# tools/dsrom_s81_fulldie.py abstract: Banded real register stage
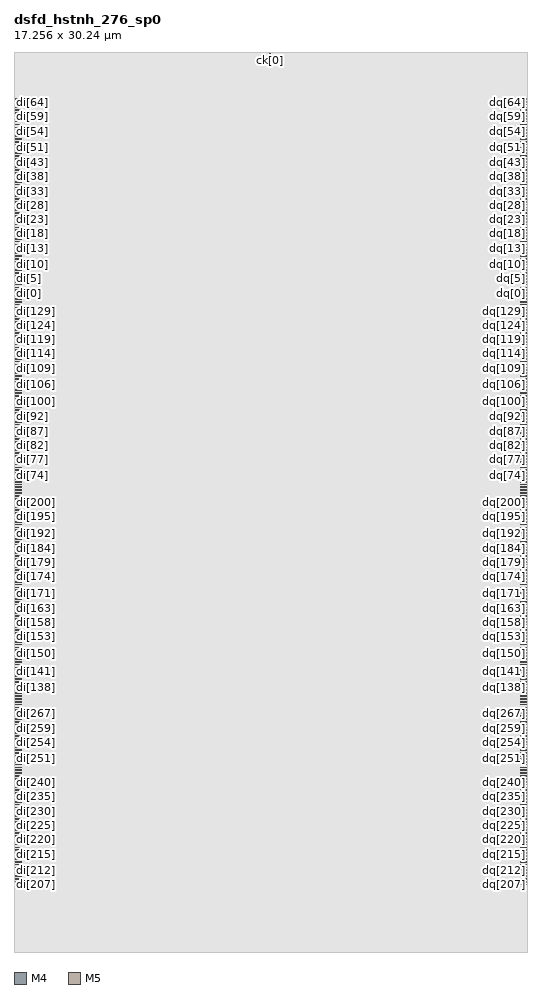
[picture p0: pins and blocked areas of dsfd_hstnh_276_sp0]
MACRO dsfd_hstnh_276_sp0
  CLASS BLOCK ;
  FOREIGN dsfd_hstnh_276_sp0 0 0 ;
  SIZE 17.256 BY 30.240 ;
  SYMMETRY X Y ;
  PIN di[0]
    DIRECTION INOUT ;
    USE SIGNAL ;
    PORT
      LAYER M4 ;
        RECT 0.048 22.128 0.240 22.152 ;
    END
  END di[0]
  PIN di[1]
    DIRECTION INOUT ;
    USE SIGNAL ;
    PORT
      LAYER M4 ;
        RECT 0.048 22.224 0.240 22.248 ;
    END
  END di[1]
  PIN di[2]
    DIRECTION INOUT ;
    USE SIGNAL ;
    PORT
      LAYER M4 ;
        RECT 0.048 22.320 0.240 22.344 ;
    END
  END di[2]
  PIN di[3]
    DIRECTION INOUT ;
    USE SIGNAL ;
    PORT
      LAYER M4 ;
        RECT 0.048 22.416 0.240 22.440 ;
    END
  END di[3]
  PIN di[4]
    DIRECTION INOUT ;
    USE SIGNAL ;
    PORT
      LAYER M4 ;
        RECT 0.048 22.512 0.240 22.536 ;
    END
  END di[4]
  PIN di[5]
    DIRECTION INOUT ;
    USE SIGNAL ;
    PORT
      LAYER M4 ;
        RECT 0.048 22.608 0.240 22.632 ;
    END
  END di[5]
  PIN di[6]
    DIRECTION INOUT ;
    USE SIGNAL ;
    PORT
      LAYER M4 ;
        RECT 0.048 22.704 0.240 22.728 ;
    END
  END di[6]
  PIN di[7]
    DIRECTION INOUT ;
    USE SIGNAL ;
    PORT
      LAYER M4 ;
        RECT 0.048 22.800 0.240 22.824 ;
    END
  END di[7]
  PIN di[8]
    DIRECTION INOUT ;
    USE SIGNAL ;
    PORT
      LAYER M4 ;
        RECT 0.048 22.896 0.240 22.920 ;
    END
  END di[8]
  PIN di[9]
    DIRECTION INOUT ;
    USE SIGNAL ;
    PORT
      LAYER M4 ;
        RECT 0.048 22.992 0.240 23.016 ;
    END
  END di[9]
  PIN di[10]
    DIRECTION INOUT ;
    USE SIGNAL ;
    PORT
      LAYER M4 ;
        RECT 0.048 23.088 0.240 23.112 ;
    END
  END di[10]
  PIN di[11]
    DIRECTION INOUT ;
    USE SIGNAL ;
    PORT
      LAYER M4 ;
        RECT 0.048 23.184 0.240 23.208 ;
    END
  END di[11]
  PIN di[12]
    DIRECTION INOUT ;
    USE SIGNAL ;
    PORT
      LAYER M4 ;
        RECT 0.048 23.280 0.240 23.304 ;
    END
  END di[12]
  PIN di[13]
    DIRECTION INOUT ;
    USE SIGNAL ;
    PORT
      LAYER M4 ;
        RECT 0.048 23.376 0.240 23.400 ;
    END
  END di[13]
  PIN di[14]
    DIRECTION INOUT ;
    USE SIGNAL ;
    PORT
      LAYER M4 ;
        RECT 0.048 23.472 0.240 23.496 ;
    END
  END di[14]
  PIN di[15]
    DIRECTION INOUT ;
    USE SIGNAL ;
    PORT
      LAYER M4 ;
        RECT 0.048 23.568 0.240 23.592 ;
    END
  END di[15]
  PIN di[16]
    DIRECTION INOUT ;
    USE SIGNAL ;
    PORT
      LAYER M4 ;
        RECT 0.048 23.664 0.240 23.688 ;
    END
  END di[16]
  PIN di[17]
    DIRECTION INOUT ;
    USE SIGNAL ;
    PORT
      LAYER M4 ;
        RECT 0.048 23.760 0.240 23.784 ;
    END
  END di[17]
  PIN di[18]
    DIRECTION INOUT ;
    USE SIGNAL ;
    PORT
      LAYER M4 ;
        RECT 0.048 23.856 0.240 23.880 ;
    END
  END di[18]
  PIN di[19]
    DIRECTION INOUT ;
    USE SIGNAL ;
    PORT
      LAYER M4 ;
        RECT 0.048 23.952 0.240 23.976 ;
    END
  END di[19]
  PIN di[20]
    DIRECTION INOUT ;
    USE SIGNAL ;
    PORT
      LAYER M4 ;
        RECT 0.048 24.048 0.240 24.072 ;
    END
  END di[20]
  PIN di[21]
    DIRECTION INOUT ;
    USE SIGNAL ;
    PORT
      LAYER M4 ;
        RECT 0.048 24.144 0.240 24.168 ;
    END
  END di[21]
  PIN di[22]
    DIRECTION INOUT ;
    USE SIGNAL ;
    PORT
      LAYER M4 ;
        RECT 0.048 24.240 0.240 24.264 ;
    END
  END di[22]
  PIN di[23]
    DIRECTION INOUT ;
    USE SIGNAL ;
    PORT
      LAYER M4 ;
        RECT 0.048 24.336 0.240 24.360 ;
    END
  END di[23]
  PIN di[24]
    DIRECTION INOUT ;
    USE SIGNAL ;
    PORT
      LAYER M4 ;
        RECT 0.048 24.432 0.240 24.456 ;
    END
  END di[24]
  PIN di[25]
    DIRECTION INOUT ;
    USE SIGNAL ;
    PORT
      LAYER M4 ;
        RECT 0.048 24.528 0.240 24.552 ;
    END
  END di[25]
  PIN di[26]
    DIRECTION INOUT ;
    USE SIGNAL ;
    PORT
      LAYER M4 ;
        RECT 0.048 24.624 0.240 24.648 ;
    END
  END di[26]
  PIN di[27]
    DIRECTION INOUT ;
    USE SIGNAL ;
    PORT
      LAYER M4 ;
        RECT 0.048 24.720 0.240 24.744 ;
    END
  END di[27]
  PIN di[28]
    DIRECTION INOUT ;
    USE SIGNAL ;
    PORT
      LAYER M4 ;
        RECT 0.048 24.816 0.240 24.840 ;
    END
  END di[28]
  PIN di[29]
    DIRECTION INOUT ;
    USE SIGNAL ;
    PORT
      LAYER M4 ;
        RECT 0.048 24.912 0.240 24.936 ;
    END
  END di[29]
  PIN di[30]
    DIRECTION INOUT ;
    USE SIGNAL ;
    PORT
      LAYER M4 ;
        RECT 0.048 25.008 0.240 25.032 ;
    END
  END di[30]
  PIN di[31]
    DIRECTION INOUT ;
    USE SIGNAL ;
    PORT
      LAYER M4 ;
        RECT 0.048 25.104 0.240 25.128 ;
    END
  END di[31]
  PIN di[32]
    DIRECTION INOUT ;
    USE SIGNAL ;
    PORT
      LAYER M4 ;
        RECT 0.048 25.200 0.240 25.224 ;
    END
  END di[32]
  PIN di[33]
    DIRECTION INOUT ;
    USE SIGNAL ;
    PORT
      LAYER M4 ;
        RECT 0.048 25.296 0.240 25.320 ;
    END
  END di[33]
  PIN di[34]
    DIRECTION INOUT ;
    USE SIGNAL ;
    PORT
      LAYER M4 ;
        RECT 0.048 25.392 0.240 25.416 ;
    END
  END di[34]
  PIN di[35]
    DIRECTION INOUT ;
    USE SIGNAL ;
    PORT
      LAYER M4 ;
        RECT 0.048 25.488 0.240 25.512 ;
    END
  END di[35]
  PIN di[36]
    DIRECTION INOUT ;
    USE SIGNAL ;
    PORT
      LAYER M4 ;
        RECT 0.048 25.584 0.240 25.608 ;
    END
  END di[36]
  PIN di[37]
    DIRECTION INOUT ;
    USE SIGNAL ;
    PORT
      LAYER M4 ;
        RECT 0.048 25.680 0.240 25.704 ;
    END
  END di[37]
  PIN di[38]
    DIRECTION INOUT ;
    USE SIGNAL ;
    PORT
      LAYER M4 ;
        RECT 0.048 25.776 0.240 25.800 ;
    END
  END di[38]
  PIN di[39]
    DIRECTION INOUT ;
    USE SIGNAL ;
    PORT
      LAYER M4 ;
        RECT 0.048 25.872 0.240 25.896 ;
    END
  END di[39]
  PIN di[40]
    DIRECTION INOUT ;
    USE SIGNAL ;
    PORT
      LAYER M4 ;
        RECT 0.048 25.968 0.240 25.992 ;
    END
  END di[40]
  PIN di[41]
    DIRECTION INOUT ;
    USE SIGNAL ;
    PORT
      LAYER M4 ;
        RECT 0.048 26.064 0.240 26.088 ;
    END
  END di[41]
  PIN di[42]
    DIRECTION INOUT ;
    USE SIGNAL ;
    PORT
      LAYER M4 ;
        RECT 0.048 26.160 0.240 26.184 ;
    END
  END di[42]
  PIN di[43]
    DIRECTION INOUT ;
    USE SIGNAL ;
    PORT
      LAYER M4 ;
        RECT 0.048 26.256 0.240 26.280 ;
    END
  END di[43]
  PIN di[44]
    DIRECTION INOUT ;
    USE SIGNAL ;
    PORT
      LAYER M4 ;
        RECT 0.048 26.352 0.240 26.376 ;
    END
  END di[44]
  PIN di[45]
    DIRECTION INOUT ;
    USE SIGNAL ;
    PORT
      LAYER M4 ;
        RECT 0.048 26.448 0.240 26.472 ;
    END
  END di[45]
  PIN di[46]
    DIRECTION INOUT ;
    USE SIGNAL ;
    PORT
      LAYER M4 ;
        RECT 0.048 26.544 0.240 26.568 ;
    END
  END di[46]
  PIN di[47]
    DIRECTION INOUT ;
    USE SIGNAL ;
    PORT
      LAYER M4 ;
        RECT 0.048 26.640 0.240 26.664 ;
    END
  END di[47]
  PIN di[48]
    DIRECTION INOUT ;
    USE SIGNAL ;
    PORT
      LAYER M4 ;
        RECT 0.048 26.736 0.240 26.760 ;
    END
  END di[48]
  PIN di[49]
    DIRECTION INOUT ;
    USE SIGNAL ;
    PORT
      LAYER M4 ;
        RECT 0.048 26.832 0.240 26.856 ;
    END
  END di[49]
  PIN di[50]
    DIRECTION INOUT ;
    USE SIGNAL ;
    PORT
      LAYER M4 ;
        RECT 0.048 26.928 0.240 26.952 ;
    END
  END di[50]
  PIN di[51]
    DIRECTION INOUT ;
    USE SIGNAL ;
    PORT
      LAYER M4 ;
        RECT 0.048 27.024 0.240 27.048 ;
    END
  END di[51]
  PIN di[52]
    DIRECTION INOUT ;
    USE SIGNAL ;
    PORT
      LAYER M4 ;
        RECT 0.048 27.120 0.240 27.144 ;
    END
  END di[52]
  PIN di[53]
    DIRECTION INOUT ;
    USE SIGNAL ;
    PORT
      LAYER M4 ;
        RECT 0.048 27.216 0.240 27.240 ;
    END
  END di[53]
  PIN di[54]
    DIRECTION INOUT ;
    USE SIGNAL ;
    PORT
      LAYER M4 ;
        RECT 0.048 27.312 0.240 27.336 ;
    END
  END di[54]
  PIN di[55]
    DIRECTION INOUT ;
    USE SIGNAL ;
    PORT
      LAYER M4 ;
        RECT 0.048 27.408 0.240 27.432 ;
    END
  END di[55]
  PIN di[56]
    DIRECTION INOUT ;
    USE SIGNAL ;
    PORT
      LAYER M4 ;
        RECT 0.048 27.504 0.240 27.528 ;
    END
  END di[56]
  PIN di[57]
    DIRECTION INOUT ;
    USE SIGNAL ;
    PORT
      LAYER M4 ;
        RECT 0.048 27.600 0.240 27.624 ;
    END
  END di[57]
  PIN di[58]
    DIRECTION INOUT ;
    USE SIGNAL ;
    PORT
      LAYER M4 ;
        RECT 0.048 27.696 0.240 27.720 ;
    END
  END di[58]
  PIN di[59]
    DIRECTION INOUT ;
    USE SIGNAL ;
    PORT
      LAYER M4 ;
        RECT 0.048 27.792 0.240 27.816 ;
    END
  END di[59]
  PIN di[60]
    DIRECTION INOUT ;
    USE SIGNAL ;
    PORT
      LAYER M4 ;
        RECT 0.048 27.888 0.240 27.912 ;
    END
  END di[60]
  PIN di[61]
    DIRECTION INOUT ;
    USE SIGNAL ;
    PORT
      LAYER M4 ;
        RECT 0.048 27.984 0.240 28.008 ;
    END
  END di[61]
  PIN di[62]
    DIRECTION INOUT ;
    USE SIGNAL ;
    PORT
      LAYER M4 ;
        RECT 0.048 28.080 0.240 28.104 ;
    END
  END di[62]
  PIN di[63]
    DIRECTION INOUT ;
    USE SIGNAL ;
    PORT
      LAYER M4 ;
        RECT 0.048 28.176 0.240 28.200 ;
    END
  END di[63]
  PIN di[64]
    DIRECTION INOUT ;
    USE SIGNAL ;
    PORT
      LAYER M4 ;
        RECT 0.048 28.272 0.240 28.296 ;
    END
  END di[64]
  PIN di[65]
    DIRECTION INOUT ;
    USE SIGNAL ;
    PORT
      LAYER M4 ;
        RECT 0.048 28.368 0.240 28.392 ;
    END
  END di[65]
  PIN di[66]
    DIRECTION INOUT ;
    USE SIGNAL ;
    PORT
      LAYER M4 ;
        RECT 0.048 28.464 0.240 28.488 ;
    END
  END di[66]
  PIN di[67]
    DIRECTION INOUT ;
    USE SIGNAL ;
    PORT
      LAYER M4 ;
        RECT 0.048 28.560 0.240 28.584 ;
    END
  END di[67]
  PIN di[68]
    DIRECTION INOUT ;
    USE SIGNAL ;
    PORT
      LAYER M4 ;
        RECT 0.048 28.656 0.240 28.680 ;
    END
  END di[68]
  PIN di[69]
    DIRECTION INOUT ;
    USE SIGNAL ;
    PORT
      LAYER M4 ;
        RECT 0.048 15.504 0.240 15.528 ;
    END
  END di[69]
  PIN di[70]
    DIRECTION INOUT ;
    USE SIGNAL ;
    PORT
      LAYER M4 ;
        RECT 0.048 15.600 0.240 15.624 ;
    END
  END di[70]
  PIN di[71]
    DIRECTION INOUT ;
    USE SIGNAL ;
    PORT
      LAYER M4 ;
        RECT 0.048 15.696 0.240 15.720 ;
    END
  END di[71]
  PIN di[72]
    DIRECTION INOUT ;
    USE SIGNAL ;
    PORT
      LAYER M4 ;
        RECT 0.048 15.792 0.240 15.816 ;
    END
  END di[72]
  PIN di[73]
    DIRECTION INOUT ;
    USE SIGNAL ;
    PORT
      LAYER M4 ;
        RECT 0.048 15.888 0.240 15.912 ;
    END
  END di[73]
  PIN di[74]
    DIRECTION INOUT ;
    USE SIGNAL ;
    PORT
      LAYER M4 ;
        RECT 0.048 15.984 0.240 16.008 ;
    END
  END di[74]
  PIN di[75]
    DIRECTION INOUT ;
    USE SIGNAL ;
    PORT
      LAYER M4 ;
        RECT 0.048 16.080 0.240 16.104 ;
    END
  END di[75]
  PIN di[76]
    DIRECTION INOUT ;
    USE SIGNAL ;
    PORT
      LAYER M4 ;
        RECT 0.048 16.176 0.240 16.200 ;
    END
  END di[76]
  PIN di[77]
    DIRECTION INOUT ;
    USE SIGNAL ;
    PORT
      LAYER M4 ;
        RECT 0.048 16.272 0.240 16.296 ;
    END
  END di[77]
  PIN di[78]
    DIRECTION INOUT ;
    USE SIGNAL ;
    PORT
      LAYER M4 ;
        RECT 0.048 16.368 0.240 16.392 ;
    END
  END di[78]
  PIN di[79]
    DIRECTION INOUT ;
    USE SIGNAL ;
    PORT
      LAYER M4 ;
        RECT 0.048 16.464 0.240 16.488 ;
    END
  END di[79]
  PIN di[80]
    DIRECTION INOUT ;
    USE SIGNAL ;
    PORT
      LAYER M4 ;
        RECT 0.048 16.560 0.240 16.584 ;
    END
  END di[80]
  PIN di[81]
    DIRECTION INOUT ;
    USE SIGNAL ;
    PORT
      LAYER M4 ;
        RECT 0.048 16.656 0.240 16.680 ;
    END
  END di[81]
  PIN di[82]
    DIRECTION INOUT ;
    USE SIGNAL ;
    PORT
      LAYER M4 ;
        RECT 0.048 16.752 0.240 16.776 ;
    END
  END di[82]
  PIN di[83]
    DIRECTION INOUT ;
    USE SIGNAL ;
    PORT
      LAYER M4 ;
        RECT 0.048 16.848 0.240 16.872 ;
    END
  END di[83]
  PIN di[84]
    DIRECTION INOUT ;
    USE SIGNAL ;
    PORT
      LAYER M4 ;
        RECT 0.048 16.944 0.240 16.968 ;
    END
  END di[84]
  PIN di[85]
    DIRECTION INOUT ;
    USE SIGNAL ;
    PORT
      LAYER M4 ;
        RECT 0.048 17.040 0.240 17.064 ;
    END
  END di[85]
  PIN di[86]
    DIRECTION INOUT ;
    USE SIGNAL ;
    PORT
      LAYER M4 ;
        RECT 0.048 17.136 0.240 17.160 ;
    END
  END di[86]
  PIN di[87]
    DIRECTION INOUT ;
    USE SIGNAL ;
    PORT
      LAYER M4 ;
        RECT 0.048 17.232 0.240 17.256 ;
    END
  END di[87]
  PIN di[88]
    DIRECTION INOUT ;
    USE SIGNAL ;
    PORT
      LAYER M4 ;
        RECT 0.048 17.328 0.240 17.352 ;
    END
  END di[88]
  PIN di[89]
    DIRECTION INOUT ;
    USE SIGNAL ;
    PORT
      LAYER M4 ;
        RECT 0.048 17.424 0.240 17.448 ;
    END
  END di[89]
  PIN di[90]
    DIRECTION INOUT ;
    USE SIGNAL ;
    PORT
      LAYER M4 ;
        RECT 0.048 17.520 0.240 17.544 ;
    END
  END di[90]
  PIN di[91]
    DIRECTION INOUT ;
    USE SIGNAL ;
    PORT
      LAYER M4 ;
        RECT 0.048 17.616 0.240 17.640 ;
    END
  END di[91]
  PIN di[92]
    DIRECTION INOUT ;
    USE SIGNAL ;
    PORT
      LAYER M4 ;
        RECT 0.048 17.712 0.240 17.736 ;
    END
  END di[92]
  PIN di[93]
    DIRECTION INOUT ;
    USE SIGNAL ;
    PORT
      LAYER M4 ;
        RECT 0.048 17.808 0.240 17.832 ;
    END
  END di[93]
  PIN di[94]
    DIRECTION INOUT ;
    USE SIGNAL ;
    PORT
      LAYER M4 ;
        RECT 0.048 17.904 0.240 17.928 ;
    END
  END di[94]
  PIN di[95]
    DIRECTION INOUT ;
    USE SIGNAL ;
    PORT
      LAYER M4 ;
        RECT 0.048 18.000 0.240 18.024 ;
    END
  END di[95]
  PIN di[96]
    DIRECTION INOUT ;
    USE SIGNAL ;
    PORT
      LAYER M4 ;
        RECT 0.048 18.096 0.240 18.120 ;
    END
  END di[96]
  PIN di[97]
    DIRECTION INOUT ;
    USE SIGNAL ;
    PORT
      LAYER M4 ;
        RECT 0.048 18.192 0.240 18.216 ;
    END
  END di[97]
  PIN di[98]
    DIRECTION INOUT ;
    USE SIGNAL ;
    PORT
      LAYER M4 ;
        RECT 0.048 18.288 0.240 18.312 ;
    END
  END di[98]
  PIN di[99]
    DIRECTION INOUT ;
    USE SIGNAL ;
    PORT
      LAYER M4 ;
        RECT 0.048 18.384 0.240 18.408 ;
    END
  END di[99]
  PIN di[100]
    DIRECTION INOUT ;
    USE SIGNAL ;
    PORT
      LAYER M4 ;
        RECT 0.048 18.480 0.240 18.504 ;
    END
  END di[100]
  PIN di[101]
    DIRECTION INOUT ;
    USE SIGNAL ;
    PORT
      LAYER M4 ;
        RECT 0.048 18.576 0.240 18.600 ;
    END
  END di[101]
  PIN di[102]
    DIRECTION INOUT ;
    USE SIGNAL ;
    PORT
      LAYER M4 ;
        RECT 0.048 18.672 0.240 18.696 ;
    END
  END di[102]
  PIN di[103]
    DIRECTION INOUT ;
    USE SIGNAL ;
    PORT
      LAYER M4 ;
        RECT 0.048 18.768 0.240 18.792 ;
    END
  END di[103]
  PIN di[104]
    DIRECTION INOUT ;
    USE SIGNAL ;
    PORT
      LAYER M4 ;
        RECT 0.048 18.864 0.240 18.888 ;
    END
  END di[104]
  PIN di[105]
    DIRECTION INOUT ;
    USE SIGNAL ;
    PORT
      LAYER M4 ;
        RECT 0.048 18.960 0.240 18.984 ;
    END
  END di[105]
  PIN di[106]
    DIRECTION INOUT ;
    USE SIGNAL ;
    PORT
      LAYER M4 ;
        RECT 0.048 19.056 0.240 19.080 ;
    END
  END di[106]
  PIN di[107]
    DIRECTION INOUT ;
    USE SIGNAL ;
    PORT
      LAYER M4 ;
        RECT 0.048 19.152 0.240 19.176 ;
    END
  END di[107]
  PIN di[108]
    DIRECTION INOUT ;
    USE SIGNAL ;
    PORT
      LAYER M4 ;
        RECT 0.048 19.248 0.240 19.272 ;
    END
  END di[108]
  PIN di[109]
    DIRECTION INOUT ;
    USE SIGNAL ;
    PORT
      LAYER M4 ;
        RECT 0.048 19.344 0.240 19.368 ;
    END
  END di[109]
  PIN di[110]
    DIRECTION INOUT ;
    USE SIGNAL ;
    PORT
      LAYER M4 ;
        RECT 0.048 19.440 0.240 19.464 ;
    END
  END di[110]
  PIN di[111]
    DIRECTION INOUT ;
    USE SIGNAL ;
    PORT
      LAYER M4 ;
        RECT 0.048 19.536 0.240 19.560 ;
    END
  END di[111]
  PIN di[112]
    DIRECTION INOUT ;
    USE SIGNAL ;
    PORT
      LAYER M4 ;
        RECT 0.048 19.632 0.240 19.656 ;
    END
  END di[112]
  PIN di[113]
    DIRECTION INOUT ;
    USE SIGNAL ;
    PORT
      LAYER M4 ;
        RECT 0.048 19.728 0.240 19.752 ;
    END
  END di[113]
  PIN di[114]
    DIRECTION INOUT ;
    USE SIGNAL ;
    PORT
      LAYER M4 ;
        RECT 0.048 19.824 0.240 19.848 ;
    END
  END di[114]
  PIN di[115]
    DIRECTION INOUT ;
    USE SIGNAL ;
    PORT
      LAYER M4 ;
        RECT 0.048 19.920 0.240 19.944 ;
    END
  END di[115]
  PIN di[116]
    DIRECTION INOUT ;
    USE SIGNAL ;
    PORT
      LAYER M4 ;
        RECT 0.048 20.016 0.240 20.040 ;
    END
  END di[116]
  PIN di[117]
    DIRECTION INOUT ;
    USE SIGNAL ;
    PORT
      LAYER M4 ;
        RECT 0.048 20.112 0.240 20.136 ;
    END
  END di[117]
  PIN di[118]
    DIRECTION INOUT ;
    USE SIGNAL ;
    PORT
      LAYER M4 ;
        RECT 0.048 20.208 0.240 20.232 ;
    END
  END di[118]
  PIN di[119]
    DIRECTION INOUT ;
    USE SIGNAL ;
    PORT
      LAYER M4 ;
        RECT 0.048 20.304 0.240 20.328 ;
    END
  END di[119]
  PIN di[120]
    DIRECTION INOUT ;
    USE SIGNAL ;
    PORT
      LAYER M4 ;
        RECT 0.048 20.400 0.240 20.424 ;
    END
  END di[120]
  PIN di[121]
    DIRECTION INOUT ;
    USE SIGNAL ;
    PORT
      LAYER M4 ;
        RECT 0.048 20.496 0.240 20.520 ;
    END
  END di[121]
  PIN di[122]
    DIRECTION INOUT ;
    USE SIGNAL ;
    PORT
      LAYER M4 ;
        RECT 0.048 20.592 0.240 20.616 ;
    END
  END di[122]
  PIN di[123]
    DIRECTION INOUT ;
    USE SIGNAL ;
    PORT
      LAYER M4 ;
        RECT 0.048 20.688 0.240 20.712 ;
    END
  END di[123]
  PIN di[124]
    DIRECTION INOUT ;
    USE SIGNAL ;
    PORT
      LAYER M4 ;
        RECT 0.048 20.784 0.240 20.808 ;
    END
  END di[124]
  PIN di[125]
    DIRECTION INOUT ;
    USE SIGNAL ;
    PORT
      LAYER M4 ;
        RECT 0.048 20.880 0.240 20.904 ;
    END
  END di[125]
  PIN di[126]
    DIRECTION INOUT ;
    USE SIGNAL ;
    PORT
      LAYER M4 ;
        RECT 0.048 20.976 0.240 21.000 ;
    END
  END di[126]
  PIN di[127]
    DIRECTION INOUT ;
    USE SIGNAL ;
    PORT
      LAYER M4 ;
        RECT 0.048 21.072 0.240 21.096 ;
    END
  END di[127]
  PIN di[128]
    DIRECTION INOUT ;
    USE SIGNAL ;
    PORT
      LAYER M4 ;
        RECT 0.048 21.168 0.240 21.192 ;
    END
  END di[128]
  PIN di[129]
    DIRECTION INOUT ;
    USE SIGNAL ;
    PORT
      LAYER M4 ;
        RECT 0.048 21.264 0.240 21.288 ;
    END
  END di[129]
  PIN di[130]
    DIRECTION INOUT ;
    USE SIGNAL ;
    PORT
      LAYER M4 ;
        RECT 0.048 21.360 0.240 21.384 ;
    END
  END di[130]
  PIN di[131]
    DIRECTION INOUT ;
    USE SIGNAL ;
    PORT
      LAYER M4 ;
        RECT 0.048 21.456 0.240 21.480 ;
    END
  END di[131]
  PIN di[132]
    DIRECTION INOUT ;
    USE SIGNAL ;
    PORT
      LAYER M4 ;
        RECT 0.048 21.552 0.240 21.576 ;
    END
  END di[132]
  PIN di[133]
    DIRECTION INOUT ;
    USE SIGNAL ;
    PORT
      LAYER M4 ;
        RECT 0.048 21.648 0.240 21.672 ;
    END
  END di[133]
  PIN di[134]
    DIRECTION INOUT ;
    USE SIGNAL ;
    PORT
      LAYER M4 ;
        RECT 0.048 21.744 0.240 21.768 ;
    END
  END di[134]
  PIN di[135]
    DIRECTION INOUT ;
    USE SIGNAL ;
    PORT
      LAYER M4 ;
        RECT 0.048 21.840 0.240 21.864 ;
    END
  END di[135]
  PIN di[136]
    DIRECTION INOUT ;
    USE SIGNAL ;
    PORT
      LAYER M4 ;
        RECT 0.048 21.936 0.240 21.960 ;
    END
  END di[136]
  PIN di[137]
    DIRECTION INOUT ;
    USE SIGNAL ;
    PORT
      LAYER M4 ;
        RECT 0.048 22.032 0.240 22.056 ;
    END
  END di[137]
  PIN di[138]
    DIRECTION INOUT ;
    USE SIGNAL ;
    PORT
      LAYER M4 ;
        RECT 0.048 8.880 0.240 8.904 ;
    END
  END di[138]
  PIN di[139]
    DIRECTION INOUT ;
    USE SIGNAL ;
    PORT
      LAYER M4 ;
        RECT 0.048 8.976 0.240 9.000 ;
    END
  END di[139]
  PIN di[140]
    DIRECTION INOUT ;
    USE SIGNAL ;
    PORT
      LAYER M4 ;
        RECT 0.048 9.072 0.240 9.096 ;
    END
  END di[140]
  PIN di[141]
    DIRECTION INOUT ;
    USE SIGNAL ;
    PORT
      LAYER M4 ;
        RECT 0.048 9.168 0.240 9.192 ;
    END
  END di[141]
  PIN di[142]
    DIRECTION INOUT ;
    USE SIGNAL ;
    PORT
      LAYER M4 ;
        RECT 0.048 9.264 0.240 9.288 ;
    END
  END di[142]
  PIN di[143]
    DIRECTION INOUT ;
    USE SIGNAL ;
    PORT
      LAYER M4 ;
        RECT 0.048 9.360 0.240 9.384 ;
    END
  END di[143]
  PIN di[144]
    DIRECTION INOUT ;
    USE SIGNAL ;
    PORT
      LAYER M4 ;
        RECT 0.048 9.456 0.240 9.480 ;
    END
  END di[144]
  PIN di[145]
    DIRECTION INOUT ;
    USE SIGNAL ;
    PORT
      LAYER M4 ;
        RECT 0.048 9.552 0.240 9.576 ;
    END
  END di[145]
  PIN di[146]
    DIRECTION INOUT ;
    USE SIGNAL ;
    PORT
      LAYER M4 ;
        RECT 0.048 9.648 0.240 9.672 ;
    END
  END di[146]
  PIN di[147]
    DIRECTION INOUT ;
    USE SIGNAL ;
    PORT
      LAYER M4 ;
        RECT 0.048 9.744 0.240 9.768 ;
    END
  END di[147]
  PIN di[148]
    DIRECTION INOUT ;
    USE SIGNAL ;
    PORT
      LAYER M4 ;
        RECT 0.048 9.840 0.240 9.864 ;
    END
  END di[148]
  PIN di[149]
    DIRECTION INOUT ;
    USE SIGNAL ;
    PORT
      LAYER M4 ;
        RECT 0.048 9.936 0.240 9.960 ;
    END
  END di[149]
  PIN di[150]
    DIRECTION INOUT ;
    USE SIGNAL ;
    PORT
      LAYER M4 ;
        RECT 0.048 10.032 0.240 10.056 ;
    END
  END di[150]
  PIN di[151]
    DIRECTION INOUT ;
    USE SIGNAL ;
    PORT
      LAYER M4 ;
        RECT 0.048 10.128 0.240 10.152 ;
    END
  END di[151]
  PIN di[152]
    DIRECTION INOUT ;
    USE SIGNAL ;
    PORT
      LAYER M4 ;
        RECT 0.048 10.224 0.240 10.248 ;
    END
  END di[152]
  PIN di[153]
    DIRECTION INOUT ;
    USE SIGNAL ;
    PORT
      LAYER M4 ;
        RECT 0.048 10.320 0.240 10.344 ;
    END
  END di[153]
  PIN di[154]
    DIRECTION INOUT ;
    USE SIGNAL ;
    PORT
      LAYER M4 ;
        RECT 0.048 10.416 0.240 10.440 ;
    END
  END di[154]
  PIN di[155]
    DIRECTION INOUT ;
    USE SIGNAL ;
    PORT
      LAYER M4 ;
        RECT 0.048 10.512 0.240 10.536 ;
    END
  END di[155]
  PIN di[156]
    DIRECTION INOUT ;
    USE SIGNAL ;
    PORT
      LAYER M4 ;
        RECT 0.048 10.608 0.240 10.632 ;
    END
  END di[156]
  PIN di[157]
    DIRECTION INOUT ;
    USE SIGNAL ;
    PORT
      LAYER M4 ;
        RECT 0.048 10.704 0.240 10.728 ;
    END
  END di[157]
  PIN di[158]
    DIRECTION INOUT ;
    USE SIGNAL ;
    PORT
      LAYER M4 ;
        RECT 0.048 10.800 0.240 10.824 ;
    END
  END di[158]
  PIN di[159]
    DIRECTION INOUT ;
    USE SIGNAL ;
    PORT
      LAYER M4 ;
        RECT 0.048 10.896 0.240 10.920 ;
    END
  END di[159]
  PIN di[160]
    DIRECTION INOUT ;
    USE SIGNAL ;
    PORT
      LAYER M4 ;
        RECT 0.048 10.992 0.240 11.016 ;
    END
  END di[160]
  PIN di[161]
    DIRECTION INOUT ;
    USE SIGNAL ;
    PORT
      LAYER M4 ;
        RECT 0.048 11.088 0.240 11.112 ;
    END
  END di[161]
  PIN di[162]
    DIRECTION INOUT ;
    USE SIGNAL ;
    PORT
      LAYER M4 ;
        RECT 0.048 11.184 0.240 11.208 ;
    END
  END di[162]
  PIN di[163]
    DIRECTION INOUT ;
    USE SIGNAL ;
    PORT
      LAYER M4 ;
        RECT 0.048 11.280 0.240 11.304 ;
    END
  END di[163]
  PIN di[164]
    DIRECTION INOUT ;
    USE SIGNAL ;
    PORT
      LAYER M4 ;
        RECT 0.048 11.376 0.240 11.400 ;
    END
  END di[164]
  PIN di[165]
    DIRECTION INOUT ;
    USE SIGNAL ;
    PORT
      LAYER M4 ;
        RECT 0.048 11.472 0.240 11.496 ;
    END
  END di[165]
  PIN di[166]
    DIRECTION INOUT ;
    USE SIGNAL ;
    PORT
      LAYER M4 ;
        RECT 0.048 11.568 0.240 11.592 ;
    END
  END di[166]
  PIN di[167]
    DIRECTION INOUT ;
    USE SIGNAL ;
    PORT
      LAYER M4 ;
        RECT 0.048 11.664 0.240 11.688 ;
    END
  END di[167]
  PIN di[168]
    DIRECTION INOUT ;
    USE SIGNAL ;
    PORT
      LAYER M4 ;
        RECT 0.048 11.760 0.240 11.784 ;
    END
  END di[168]
  PIN di[169]
    DIRECTION INOUT ;
    USE SIGNAL ;
    PORT
      LAYER M4 ;
        RECT 0.048 11.856 0.240 11.880 ;
    END
  END di[169]
  PIN di[170]
    DIRECTION INOUT ;
    USE SIGNAL ;
    PORT
      LAYER M4 ;
        RECT 0.048 11.952 0.240 11.976 ;
    END
  END di[170]
  PIN di[171]
    DIRECTION INOUT ;
    USE SIGNAL ;
    PORT
      LAYER M4 ;
        RECT 0.048 12.048 0.240 12.072 ;
    END
  END di[171]
  PIN di[172]
    DIRECTION INOUT ;
    USE SIGNAL ;
    PORT
      LAYER M4 ;
        RECT 0.048 12.144 0.240 12.168 ;
    END
  END di[172]
  PIN di[173]
    DIRECTION INOUT ;
    USE SIGNAL ;
    PORT
      LAYER M4 ;
        RECT 0.048 12.240 0.240 12.264 ;
    END
  END di[173]
  PIN di[174]
    DIRECTION INOUT ;
    USE SIGNAL ;
    PORT
      LAYER M4 ;
        RECT 0.048 12.336 0.240 12.360 ;
    END
  END di[174]
  PIN di[175]
    DIRECTION INOUT ;
    USE SIGNAL ;
    PORT
      LAYER M4 ;
        RECT 0.048 12.432 0.240 12.456 ;
    END
  END di[175]
  PIN di[176]
    DIRECTION INOUT ;
    USE SIGNAL ;
    PORT
      LAYER M4 ;
        RECT 0.048 12.528 0.240 12.552 ;
    END
  END di[176]
  PIN di[177]
    DIRECTION INOUT ;
    USE SIGNAL ;
    PORT
      LAYER M4 ;
        RECT 0.048 12.624 0.240 12.648 ;
    END
  END di[177]
  PIN di[178]
    DIRECTION INOUT ;
    USE SIGNAL ;
    PORT
      LAYER M4 ;
        RECT 0.048 12.720 0.240 12.744 ;
    END
  END di[178]
  PIN di[179]
    DIRECTION INOUT ;
    USE SIGNAL ;
    PORT
      LAYER M4 ;
        RECT 0.048 12.816 0.240 12.840 ;
    END
  END di[179]
  PIN di[180]
    DIRECTION INOUT ;
    USE SIGNAL ;
    PORT
      LAYER M4 ;
        RECT 0.048 12.912 0.240 12.936 ;
    END
  END di[180]
  PIN di[181]
    DIRECTION INOUT ;
    USE SIGNAL ;
    PORT
      LAYER M4 ;
        RECT 0.048 13.008 0.240 13.032 ;
    END
  END di[181]
  PIN di[182]
    DIRECTION INOUT ;
    USE SIGNAL ;
    PORT
      LAYER M4 ;
        RECT 0.048 13.104 0.240 13.128 ;
    END
  END di[182]
  PIN di[183]
    DIRECTION INOUT ;
    USE SIGNAL ;
    PORT
      LAYER M4 ;
        RECT 0.048 13.200 0.240 13.224 ;
    END
  END di[183]
  PIN di[184]
    DIRECTION INOUT ;
    USE SIGNAL ;
    PORT
      LAYER M4 ;
        RECT 0.048 13.296 0.240 13.320 ;
    END
  END di[184]
  PIN di[185]
    DIRECTION INOUT ;
    USE SIGNAL ;
    PORT
      LAYER M4 ;
        RECT 0.048 13.392 0.240 13.416 ;
    END
  END di[185]
  PIN di[186]
    DIRECTION INOUT ;
    USE SIGNAL ;
    PORT
      LAYER M4 ;
        RECT 0.048 13.488 0.240 13.512 ;
    END
  END di[186]
  PIN di[187]
    DIRECTION INOUT ;
    USE SIGNAL ;
    PORT
      LAYER M4 ;
        RECT 0.048 13.584 0.240 13.608 ;
    END
  END di[187]
  PIN di[188]
    DIRECTION INOUT ;
    USE SIGNAL ;
    PORT
      LAYER M4 ;
        RECT 0.048 13.680 0.240 13.704 ;
    END
  END di[188]
  PIN di[189]
    DIRECTION INOUT ;
    USE SIGNAL ;
    PORT
      LAYER M4 ;
        RECT 0.048 13.776 0.240 13.800 ;
    END
  END di[189]
  PIN di[190]
    DIRECTION INOUT ;
    USE SIGNAL ;
    PORT
      LAYER M4 ;
        RECT 0.048 13.872 0.240 13.896 ;
    END
  END di[190]
  PIN di[191]
    DIRECTION INOUT ;
    USE SIGNAL ;
    PORT
      LAYER M4 ;
        RECT 0.048 13.968 0.240 13.992 ;
    END
  END di[191]
  PIN di[192]
    DIRECTION INOUT ;
    USE SIGNAL ;
    PORT
      LAYER M4 ;
        RECT 0.048 14.064 0.240 14.088 ;
    END
  END di[192]
  PIN di[193]
    DIRECTION INOUT ;
    USE SIGNAL ;
    PORT
      LAYER M4 ;
        RECT 0.048 14.160 0.240 14.184 ;
    END
  END di[193]
  PIN di[194]
    DIRECTION INOUT ;
    USE SIGNAL ;
    PORT
      LAYER M4 ;
        RECT 0.048 14.256 0.240 14.280 ;
    END
  END di[194]
  PIN di[195]
    DIRECTION INOUT ;
    USE SIGNAL ;
    PORT
      LAYER M4 ;
        RECT 0.048 14.352 0.240 14.376 ;
    END
  END di[195]
  PIN di[196]
    DIRECTION INOUT ;
    USE SIGNAL ;
    PORT
      LAYER M4 ;
        RECT 0.048 14.448 0.240 14.472 ;
    END
  END di[196]
  PIN di[197]
    DIRECTION INOUT ;
    USE SIGNAL ;
    PORT
      LAYER M4 ;
        RECT 0.048 14.544 0.240 14.568 ;
    END
  END di[197]
  PIN di[198]
    DIRECTION INOUT ;
    USE SIGNAL ;
    PORT
      LAYER M4 ;
        RECT 0.048 14.640 0.240 14.664 ;
    END
  END di[198]
  PIN di[199]
    DIRECTION INOUT ;
    USE SIGNAL ;
    PORT
      LAYER M4 ;
        RECT 0.048 14.736 0.240 14.760 ;
    END
  END di[199]
  PIN di[200]
    DIRECTION INOUT ;
    USE SIGNAL ;
    PORT
      LAYER M4 ;
        RECT 0.048 14.832 0.240 14.856 ;
    END
  END di[200]
  PIN di[201]
    DIRECTION INOUT ;
    USE SIGNAL ;
    PORT
      LAYER M4 ;
        RECT 0.048 14.928 0.240 14.952 ;
    END
  END di[201]
  PIN di[202]
    DIRECTION INOUT ;
    USE SIGNAL ;
    PORT
      LAYER M4 ;
        RECT 0.048 15.024 0.240 15.048 ;
    END
  END di[202]
  PIN di[203]
    DIRECTION INOUT ;
    USE SIGNAL ;
    PORT
      LAYER M4 ;
        RECT 0.048 15.120 0.240 15.144 ;
    END
  END di[203]
  PIN di[204]
    DIRECTION INOUT ;
    USE SIGNAL ;
    PORT
      LAYER M4 ;
        RECT 0.048 15.216 0.240 15.240 ;
    END
  END di[204]
  PIN di[205]
    DIRECTION INOUT ;
    USE SIGNAL ;
    PORT
      LAYER M4 ;
        RECT 0.048 15.312 0.240 15.336 ;
    END
  END di[205]
  PIN di[206]
    DIRECTION INOUT ;
    USE SIGNAL ;
    PORT
      LAYER M4 ;
        RECT 0.048 15.408 0.240 15.432 ;
    END
  END di[206]
  PIN di[207]
    DIRECTION INOUT ;
    USE SIGNAL ;
    PORT
      LAYER M4 ;
        RECT 0.048 2.256 0.240 2.280 ;
    END
  END di[207]
  PIN di[208]
    DIRECTION INOUT ;
    USE SIGNAL ;
    PORT
      LAYER M4 ;
        RECT 0.048 2.352 0.240 2.376 ;
    END
  END di[208]
  PIN di[209]
    DIRECTION INOUT ;
    USE SIGNAL ;
    PORT
      LAYER M4 ;
        RECT 0.048 2.448 0.240 2.472 ;
    END
  END di[209]
  PIN di[210]
    DIRECTION INOUT ;
    USE SIGNAL ;
    PORT
      LAYER M4 ;
        RECT 0.048 2.544 0.240 2.568 ;
    END
  END di[210]
  PIN di[211]
    DIRECTION INOUT ;
    USE SIGNAL ;
    PORT
      LAYER M4 ;
        RECT 0.048 2.640 0.240 2.664 ;
    END
  END di[211]
  PIN di[212]
    DIRECTION INOUT ;
    USE SIGNAL ;
    PORT
      LAYER M4 ;
        RECT 0.048 2.736 0.240 2.760 ;
    END
  END di[212]
  PIN di[213]
    DIRECTION INOUT ;
    USE SIGNAL ;
    PORT
      LAYER M4 ;
        RECT 0.048 2.832 0.240 2.856 ;
    END
  END di[213]
  PIN di[214]
    DIRECTION INOUT ;
    USE SIGNAL ;
    PORT
      LAYER M4 ;
        RECT 0.048 2.928 0.240 2.952 ;
    END
  END di[214]
  PIN di[215]
    DIRECTION INOUT ;
    USE SIGNAL ;
    PORT
      LAYER M4 ;
        RECT 0.048 3.024 0.240 3.048 ;
    END
  END di[215]
  PIN di[216]
    DIRECTION INOUT ;
    USE SIGNAL ;
    PORT
      LAYER M4 ;
        RECT 0.048 3.120 0.240 3.144 ;
    END
  END di[216]
  PIN di[217]
    DIRECTION INOUT ;
    USE SIGNAL ;
    PORT
      LAYER M4 ;
        RECT 0.048 3.216 0.240 3.240 ;
    END
  END di[217]
  PIN di[218]
    DIRECTION INOUT ;
    USE SIGNAL ;
    PORT
      LAYER M4 ;
        RECT 0.048 3.312 0.240 3.336 ;
    END
  END di[218]
  PIN di[219]
    DIRECTION INOUT ;
    USE SIGNAL ;
    PORT
      LAYER M4 ;
        RECT 0.048 3.408 0.240 3.432 ;
    END
  END di[219]
  PIN di[220]
    DIRECTION INOUT ;
    USE SIGNAL ;
    PORT
      LAYER M4 ;
        RECT 0.048 3.504 0.240 3.528 ;
    END
  END di[220]
  PIN di[221]
    DIRECTION INOUT ;
    USE SIGNAL ;
    PORT
      LAYER M4 ;
        RECT 0.048 3.600 0.240 3.624 ;
    END
  END di[221]
  PIN di[222]
    DIRECTION INOUT ;
    USE SIGNAL ;
    PORT
      LAYER M4 ;
        RECT 0.048 3.696 0.240 3.720 ;
    END
  END di[222]
  PIN di[223]
    DIRECTION INOUT ;
    USE SIGNAL ;
    PORT
      LAYER M4 ;
        RECT 0.048 3.792 0.240 3.816 ;
    END
  END di[223]
  PIN di[224]
    DIRECTION INOUT ;
    USE SIGNAL ;
    PORT
      LAYER M4 ;
        RECT 0.048 3.888 0.240 3.912 ;
    END
  END di[224]
  PIN di[225]
    DIRECTION INOUT ;
    USE SIGNAL ;
    PORT
      LAYER M4 ;
        RECT 0.048 3.984 0.240 4.008 ;
    END
  END di[225]
  PIN di[226]
    DIRECTION INOUT ;
    USE SIGNAL ;
    PORT
      LAYER M4 ;
        RECT 0.048 4.080 0.240 4.104 ;
    END
  END di[226]
  PIN di[227]
    DIRECTION INOUT ;
    USE SIGNAL ;
    PORT
      LAYER M4 ;
        RECT 0.048 4.176 0.240 4.200 ;
    END
  END di[227]
  PIN di[228]
    DIRECTION INOUT ;
    USE SIGNAL ;
    PORT
      LAYER M4 ;
        RECT 0.048 4.272 0.240 4.296 ;
    END
  END di[228]
  PIN di[229]
    DIRECTION INOUT ;
    USE SIGNAL ;
    PORT
      LAYER M4 ;
        RECT 0.048 4.368 0.240 4.392 ;
    END
  END di[229]
  PIN di[230]
    DIRECTION INOUT ;
    USE SIGNAL ;
    PORT
      LAYER M4 ;
        RECT 0.048 4.464 0.240 4.488 ;
    END
  END di[230]
  PIN di[231]
    DIRECTION INOUT ;
    USE SIGNAL ;
    PORT
      LAYER M4 ;
        RECT 0.048 4.560 0.240 4.584 ;
    END
  END di[231]
  PIN di[232]
    DIRECTION INOUT ;
    USE SIGNAL ;
    PORT
      LAYER M4 ;
        RECT 0.048 4.656 0.240 4.680 ;
    END
  END di[232]
  PIN di[233]
    DIRECTION INOUT ;
    USE SIGNAL ;
    PORT
      LAYER M4 ;
        RECT 0.048 4.752 0.240 4.776 ;
    END
  END di[233]
  PIN di[234]
    DIRECTION INOUT ;
    USE SIGNAL ;
    PORT
      LAYER M4 ;
        RECT 0.048 4.848 0.240 4.872 ;
    END
  END di[234]
  PIN di[235]
    DIRECTION INOUT ;
    USE SIGNAL ;
    PORT
      LAYER M4 ;
        RECT 0.048 4.944 0.240 4.968 ;
    END
  END di[235]
  PIN di[236]
    DIRECTION INOUT ;
    USE SIGNAL ;
    PORT
      LAYER M4 ;
        RECT 0.048 5.040 0.240 5.064 ;
    END
  END di[236]
  PIN di[237]
    DIRECTION INOUT ;
    USE SIGNAL ;
    PORT
      LAYER M4 ;
        RECT 0.048 5.136 0.240 5.160 ;
    END
  END di[237]
  PIN di[238]
    DIRECTION INOUT ;
    USE SIGNAL ;
    PORT
      LAYER M4 ;
        RECT 0.048 5.232 0.240 5.256 ;
    END
  END di[238]
  PIN di[239]
    DIRECTION INOUT ;
    USE SIGNAL ;
    PORT
      LAYER M4 ;
        RECT 0.048 5.328 0.240 5.352 ;
    END
  END di[239]
  PIN di[240]
    DIRECTION INOUT ;
    USE SIGNAL ;
    PORT
      LAYER M4 ;
        RECT 0.048 5.424 0.240 5.448 ;
    END
  END di[240]
  PIN di[241]
    DIRECTION INOUT ;
    USE SIGNAL ;
    PORT
      LAYER M4 ;
        RECT 0.048 5.520 0.240 5.544 ;
    END
  END di[241]
  PIN di[242]
    DIRECTION INOUT ;
    USE SIGNAL ;
    PORT
      LAYER M4 ;
        RECT 0.048 5.616 0.240 5.640 ;
    END
  END di[242]
  PIN di[243]
    DIRECTION INOUT ;
    USE SIGNAL ;
    PORT
      LAYER M4 ;
        RECT 0.048 5.712 0.240 5.736 ;
    END
  END di[243]
  PIN di[244]
    DIRECTION INOUT ;
    USE SIGNAL ;
    PORT
      LAYER M4 ;
        RECT 0.048 5.808 0.240 5.832 ;
    END
  END di[244]
  PIN di[245]
    DIRECTION INOUT ;
    USE SIGNAL ;
    PORT
      LAYER M4 ;
        RECT 0.048 5.904 0.240 5.928 ;
    END
  END di[245]
  PIN di[246]
    DIRECTION INOUT ;
    USE SIGNAL ;
    PORT
      LAYER M4 ;
        RECT 0.048 6.000 0.240 6.024 ;
    END
  END di[246]
  PIN di[247]
    DIRECTION INOUT ;
    USE SIGNAL ;
    PORT
      LAYER M4 ;
        RECT 0.048 6.096 0.240 6.120 ;
    END
  END di[247]
  PIN di[248]
    DIRECTION INOUT ;
    USE SIGNAL ;
    PORT
      LAYER M4 ;
        RECT 0.048 6.192 0.240 6.216 ;
    END
  END di[248]
  PIN di[249]
    DIRECTION INOUT ;
    USE SIGNAL ;
    PORT
      LAYER M4 ;
        RECT 0.048 6.288 0.240 6.312 ;
    END
  END di[249]
  PIN di[250]
    DIRECTION INOUT ;
    USE SIGNAL ;
    PORT
      LAYER M4 ;
        RECT 0.048 6.384 0.240 6.408 ;
    END
  END di[250]
  PIN di[251]
    DIRECTION INOUT ;
    USE SIGNAL ;
    PORT
      LAYER M4 ;
        RECT 0.048 6.480 0.240 6.504 ;
    END
  END di[251]
  PIN di[252]
    DIRECTION INOUT ;
    USE SIGNAL ;
    PORT
      LAYER M4 ;
        RECT 0.048 6.576 0.240 6.600 ;
    END
  END di[252]
  PIN di[253]
    DIRECTION INOUT ;
    USE SIGNAL ;
    PORT
      LAYER M4 ;
        RECT 0.048 6.672 0.240 6.696 ;
    END
  END di[253]
  PIN di[254]
    DIRECTION INOUT ;
    USE SIGNAL ;
    PORT
      LAYER M4 ;
        RECT 0.048 6.768 0.240 6.792 ;
    END
  END di[254]
  PIN di[255]
    DIRECTION INOUT ;
    USE SIGNAL ;
    PORT
      LAYER M4 ;
        RECT 0.048 6.864 0.240 6.888 ;
    END
  END di[255]
  PIN di[256]
    DIRECTION INOUT ;
    USE SIGNAL ;
    PORT
      LAYER M4 ;
        RECT 0.048 6.960 0.240 6.984 ;
    END
  END di[256]
  PIN di[257]
    DIRECTION INOUT ;
    USE SIGNAL ;
    PORT
      LAYER M4 ;
        RECT 0.048 7.056 0.240 7.080 ;
    END
  END di[257]
  PIN di[258]
    DIRECTION INOUT ;
    USE SIGNAL ;
    PORT
      LAYER M4 ;
        RECT 0.048 7.152 0.240 7.176 ;
    END
  END di[258]
  PIN di[259]
    DIRECTION INOUT ;
    USE SIGNAL ;
    PORT
      LAYER M4 ;
        RECT 0.048 7.248 0.240 7.272 ;
    END
  END di[259]
  PIN di[260]
    DIRECTION INOUT ;
    USE SIGNAL ;
    PORT
      LAYER M4 ;
        RECT 0.048 7.344 0.240 7.368 ;
    END
  END di[260]
  PIN di[261]
    DIRECTION INOUT ;
    USE SIGNAL ;
    PORT
      LAYER M4 ;
        RECT 0.048 7.440 0.240 7.464 ;
    END
  END di[261]
  PIN di[262]
    DIRECTION INOUT ;
    USE SIGNAL ;
    PORT
      LAYER M4 ;
        RECT 0.048 7.536 0.240 7.560 ;
    END
  END di[262]
  PIN di[263]
    DIRECTION INOUT ;
    USE SIGNAL ;
    PORT
      LAYER M4 ;
        RECT 0.048 7.632 0.240 7.656 ;
    END
  END di[263]
  PIN di[264]
    DIRECTION INOUT ;
    USE SIGNAL ;
    PORT
      LAYER M4 ;
        RECT 0.048 7.728 0.240 7.752 ;
    END
  END di[264]
  PIN di[265]
    DIRECTION INOUT ;
    USE SIGNAL ;
    PORT
      LAYER M4 ;
        RECT 0.048 7.824 0.240 7.848 ;
    END
  END di[265]
  PIN di[266]
    DIRECTION INOUT ;
    USE SIGNAL ;
    PORT
      LAYER M4 ;
        RECT 0.048 7.920 0.240 7.944 ;
    END
  END di[266]
  PIN di[267]
    DIRECTION INOUT ;
    USE SIGNAL ;
    PORT
      LAYER M4 ;
        RECT 0.048 8.016 0.240 8.040 ;
    END
  END di[267]
  PIN di[268]
    DIRECTION INOUT ;
    USE SIGNAL ;
    PORT
      LAYER M4 ;
        RECT 0.048 8.112 0.240 8.136 ;
    END
  END di[268]
  PIN di[269]
    DIRECTION INOUT ;
    USE SIGNAL ;
    PORT
      LAYER M4 ;
        RECT 0.048 8.208 0.240 8.232 ;
    END
  END di[269]
  PIN di[270]
    DIRECTION INOUT ;
    USE SIGNAL ;
    PORT
      LAYER M4 ;
        RECT 0.048 8.304 0.240 8.328 ;
    END
  END di[270]
  PIN di[271]
    DIRECTION INOUT ;
    USE SIGNAL ;
    PORT
      LAYER M4 ;
        RECT 0.048 8.400 0.240 8.424 ;
    END
  END di[271]
  PIN di[272]
    DIRECTION INOUT ;
    USE SIGNAL ;
    PORT
      LAYER M4 ;
        RECT 0.048 8.496 0.240 8.520 ;
    END
  END di[272]
  PIN di[273]
    DIRECTION INOUT ;
    USE SIGNAL ;
    PORT
      LAYER M4 ;
        RECT 0.048 8.592 0.240 8.616 ;
    END
  END di[273]
  PIN di[274]
    DIRECTION INOUT ;
    USE SIGNAL ;
    PORT
      LAYER M4 ;
        RECT 0.048 8.688 0.240 8.712 ;
    END
  END di[274]
  PIN di[275]
    DIRECTION INOUT ;
    USE SIGNAL ;
    PORT
      LAYER M4 ;
        RECT 0.048 8.784 0.240 8.808 ;
    END
  END di[275]
  PIN dq[0]
    DIRECTION INOUT ;
    USE SIGNAL ;
    PORT
      LAYER M4 ;
        RECT 17.016 22.128 17.208 22.152 ;
    END
  END dq[0]
  PIN dq[1]
    DIRECTION INOUT ;
    USE SIGNAL ;
    PORT
      LAYER M4 ;
        RECT 17.016 22.224 17.208 22.248 ;
    END
  END dq[1]
  PIN dq[2]
    DIRECTION INOUT ;
    USE SIGNAL ;
    PORT
      LAYER M4 ;
        RECT 17.016 22.320 17.208 22.344 ;
    END
  END dq[2]
  PIN dq[3]
    DIRECTION INOUT ;
    USE SIGNAL ;
    PORT
      LAYER M4 ;
        RECT 17.016 22.416 17.208 22.440 ;
    END
  END dq[3]
  PIN dq[4]
    DIRECTION INOUT ;
    USE SIGNAL ;
    PORT
      LAYER M4 ;
        RECT 17.016 22.512 17.208 22.536 ;
    END
  END dq[4]
  PIN dq[5]
    DIRECTION INOUT ;
    USE SIGNAL ;
    PORT
      LAYER M4 ;
        RECT 17.016 22.608 17.208 22.632 ;
    END
  END dq[5]
  PIN dq[6]
    DIRECTION INOUT ;
    USE SIGNAL ;
    PORT
      LAYER M4 ;
        RECT 17.016 22.704 17.208 22.728 ;
    END
  END dq[6]
  PIN dq[7]
    DIRECTION INOUT ;
    USE SIGNAL ;
    PORT
      LAYER M4 ;
        RECT 17.016 22.800 17.208 22.824 ;
    END
  END dq[7]
  PIN dq[8]
    DIRECTION INOUT ;
    USE SIGNAL ;
    PORT
      LAYER M4 ;
        RECT 17.016 22.896 17.208 22.920 ;
    END
  END dq[8]
  PIN dq[9]
    DIRECTION INOUT ;
    USE SIGNAL ;
    PORT
      LAYER M4 ;
        RECT 17.016 22.992 17.208 23.016 ;
    END
  END dq[9]
  PIN dq[10]
    DIRECTION INOUT ;
    USE SIGNAL ;
    PORT
      LAYER M4 ;
        RECT 17.016 23.088 17.208 23.112 ;
    END
  END dq[10]
  PIN dq[11]
    DIRECTION INOUT ;
    USE SIGNAL ;
    PORT
      LAYER M4 ;
        RECT 17.016 23.184 17.208 23.208 ;
    END
  END dq[11]
  PIN dq[12]
    DIRECTION INOUT ;
    USE SIGNAL ;
    PORT
      LAYER M4 ;
        RECT 17.016 23.280 17.208 23.304 ;
    END
  END dq[12]
  PIN dq[13]
    DIRECTION INOUT ;
    USE SIGNAL ;
    PORT
      LAYER M4 ;
        RECT 17.016 23.376 17.208 23.400 ;
    END
  END dq[13]
  PIN dq[14]
    DIRECTION INOUT ;
    USE SIGNAL ;
    PORT
      LAYER M4 ;
        RECT 17.016 23.472 17.208 23.496 ;
    END
  END dq[14]
  PIN dq[15]
    DIRECTION INOUT ;
    USE SIGNAL ;
    PORT
      LAYER M4 ;
        RECT 17.016 23.568 17.208 23.592 ;
    END
  END dq[15]
  PIN dq[16]
    DIRECTION INOUT ;
    USE SIGNAL ;
    PORT
      LAYER M4 ;
        RECT 17.016 23.664 17.208 23.688 ;
    END
  END dq[16]
  PIN dq[17]
    DIRECTION INOUT ;
    USE SIGNAL ;
    PORT
      LAYER M4 ;
        RECT 17.016 23.760 17.208 23.784 ;
    END
  END dq[17]
  PIN dq[18]
    DIRECTION INOUT ;
    USE SIGNAL ;
    PORT
      LAYER M4 ;
        RECT 17.016 23.856 17.208 23.880 ;
    END
  END dq[18]
  PIN dq[19]
    DIRECTION INOUT ;
    USE SIGNAL ;
    PORT
      LAYER M4 ;
        RECT 17.016 23.952 17.208 23.976 ;
    END
  END dq[19]
  PIN dq[20]
    DIRECTION INOUT ;
    USE SIGNAL ;
    PORT
      LAYER M4 ;
        RECT 17.016 24.048 17.208 24.072 ;
    END
  END dq[20]
  PIN dq[21]
    DIRECTION INOUT ;
    USE SIGNAL ;
    PORT
      LAYER M4 ;
        RECT 17.016 24.144 17.208 24.168 ;
    END
  END dq[21]
  PIN dq[22]
    DIRECTION INOUT ;
    USE SIGNAL ;
    PORT
      LAYER M4 ;
        RECT 17.016 24.240 17.208 24.264 ;
    END
  END dq[22]
  PIN dq[23]
    DIRECTION INOUT ;
    USE SIGNAL ;
    PORT
      LAYER M4 ;
        RECT 17.016 24.336 17.208 24.360 ;
    END
  END dq[23]
  PIN dq[24]
    DIRECTION INOUT ;
    USE SIGNAL ;
    PORT
      LAYER M4 ;
        RECT 17.016 24.432 17.208 24.456 ;
    END
  END dq[24]
  PIN dq[25]
    DIRECTION INOUT ;
    USE SIGNAL ;
    PORT
      LAYER M4 ;
        RECT 17.016 24.528 17.208 24.552 ;
    END
  END dq[25]
  PIN dq[26]
    DIRECTION INOUT ;
    USE SIGNAL ;
    PORT
      LAYER M4 ;
        RECT 17.016 24.624 17.208 24.648 ;
    END
  END dq[26]
  PIN dq[27]
    DIRECTION INOUT ;
    USE SIGNAL ;
    PORT
      LAYER M4 ;
        RECT 17.016 24.720 17.208 24.744 ;
    END
  END dq[27]
  PIN dq[28]
    DIRECTION INOUT ;
    USE SIGNAL ;
    PORT
      LAYER M4 ;
        RECT 17.016 24.816 17.208 24.840 ;
    END
  END dq[28]
  PIN dq[29]
    DIRECTION INOUT ;
    USE SIGNAL ;
    PORT
      LAYER M4 ;
        RECT 17.016 24.912 17.208 24.936 ;
    END
  END dq[29]
  PIN dq[30]
    DIRECTION INOUT ;
    USE SIGNAL ;
    PORT
      LAYER M4 ;
        RECT 17.016 25.008 17.208 25.032 ;
    END
  END dq[30]
  PIN dq[31]
    DIRECTION INOUT ;
    USE SIGNAL ;
    PORT
      LAYER M4 ;
        RECT 17.016 25.104 17.208 25.128 ;
    END
  END dq[31]
  PIN dq[32]
    DIRECTION INOUT ;
    USE SIGNAL ;
    PORT
      LAYER M4 ;
        RECT 17.016 25.200 17.208 25.224 ;
    END
  END dq[32]
  PIN dq[33]
    DIRECTION INOUT ;
    USE SIGNAL ;
    PORT
      LAYER M4 ;
        RECT 17.016 25.296 17.208 25.320 ;
    END
  END dq[33]
  PIN dq[34]
    DIRECTION INOUT ;
    USE SIGNAL ;
    PORT
      LAYER M4 ;
        RECT 17.016 25.392 17.208 25.416 ;
    END
  END dq[34]
  PIN dq[35]
    DIRECTION INOUT ;
    USE SIGNAL ;
    PORT
      LAYER M4 ;
        RECT 17.016 25.488 17.208 25.512 ;
    END
  END dq[35]
  PIN dq[36]
    DIRECTION INOUT ;
    USE SIGNAL ;
    PORT
      LAYER M4 ;
        RECT 17.016 25.584 17.208 25.608 ;
    END
  END dq[36]
  PIN dq[37]
    DIRECTION INOUT ;
    USE SIGNAL ;
    PORT
      LAYER M4 ;
        RECT 17.016 25.680 17.208 25.704 ;
    END
  END dq[37]
  PIN dq[38]
    DIRECTION INOUT ;
    USE SIGNAL ;
    PORT
      LAYER M4 ;
        RECT 17.016 25.776 17.208 25.800 ;
    END
  END dq[38]
  PIN dq[39]
    DIRECTION INOUT ;
    USE SIGNAL ;
    PORT
      LAYER M4 ;
        RECT 17.016 25.872 17.208 25.896 ;
    END
  END dq[39]
  PIN dq[40]
    DIRECTION INOUT ;
    USE SIGNAL ;
    PORT
      LAYER M4 ;
        RECT 17.016 25.968 17.208 25.992 ;
    END
  END dq[40]
  PIN dq[41]
    DIRECTION INOUT ;
    USE SIGNAL ;
    PORT
      LAYER M4 ;
        RECT 17.016 26.064 17.208 26.088 ;
    END
  END dq[41]
  PIN dq[42]
    DIRECTION INOUT ;
    USE SIGNAL ;
    PORT
      LAYER M4 ;
        RECT 17.016 26.160 17.208 26.184 ;
    END
  END dq[42]
  PIN dq[43]
    DIRECTION INOUT ;
    USE SIGNAL ;
    PORT
      LAYER M4 ;
        RECT 17.016 26.256 17.208 26.280 ;
    END
  END dq[43]
  PIN dq[44]
    DIRECTION INOUT ;
    USE SIGNAL ;
    PORT
      LAYER M4 ;
        RECT 17.016 26.352 17.208 26.376 ;
    END
  END dq[44]
  PIN dq[45]
    DIRECTION INOUT ;
    USE SIGNAL ;
    PORT
      LAYER M4 ;
        RECT 17.016 26.448 17.208 26.472 ;
    END
  END dq[45]
  PIN dq[46]
    DIRECTION INOUT ;
    USE SIGNAL ;
    PORT
      LAYER M4 ;
        RECT 17.016 26.544 17.208 26.568 ;
    END
  END dq[46]
  PIN dq[47]
    DIRECTION INOUT ;
    USE SIGNAL ;
    PORT
      LAYER M4 ;
        RECT 17.016 26.640 17.208 26.664 ;
    END
  END dq[47]
  PIN dq[48]
    DIRECTION INOUT ;
    USE SIGNAL ;
    PORT
      LAYER M4 ;
        RECT 17.016 26.736 17.208 26.760 ;
    END
  END dq[48]
  PIN dq[49]
    DIRECTION INOUT ;
    USE SIGNAL ;
    PORT
      LAYER M4 ;
        RECT 17.016 26.832 17.208 26.856 ;
    END
  END dq[49]
  PIN dq[50]
    DIRECTION INOUT ;
    USE SIGNAL ;
    PORT
      LAYER M4 ;
        RECT 17.016 26.928 17.208 26.952 ;
    END
  END dq[50]
  PIN dq[51]
    DIRECTION INOUT ;
    USE SIGNAL ;
    PORT
      LAYER M4 ;
        RECT 17.016 27.024 17.208 27.048 ;
    END
  END dq[51]
  PIN dq[52]
    DIRECTION INOUT ;
    USE SIGNAL ;
    PORT
      LAYER M4 ;
        RECT 17.016 27.120 17.208 27.144 ;
    END
  END dq[52]
  PIN dq[53]
    DIRECTION INOUT ;
    USE SIGNAL ;
    PORT
      LAYER M4 ;
        RECT 17.016 27.216 17.208 27.240 ;
    END
  END dq[53]
  PIN dq[54]
    DIRECTION INOUT ;
    USE SIGNAL ;
    PORT
      LAYER M4 ;
        RECT 17.016 27.312 17.208 27.336 ;
    END
  END dq[54]
  PIN dq[55]
    DIRECTION INOUT ;
    USE SIGNAL ;
    PORT
      LAYER M4 ;
        RECT 17.016 27.408 17.208 27.432 ;
    END
  END dq[55]
  PIN dq[56]
    DIRECTION INOUT ;
    USE SIGNAL ;
    PORT
      LAYER M4 ;
        RECT 17.016 27.504 17.208 27.528 ;
    END
  END dq[56]
  PIN dq[57]
    DIRECTION INOUT ;
    USE SIGNAL ;
    PORT
      LAYER M4 ;
        RECT 17.016 27.600 17.208 27.624 ;
    END
  END dq[57]
  PIN dq[58]
    DIRECTION INOUT ;
    USE SIGNAL ;
    PORT
      LAYER M4 ;
        RECT 17.016 27.696 17.208 27.720 ;
    END
  END dq[58]
  PIN dq[59]
    DIRECTION INOUT ;
    USE SIGNAL ;
    PORT
      LAYER M4 ;
        RECT 17.016 27.792 17.208 27.816 ;
    END
  END dq[59]
  PIN dq[60]
    DIRECTION INOUT ;
    USE SIGNAL ;
    PORT
      LAYER M4 ;
        RECT 17.016 27.888 17.208 27.912 ;
    END
  END dq[60]
  PIN dq[61]
    DIRECTION INOUT ;
    USE SIGNAL ;
    PORT
      LAYER M4 ;
        RECT 17.016 27.984 17.208 28.008 ;
    END
  END dq[61]
  PIN dq[62]
    DIRECTION INOUT ;
    USE SIGNAL ;
    PORT
      LAYER M4 ;
        RECT 17.016 28.080 17.208 28.104 ;
    END
  END dq[62]
  PIN dq[63]
    DIRECTION INOUT ;
    USE SIGNAL ;
    PORT
      LAYER M4 ;
        RECT 17.016 28.176 17.208 28.200 ;
    END
  END dq[63]
  PIN dq[64]
    DIRECTION INOUT ;
    USE SIGNAL ;
    PORT
      LAYER M4 ;
        RECT 17.016 28.272 17.208 28.296 ;
    END
  END dq[64]
  PIN dq[65]
    DIRECTION INOUT ;
    USE SIGNAL ;
    PORT
      LAYER M4 ;
        RECT 17.016 28.368 17.208 28.392 ;
    END
  END dq[65]
  PIN dq[66]
    DIRECTION INOUT ;
    USE SIGNAL ;
    PORT
      LAYER M4 ;
        RECT 17.016 28.464 17.208 28.488 ;
    END
  END dq[66]
  PIN dq[67]
    DIRECTION INOUT ;
    USE SIGNAL ;
    PORT
      LAYER M4 ;
        RECT 17.016 28.560 17.208 28.584 ;
    END
  END dq[67]
  PIN dq[68]
    DIRECTION INOUT ;
    USE SIGNAL ;
    PORT
      LAYER M4 ;
        RECT 17.016 28.656 17.208 28.680 ;
    END
  END dq[68]
  PIN dq[69]
    DIRECTION INOUT ;
    USE SIGNAL ;
    PORT
      LAYER M4 ;
        RECT 17.016 15.504 17.208 15.528 ;
    END
  END dq[69]
  PIN dq[70]
    DIRECTION INOUT ;
    USE SIGNAL ;
    PORT
      LAYER M4 ;
        RECT 17.016 15.600 17.208 15.624 ;
    END
  END dq[70]
  PIN dq[71]
    DIRECTION INOUT ;
    USE SIGNAL ;
    PORT
      LAYER M4 ;
        RECT 17.016 15.696 17.208 15.720 ;
    END
  END dq[71]
  PIN dq[72]
    DIRECTION INOUT ;
    USE SIGNAL ;
    PORT
      LAYER M4 ;
        RECT 17.016 15.792 17.208 15.816 ;
    END
  END dq[72]
  PIN dq[73]
    DIRECTION INOUT ;
    USE SIGNAL ;
    PORT
      LAYER M4 ;
        RECT 17.016 15.888 17.208 15.912 ;
    END
  END dq[73]
  PIN dq[74]
    DIRECTION INOUT ;
    USE SIGNAL ;
    PORT
      LAYER M4 ;
        RECT 17.016 15.984 17.208 16.008 ;
    END
  END dq[74]
  PIN dq[75]
    DIRECTION INOUT ;
    USE SIGNAL ;
    PORT
      LAYER M4 ;
        RECT 17.016 16.080 17.208 16.104 ;
    END
  END dq[75]
  PIN dq[76]
    DIRECTION INOUT ;
    USE SIGNAL ;
    PORT
      LAYER M4 ;
        RECT 17.016 16.176 17.208 16.200 ;
    END
  END dq[76]
  PIN dq[77]
    DIRECTION INOUT ;
    USE SIGNAL ;
    PORT
      LAYER M4 ;
        RECT 17.016 16.272 17.208 16.296 ;
    END
  END dq[77]
  PIN dq[78]
    DIRECTION INOUT ;
    USE SIGNAL ;
    PORT
      LAYER M4 ;
        RECT 17.016 16.368 17.208 16.392 ;
    END
  END dq[78]
  PIN dq[79]
    DIRECTION INOUT ;
    USE SIGNAL ;
    PORT
      LAYER M4 ;
        RECT 17.016 16.464 17.208 16.488 ;
    END
  END dq[79]
  PIN dq[80]
    DIRECTION INOUT ;
    USE SIGNAL ;
    PORT
      LAYER M4 ;
        RECT 17.016 16.560 17.208 16.584 ;
    END
  END dq[80]
  PIN dq[81]
    DIRECTION INOUT ;
    USE SIGNAL ;
    PORT
      LAYER M4 ;
        RECT 17.016 16.656 17.208 16.680 ;
    END
  END dq[81]
  PIN dq[82]
    DIRECTION INOUT ;
    USE SIGNAL ;
    PORT
      LAYER M4 ;
        RECT 17.016 16.752 17.208 16.776 ;
    END
  END dq[82]
  PIN dq[83]
    DIRECTION INOUT ;
    USE SIGNAL ;
    PORT
      LAYER M4 ;
        RECT 17.016 16.848 17.208 16.872 ;
    END
  END dq[83]
  PIN dq[84]
    DIRECTION INOUT ;
    USE SIGNAL ;
    PORT
      LAYER M4 ;
        RECT 17.016 16.944 17.208 16.968 ;
    END
  END dq[84]
  PIN dq[85]
    DIRECTION INOUT ;
    USE SIGNAL ;
    PORT
      LAYER M4 ;
        RECT 17.016 17.040 17.208 17.064 ;
    END
  END dq[85]
  PIN dq[86]
    DIRECTION INOUT ;
    USE SIGNAL ;
    PORT
      LAYER M4 ;
        RECT 17.016 17.136 17.208 17.160 ;
    END
  END dq[86]
  PIN dq[87]
    DIRECTION INOUT ;
    USE SIGNAL ;
    PORT
      LAYER M4 ;
        RECT 17.016 17.232 17.208 17.256 ;
    END
  END dq[87]
  PIN dq[88]
    DIRECTION INOUT ;
    USE SIGNAL ;
    PORT
      LAYER M4 ;
        RECT 17.016 17.328 17.208 17.352 ;
    END
  END dq[88]
  PIN dq[89]
    DIRECTION INOUT ;
    USE SIGNAL ;
    PORT
      LAYER M4 ;
        RECT 17.016 17.424 17.208 17.448 ;
    END
  END dq[89]
  PIN dq[90]
    DIRECTION INOUT ;
    USE SIGNAL ;
    PORT
      LAYER M4 ;
        RECT 17.016 17.520 17.208 17.544 ;
    END
  END dq[90]
  PIN dq[91]
    DIRECTION INOUT ;
    USE SIGNAL ;
    PORT
      LAYER M4 ;
        RECT 17.016 17.616 17.208 17.640 ;
    END
  END dq[91]
  PIN dq[92]
    DIRECTION INOUT ;
    USE SIGNAL ;
    PORT
      LAYER M4 ;
        RECT 17.016 17.712 17.208 17.736 ;
    END
  END dq[92]
  PIN dq[93]
    DIRECTION INOUT ;
    USE SIGNAL ;
    PORT
      LAYER M4 ;
        RECT 17.016 17.808 17.208 17.832 ;
    END
  END dq[93]
  PIN dq[94]
    DIRECTION INOUT ;
    USE SIGNAL ;
    PORT
      LAYER M4 ;
        RECT 17.016 17.904 17.208 17.928 ;
    END
  END dq[94]
  PIN dq[95]
    DIRECTION INOUT ;
    USE SIGNAL ;
    PORT
      LAYER M4 ;
        RECT 17.016 18.000 17.208 18.024 ;
    END
  END dq[95]
  PIN dq[96]
    DIRECTION INOUT ;
    USE SIGNAL ;
    PORT
      LAYER M4 ;
        RECT 17.016 18.096 17.208 18.120 ;
    END
  END dq[96]
  PIN dq[97]
    DIRECTION INOUT ;
    USE SIGNAL ;
    PORT
      LAYER M4 ;
        RECT 17.016 18.192 17.208 18.216 ;
    END
  END dq[97]
  PIN dq[98]
    DIRECTION INOUT ;
    USE SIGNAL ;
    PORT
      LAYER M4 ;
        RECT 17.016 18.288 17.208 18.312 ;
    END
  END dq[98]
  PIN dq[99]
    DIRECTION INOUT ;
    USE SIGNAL ;
    PORT
      LAYER M4 ;
        RECT 17.016 18.384 17.208 18.408 ;
    END
  END dq[99]
  PIN dq[100]
    DIRECTION INOUT ;
    USE SIGNAL ;
    PORT
      LAYER M4 ;
        RECT 17.016 18.480 17.208 18.504 ;
    END
  END dq[100]
  PIN dq[101]
    DIRECTION INOUT ;
    USE SIGNAL ;
    PORT
      LAYER M4 ;
        RECT 17.016 18.576 17.208 18.600 ;
    END
  END dq[101]
  PIN dq[102]
    DIRECTION INOUT ;
    USE SIGNAL ;
    PORT
      LAYER M4 ;
        RECT 17.016 18.672 17.208 18.696 ;
    END
  END dq[102]
  PIN dq[103]
    DIRECTION INOUT ;
    USE SIGNAL ;
    PORT
      LAYER M4 ;
        RECT 17.016 18.768 17.208 18.792 ;
    END
  END dq[103]
  PIN dq[104]
    DIRECTION INOUT ;
    USE SIGNAL ;
    PORT
      LAYER M4 ;
        RECT 17.016 18.864 17.208 18.888 ;
    END
  END dq[104]
  PIN dq[105]
    DIRECTION INOUT ;
    USE SIGNAL ;
    PORT
      LAYER M4 ;
        RECT 17.016 18.960 17.208 18.984 ;
    END
  END dq[105]
  PIN dq[106]
    DIRECTION INOUT ;
    USE SIGNAL ;
    PORT
      LAYER M4 ;
        RECT 17.016 19.056 17.208 19.080 ;
    END
  END dq[106]
  PIN dq[107]
    DIRECTION INOUT ;
    USE SIGNAL ;
    PORT
      LAYER M4 ;
        RECT 17.016 19.152 17.208 19.176 ;
    END
  END dq[107]
  PIN dq[108]
    DIRECTION INOUT ;
    USE SIGNAL ;
    PORT
      LAYER M4 ;
        RECT 17.016 19.248 17.208 19.272 ;
    END
  END dq[108]
  PIN dq[109]
    DIRECTION INOUT ;
    USE SIGNAL ;
    PORT
      LAYER M4 ;
        RECT 17.016 19.344 17.208 19.368 ;
    END
  END dq[109]
  PIN dq[110]
    DIRECTION INOUT ;
    USE SIGNAL ;
    PORT
      LAYER M4 ;
        RECT 17.016 19.440 17.208 19.464 ;
    END
  END dq[110]
  PIN dq[111]
    DIRECTION INOUT ;
    USE SIGNAL ;
    PORT
      LAYER M4 ;
        RECT 17.016 19.536 17.208 19.560 ;
    END
  END dq[111]
  PIN dq[112]
    DIRECTION INOUT ;
    USE SIGNAL ;
    PORT
      LAYER M4 ;
        RECT 17.016 19.632 17.208 19.656 ;
    END
  END dq[112]
  PIN dq[113]
    DIRECTION INOUT ;
    USE SIGNAL ;
    PORT
      LAYER M4 ;
        RECT 17.016 19.728 17.208 19.752 ;
    END
  END dq[113]
  PIN dq[114]
    DIRECTION INOUT ;
    USE SIGNAL ;
    PORT
      LAYER M4 ;
        RECT 17.016 19.824 17.208 19.848 ;
    END
  END dq[114]
  PIN dq[115]
    DIRECTION INOUT ;
    USE SIGNAL ;
    PORT
      LAYER M4 ;
        RECT 17.016 19.920 17.208 19.944 ;
    END
  END dq[115]
  PIN dq[116]
    DIRECTION INOUT ;
    USE SIGNAL ;
    PORT
      LAYER M4 ;
        RECT 17.016 20.016 17.208 20.040 ;
    END
  END dq[116]
  PIN dq[117]
    DIRECTION INOUT ;
    USE SIGNAL ;
    PORT
      LAYER M4 ;
        RECT 17.016 20.112 17.208 20.136 ;
    END
  END dq[117]
  PIN dq[118]
    DIRECTION INOUT ;
    USE SIGNAL ;
    PORT
      LAYER M4 ;
        RECT 17.016 20.208 17.208 20.232 ;
    END
  END dq[118]
  PIN dq[119]
    DIRECTION INOUT ;
    USE SIGNAL ;
    PORT
      LAYER M4 ;
        RECT 17.016 20.304 17.208 20.328 ;
    END
  END dq[119]
  PIN dq[120]
    DIRECTION INOUT ;
    USE SIGNAL ;
    PORT
      LAYER M4 ;
        RECT 17.016 20.400 17.208 20.424 ;
    END
  END dq[120]
  PIN dq[121]
    DIRECTION INOUT ;
    USE SIGNAL ;
    PORT
      LAYER M4 ;
        RECT 17.016 20.496 17.208 20.520 ;
    END
  END dq[121]
  PIN dq[122]
    DIRECTION INOUT ;
    USE SIGNAL ;
    PORT
      LAYER M4 ;
        RECT 17.016 20.592 17.208 20.616 ;
    END
  END dq[122]
  PIN dq[123]
    DIRECTION INOUT ;
    USE SIGNAL ;
    PORT
      LAYER M4 ;
        RECT 17.016 20.688 17.208 20.712 ;
    END
  END dq[123]
  PIN dq[124]
    DIRECTION INOUT ;
    USE SIGNAL ;
    PORT
      LAYER M4 ;
        RECT 17.016 20.784 17.208 20.808 ;
    END
  END dq[124]
  PIN dq[125]
    DIRECTION INOUT ;
    USE SIGNAL ;
    PORT
      LAYER M4 ;
        RECT 17.016 20.880 17.208 20.904 ;
    END
  END dq[125]
  PIN dq[126]
    DIRECTION INOUT ;
    USE SIGNAL ;
    PORT
      LAYER M4 ;
        RECT 17.016 20.976 17.208 21.000 ;
    END
  END dq[126]
  PIN dq[127]
    DIRECTION INOUT ;
    USE SIGNAL ;
    PORT
      LAYER M4 ;
        RECT 17.016 21.072 17.208 21.096 ;
    END
  END dq[127]
  PIN dq[128]
    DIRECTION INOUT ;
    USE SIGNAL ;
    PORT
      LAYER M4 ;
        RECT 17.016 21.168 17.208 21.192 ;
    END
  END dq[128]
  PIN dq[129]
    DIRECTION INOUT ;
    USE SIGNAL ;
    PORT
      LAYER M4 ;
        RECT 17.016 21.264 17.208 21.288 ;
    END
  END dq[129]
  PIN dq[130]
    DIRECTION INOUT ;
    USE SIGNAL ;
    PORT
      LAYER M4 ;
        RECT 17.016 21.360 17.208 21.384 ;
    END
  END dq[130]
  PIN dq[131]
    DIRECTION INOUT ;
    USE SIGNAL ;
    PORT
      LAYER M4 ;
        RECT 17.016 21.456 17.208 21.480 ;
    END
  END dq[131]
  PIN dq[132]
    DIRECTION INOUT ;
    USE SIGNAL ;
    PORT
      LAYER M4 ;
        RECT 17.016 21.552 17.208 21.576 ;
    END
  END dq[132]
  PIN dq[133]
    DIRECTION INOUT ;
    USE SIGNAL ;
    PORT
      LAYER M4 ;
        RECT 17.016 21.648 17.208 21.672 ;
    END
  END dq[133]
  PIN dq[134]
    DIRECTION INOUT ;
    USE SIGNAL ;
    PORT
      LAYER M4 ;
        RECT 17.016 21.744 17.208 21.768 ;
    END
  END dq[134]
  PIN dq[135]
    DIRECTION INOUT ;
    USE SIGNAL ;
    PORT
      LAYER M4 ;
        RECT 17.016 21.840 17.208 21.864 ;
    END
  END dq[135]
  PIN dq[136]
    DIRECTION INOUT ;
    USE SIGNAL ;
    PORT
      LAYER M4 ;
        RECT 17.016 21.936 17.208 21.960 ;
    END
  END dq[136]
  PIN dq[137]
    DIRECTION INOUT ;
    USE SIGNAL ;
    PORT
      LAYER M4 ;
        RECT 17.016 22.032 17.208 22.056 ;
    END
  END dq[137]
  PIN dq[138]
    DIRECTION INOUT ;
    USE SIGNAL ;
    PORT
      LAYER M4 ;
        RECT 17.016 8.880 17.208 8.904 ;
    END
  END dq[138]
  PIN dq[139]
    DIRECTION INOUT ;
    USE SIGNAL ;
    PORT
      LAYER M4 ;
        RECT 17.016 8.976 17.208 9.000 ;
    END
  END dq[139]
  PIN dq[140]
    DIRECTION INOUT ;
    USE SIGNAL ;
    PORT
      LAYER M4 ;
        RECT 17.016 9.072 17.208 9.096 ;
    END
  END dq[140]
  PIN dq[141]
    DIRECTION INOUT ;
    USE SIGNAL ;
    PORT
      LAYER M4 ;
        RECT 17.016 9.168 17.208 9.192 ;
    END
  END dq[141]
  PIN dq[142]
    DIRECTION INOUT ;
    USE SIGNAL ;
    PORT
      LAYER M4 ;
        RECT 17.016 9.264 17.208 9.288 ;
    END
  END dq[142]
  PIN dq[143]
    DIRECTION INOUT ;
    USE SIGNAL ;
    PORT
      LAYER M4 ;
        RECT 17.016 9.360 17.208 9.384 ;
    END
  END dq[143]
  PIN dq[144]
    DIRECTION INOUT ;
    USE SIGNAL ;
    PORT
      LAYER M4 ;
        RECT 17.016 9.456 17.208 9.480 ;
    END
  END dq[144]
  PIN dq[145]
    DIRECTION INOUT ;
    USE SIGNAL ;
    PORT
      LAYER M4 ;
        RECT 17.016 9.552 17.208 9.576 ;
    END
  END dq[145]
  PIN dq[146]
    DIRECTION INOUT ;
    USE SIGNAL ;
    PORT
      LAYER M4 ;
        RECT 17.016 9.648 17.208 9.672 ;
    END
  END dq[146]
  PIN dq[147]
    DIRECTION INOUT ;
    USE SIGNAL ;
    PORT
      LAYER M4 ;
        RECT 17.016 9.744 17.208 9.768 ;
    END
  END dq[147]
  PIN dq[148]
    DIRECTION INOUT ;
    USE SIGNAL ;
    PORT
      LAYER M4 ;
        RECT 17.016 9.840 17.208 9.864 ;
    END
  END dq[148]
  PIN dq[149]
    DIRECTION INOUT ;
    USE SIGNAL ;
    PORT
      LAYER M4 ;
        RECT 17.016 9.936 17.208 9.960 ;
    END
  END dq[149]
  PIN dq[150]
    DIRECTION INOUT ;
    USE SIGNAL ;
    PORT
      LAYER M4 ;
        RECT 17.016 10.032 17.208 10.056 ;
    END
  END dq[150]
  PIN dq[151]
    DIRECTION INOUT ;
    USE SIGNAL ;
    PORT
      LAYER M4 ;
        RECT 17.016 10.128 17.208 10.152 ;
    END
  END dq[151]
  PIN dq[152]
    DIRECTION INOUT ;
    USE SIGNAL ;
    PORT
      LAYER M4 ;
        RECT 17.016 10.224 17.208 10.248 ;
    END
  END dq[152]
  PIN dq[153]
    DIRECTION INOUT ;
    USE SIGNAL ;
    PORT
      LAYER M4 ;
        RECT 17.016 10.320 17.208 10.344 ;
    END
  END dq[153]
  PIN dq[154]
    DIRECTION INOUT ;
    USE SIGNAL ;
    PORT
      LAYER M4 ;
        RECT 17.016 10.416 17.208 10.440 ;
    END
  END dq[154]
  PIN dq[155]
    DIRECTION INOUT ;
    USE SIGNAL ;
    PORT
      LAYER M4 ;
        RECT 17.016 10.512 17.208 10.536 ;
    END
  END dq[155]
  PIN dq[156]
    DIRECTION INOUT ;
    USE SIGNAL ;
    PORT
      LAYER M4 ;
        RECT 17.016 10.608 17.208 10.632 ;
    END
  END dq[156]
  PIN dq[157]
    DIRECTION INOUT ;
    USE SIGNAL ;
    PORT
      LAYER M4 ;
        RECT 17.016 10.704 17.208 10.728 ;
    END
  END dq[157]
  PIN dq[158]
    DIRECTION INOUT ;
    USE SIGNAL ;
    PORT
      LAYER M4 ;
        RECT 17.016 10.800 17.208 10.824 ;
    END
  END dq[158]
  PIN dq[159]
    DIRECTION INOUT ;
    USE SIGNAL ;
    PORT
      LAYER M4 ;
        RECT 17.016 10.896 17.208 10.920 ;
    END
  END dq[159]
  PIN dq[160]
    DIRECTION INOUT ;
    USE SIGNAL ;
    PORT
      LAYER M4 ;
        RECT 17.016 10.992 17.208 11.016 ;
    END
  END dq[160]
  PIN dq[161]
    DIRECTION INOUT ;
    USE SIGNAL ;
    PORT
      LAYER M4 ;
        RECT 17.016 11.088 17.208 11.112 ;
    END
  END dq[161]
  PIN dq[162]
    DIRECTION INOUT ;
    USE SIGNAL ;
    PORT
      LAYER M4 ;
        RECT 17.016 11.184 17.208 11.208 ;
    END
  END dq[162]
  PIN dq[163]
    DIRECTION INOUT ;
    USE SIGNAL ;
    PORT
      LAYER M4 ;
        RECT 17.016 11.280 17.208 11.304 ;
    END
  END dq[163]
  PIN dq[164]
    DIRECTION INOUT ;
    USE SIGNAL ;
    PORT
      LAYER M4 ;
        RECT 17.016 11.376 17.208 11.400 ;
    END
  END dq[164]
  PIN dq[165]
    DIRECTION INOUT ;
    USE SIGNAL ;
    PORT
      LAYER M4 ;
        RECT 17.016 11.472 17.208 11.496 ;
    END
  END dq[165]
  PIN dq[166]
    DIRECTION INOUT ;
    USE SIGNAL ;
    PORT
      LAYER M4 ;
        RECT 17.016 11.568 17.208 11.592 ;
    END
  END dq[166]
  PIN dq[167]
    DIRECTION INOUT ;
    USE SIGNAL ;
    PORT
      LAYER M4 ;
        RECT 17.016 11.664 17.208 11.688 ;
    END
  END dq[167]
  PIN dq[168]
    DIRECTION INOUT ;
    USE SIGNAL ;
    PORT
      LAYER M4 ;
        RECT 17.016 11.760 17.208 11.784 ;
    END
  END dq[168]
  PIN dq[169]
    DIRECTION INOUT ;
    USE SIGNAL ;
    PORT
      LAYER M4 ;
        RECT 17.016 11.856 17.208 11.880 ;
    END
  END dq[169]
  PIN dq[170]
    DIRECTION INOUT ;
    USE SIGNAL ;
    PORT
      LAYER M4 ;
        RECT 17.016 11.952 17.208 11.976 ;
    END
  END dq[170]
  PIN dq[171]
    DIRECTION INOUT ;
    USE SIGNAL ;
    PORT
      LAYER M4 ;
        RECT 17.016 12.048 17.208 12.072 ;
    END
  END dq[171]
  PIN dq[172]
    DIRECTION INOUT ;
    USE SIGNAL ;
    PORT
      LAYER M4 ;
        RECT 17.016 12.144 17.208 12.168 ;
    END
  END dq[172]
  PIN dq[173]
    DIRECTION INOUT ;
    USE SIGNAL ;
    PORT
      LAYER M4 ;
        RECT 17.016 12.240 17.208 12.264 ;
    END
  END dq[173]
  PIN dq[174]
    DIRECTION INOUT ;
    USE SIGNAL ;
    PORT
      LAYER M4 ;
        RECT 17.016 12.336 17.208 12.360 ;
    END
  END dq[174]
  PIN dq[175]
    DIRECTION INOUT ;
    USE SIGNAL ;
    PORT
      LAYER M4 ;
        RECT 17.016 12.432 17.208 12.456 ;
    END
  END dq[175]
  PIN dq[176]
    DIRECTION INOUT ;
    USE SIGNAL ;
    PORT
      LAYER M4 ;
        RECT 17.016 12.528 17.208 12.552 ;
    END
  END dq[176]
  PIN dq[177]
    DIRECTION INOUT ;
    USE SIGNAL ;
    PORT
      LAYER M4 ;
        RECT 17.016 12.624 17.208 12.648 ;
    END
  END dq[177]
  PIN dq[178]
    DIRECTION INOUT ;
    USE SIGNAL ;
    PORT
      LAYER M4 ;
        RECT 17.016 12.720 17.208 12.744 ;
    END
  END dq[178]
  PIN dq[179]
    DIRECTION INOUT ;
    USE SIGNAL ;
    PORT
      LAYER M4 ;
        RECT 17.016 12.816 17.208 12.840 ;
    END
  END dq[179]
  PIN dq[180]
    DIRECTION INOUT ;
    USE SIGNAL ;
    PORT
      LAYER M4 ;
        RECT 17.016 12.912 17.208 12.936 ;
    END
  END dq[180]
  PIN dq[181]
    DIRECTION INOUT ;
    USE SIGNAL ;
    PORT
      LAYER M4 ;
        RECT 17.016 13.008 17.208 13.032 ;
    END
  END dq[181]
  PIN dq[182]
    DIRECTION INOUT ;
    USE SIGNAL ;
    PORT
      LAYER M4 ;
        RECT 17.016 13.104 17.208 13.128 ;
    END
  END dq[182]
  PIN dq[183]
    DIRECTION INOUT ;
    USE SIGNAL ;
    PORT
      LAYER M4 ;
        RECT 17.016 13.200 17.208 13.224 ;
    END
  END dq[183]
  PIN dq[184]
    DIRECTION INOUT ;
    USE SIGNAL ;
    PORT
      LAYER M4 ;
        RECT 17.016 13.296 17.208 13.320 ;
    END
  END dq[184]
  PIN dq[185]
    DIRECTION INOUT ;
    USE SIGNAL ;
    PORT
      LAYER M4 ;
        RECT 17.016 13.392 17.208 13.416 ;
    END
  END dq[185]
  PIN dq[186]
    DIRECTION INOUT ;
    USE SIGNAL ;
    PORT
      LAYER M4 ;
        RECT 17.016 13.488 17.208 13.512 ;
    END
  END dq[186]
  PIN dq[187]
    DIRECTION INOUT ;
    USE SIGNAL ;
    PORT
      LAYER M4 ;
        RECT 17.016 13.584 17.208 13.608 ;
    END
  END dq[187]
  PIN dq[188]
    DIRECTION INOUT ;
    USE SIGNAL ;
    PORT
      LAYER M4 ;
        RECT 17.016 13.680 17.208 13.704 ;
    END
  END dq[188]
  PIN dq[189]
    DIRECTION INOUT ;
    USE SIGNAL ;
    PORT
      LAYER M4 ;
        RECT 17.016 13.776 17.208 13.800 ;
    END
  END dq[189]
  PIN dq[190]
    DIRECTION INOUT ;
    USE SIGNAL ;
    PORT
      LAYER M4 ;
        RECT 17.016 13.872 17.208 13.896 ;
    END
  END dq[190]
  PIN dq[191]
    DIRECTION INOUT ;
    USE SIGNAL ;
    PORT
      LAYER M4 ;
        RECT 17.016 13.968 17.208 13.992 ;
    END
  END dq[191]
  PIN dq[192]
    DIRECTION INOUT ;
    USE SIGNAL ;
    PORT
      LAYER M4 ;
        RECT 17.016 14.064 17.208 14.088 ;
    END
  END dq[192]
  PIN dq[193]
    DIRECTION INOUT ;
    USE SIGNAL ;
    PORT
      LAYER M4 ;
        RECT 17.016 14.160 17.208 14.184 ;
    END
  END dq[193]
  PIN dq[194]
    DIRECTION INOUT ;
    USE SIGNAL ;
    PORT
      LAYER M4 ;
        RECT 17.016 14.256 17.208 14.280 ;
    END
  END dq[194]
  PIN dq[195]
    DIRECTION INOUT ;
    USE SIGNAL ;
    PORT
      LAYER M4 ;
        RECT 17.016 14.352 17.208 14.376 ;
    END
  END dq[195]
  PIN dq[196]
    DIRECTION INOUT ;
    USE SIGNAL ;
    PORT
      LAYER M4 ;
        RECT 17.016 14.448 17.208 14.472 ;
    END
  END dq[196]
  PIN dq[197]
    DIRECTION INOUT ;
    USE SIGNAL ;
    PORT
      LAYER M4 ;
        RECT 17.016 14.544 17.208 14.568 ;
    END
  END dq[197]
  PIN dq[198]
    DIRECTION INOUT ;
    USE SIGNAL ;
    PORT
      LAYER M4 ;
        RECT 17.016 14.640 17.208 14.664 ;
    END
  END dq[198]
  PIN dq[199]
    DIRECTION INOUT ;
    USE SIGNAL ;
    PORT
      LAYER M4 ;
        RECT 17.016 14.736 17.208 14.760 ;
    END
  END dq[199]
  PIN dq[200]
    DIRECTION INOUT ;
    USE SIGNAL ;
    PORT
      LAYER M4 ;
        RECT 17.016 14.832 17.208 14.856 ;
    END
  END dq[200]
  PIN dq[201]
    DIRECTION INOUT ;
    USE SIGNAL ;
    PORT
      LAYER M4 ;
        RECT 17.016 14.928 17.208 14.952 ;
    END
  END dq[201]
  PIN dq[202]
    DIRECTION INOUT ;
    USE SIGNAL ;
    PORT
      LAYER M4 ;
        RECT 17.016 15.024 17.208 15.048 ;
    END
  END dq[202]
  PIN dq[203]
    DIRECTION INOUT ;
    USE SIGNAL ;
    PORT
      LAYER M4 ;
        RECT 17.016 15.120 17.208 15.144 ;
    END
  END dq[203]
  PIN dq[204]
    DIRECTION INOUT ;
    USE SIGNAL ;
    PORT
      LAYER M4 ;
        RECT 17.016 15.216 17.208 15.240 ;
    END
  END dq[204]
  PIN dq[205]
    DIRECTION INOUT ;
    USE SIGNAL ;
    PORT
      LAYER M4 ;
        RECT 17.016 15.312 17.208 15.336 ;
    END
  END dq[205]
  PIN dq[206]
    DIRECTION INOUT ;
    USE SIGNAL ;
    PORT
      LAYER M4 ;
        RECT 17.016 15.408 17.208 15.432 ;
    END
  END dq[206]
  PIN dq[207]
    DIRECTION INOUT ;
    USE SIGNAL ;
    PORT
      LAYER M4 ;
        RECT 17.016 2.256 17.208 2.280 ;
    END
  END dq[207]
  PIN dq[208]
    DIRECTION INOUT ;
    USE SIGNAL ;
    PORT
      LAYER M4 ;
        RECT 17.016 2.352 17.208 2.376 ;
    END
  END dq[208]
  PIN dq[209]
    DIRECTION INOUT ;
    USE SIGNAL ;
    PORT
      LAYER M4 ;
        RECT 17.016 2.448 17.208 2.472 ;
    END
  END dq[209]
  PIN dq[210]
    DIRECTION INOUT ;
    USE SIGNAL ;
    PORT
      LAYER M4 ;
        RECT 17.016 2.544 17.208 2.568 ;
    END
  END dq[210]
  PIN dq[211]
    DIRECTION INOUT ;
    USE SIGNAL ;
    PORT
      LAYER M4 ;
        RECT 17.016 2.640 17.208 2.664 ;
    END
  END dq[211]
  PIN dq[212]
    DIRECTION INOUT ;
    USE SIGNAL ;
    PORT
      LAYER M4 ;
        RECT 17.016 2.736 17.208 2.760 ;
    END
  END dq[212]
  PIN dq[213]
    DIRECTION INOUT ;
    USE SIGNAL ;
    PORT
      LAYER M4 ;
        RECT 17.016 2.832 17.208 2.856 ;
    END
  END dq[213]
  PIN dq[214]
    DIRECTION INOUT ;
    USE SIGNAL ;
    PORT
      LAYER M4 ;
        RECT 17.016 2.928 17.208 2.952 ;
    END
  END dq[214]
  PIN dq[215]
    DIRECTION INOUT ;
    USE SIGNAL ;
    PORT
      LAYER M4 ;
        RECT 17.016 3.024 17.208 3.048 ;
    END
  END dq[215]
  PIN dq[216]
    DIRECTION INOUT ;
    USE SIGNAL ;
    PORT
      LAYER M4 ;
        RECT 17.016 3.120 17.208 3.144 ;
    END
  END dq[216]
  PIN dq[217]
    DIRECTION INOUT ;
    USE SIGNAL ;
    PORT
      LAYER M4 ;
        RECT 17.016 3.216 17.208 3.240 ;
    END
  END dq[217]
  PIN dq[218]
    DIRECTION INOUT ;
    USE SIGNAL ;
    PORT
      LAYER M4 ;
        RECT 17.016 3.312 17.208 3.336 ;
    END
  END dq[218]
  PIN dq[219]
    DIRECTION INOUT ;
    USE SIGNAL ;
    PORT
      LAYER M4 ;
        RECT 17.016 3.408 17.208 3.432 ;
    END
  END dq[219]
  PIN dq[220]
    DIRECTION INOUT ;
    USE SIGNAL ;
    PORT
      LAYER M4 ;
        RECT 17.016 3.504 17.208 3.528 ;
    END
  END dq[220]
  PIN dq[221]
    DIRECTION INOUT ;
    USE SIGNAL ;
    PORT
      LAYER M4 ;
        RECT 17.016 3.600 17.208 3.624 ;
    END
  END dq[221]
  PIN dq[222]
    DIRECTION INOUT ;
    USE SIGNAL ;
    PORT
      LAYER M4 ;
        RECT 17.016 3.696 17.208 3.720 ;
    END
  END dq[222]
  PIN dq[223]
    DIRECTION INOUT ;
    USE SIGNAL ;
    PORT
      LAYER M4 ;
        RECT 17.016 3.792 17.208 3.816 ;
    END
  END dq[223]
  PIN dq[224]
    DIRECTION INOUT ;
    USE SIGNAL ;
    PORT
      LAYER M4 ;
        RECT 17.016 3.888 17.208 3.912 ;
    END
  END dq[224]
  PIN dq[225]
    DIRECTION INOUT ;
    USE SIGNAL ;
    PORT
      LAYER M4 ;
        RECT 17.016 3.984 17.208 4.008 ;
    END
  END dq[225]
  PIN dq[226]
    DIRECTION INOUT ;
    USE SIGNAL ;
    PORT
      LAYER M4 ;
        RECT 17.016 4.080 17.208 4.104 ;
    END
  END dq[226]
  PIN dq[227]
    DIRECTION INOUT ;
    USE SIGNAL ;
    PORT
      LAYER M4 ;
        RECT 17.016 4.176 17.208 4.200 ;
    END
  END dq[227]
  PIN dq[228]
    DIRECTION INOUT ;
    USE SIGNAL ;
    PORT
      LAYER M4 ;
        RECT 17.016 4.272 17.208 4.296 ;
    END
  END dq[228]
  PIN dq[229]
    DIRECTION INOUT ;
    USE SIGNAL ;
    PORT
      LAYER M4 ;
        RECT 17.016 4.368 17.208 4.392 ;
    END
  END dq[229]
  PIN dq[230]
    DIRECTION INOUT ;
    USE SIGNAL ;
    PORT
      LAYER M4 ;
        RECT 17.016 4.464 17.208 4.488 ;
    END
  END dq[230]
  PIN dq[231]
    DIRECTION INOUT ;
    USE SIGNAL ;
    PORT
      LAYER M4 ;
        RECT 17.016 4.560 17.208 4.584 ;
    END
  END dq[231]
  PIN dq[232]
    DIRECTION INOUT ;
    USE SIGNAL ;
    PORT
      LAYER M4 ;
        RECT 17.016 4.656 17.208 4.680 ;
    END
  END dq[232]
  PIN dq[233]
    DIRECTION INOUT ;
    USE SIGNAL ;
    PORT
      LAYER M4 ;
        RECT 17.016 4.752 17.208 4.776 ;
    END
  END dq[233]
  PIN dq[234]
    DIRECTION INOUT ;
    USE SIGNAL ;
    PORT
      LAYER M4 ;
        RECT 17.016 4.848 17.208 4.872 ;
    END
  END dq[234]
  PIN dq[235]
    DIRECTION INOUT ;
    USE SIGNAL ;
    PORT
      LAYER M4 ;
        RECT 17.016 4.944 17.208 4.968 ;
    END
  END dq[235]
  PIN dq[236]
    DIRECTION INOUT ;
    USE SIGNAL ;
    PORT
      LAYER M4 ;
        RECT 17.016 5.040 17.208 5.064 ;
    END
  END dq[236]
  PIN dq[237]
    DIRECTION INOUT ;
    USE SIGNAL ;
    PORT
      LAYER M4 ;
        RECT 17.016 5.136 17.208 5.160 ;
    END
  END dq[237]
  PIN dq[238]
    DIRECTION INOUT ;
    USE SIGNAL ;
    PORT
      LAYER M4 ;
        RECT 17.016 5.232 17.208 5.256 ;
    END
  END dq[238]
  PIN dq[239]
    DIRECTION INOUT ;
    USE SIGNAL ;
    PORT
      LAYER M4 ;
        RECT 17.016 5.328 17.208 5.352 ;
    END
  END dq[239]
  PIN dq[240]
    DIRECTION INOUT ;
    USE SIGNAL ;
    PORT
      LAYER M4 ;
        RECT 17.016 5.424 17.208 5.448 ;
    END
  END dq[240]
  PIN dq[241]
    DIRECTION INOUT ;
    USE SIGNAL ;
    PORT
      LAYER M4 ;
        RECT 17.016 5.520 17.208 5.544 ;
    END
  END dq[241]
  PIN dq[242]
    DIRECTION INOUT ;
    USE SIGNAL ;
    PORT
      LAYER M4 ;
        RECT 17.016 5.616 17.208 5.640 ;
    END
  END dq[242]
  PIN dq[243]
    DIRECTION INOUT ;
    USE SIGNAL ;
    PORT
      LAYER M4 ;
        RECT 17.016 5.712 17.208 5.736 ;
    END
  END dq[243]
  PIN dq[244]
    DIRECTION INOUT ;
    USE SIGNAL ;
    PORT
      LAYER M4 ;
        RECT 17.016 5.808 17.208 5.832 ;
    END
  END dq[244]
  PIN dq[245]
    DIRECTION INOUT ;
    USE SIGNAL ;
    PORT
      LAYER M4 ;
        RECT 17.016 5.904 17.208 5.928 ;
    END
  END dq[245]
  PIN dq[246]
    DIRECTION INOUT ;
    USE SIGNAL ;
    PORT
      LAYER M4 ;
        RECT 17.016 6.000 17.208 6.024 ;
    END
  END dq[246]
  PIN dq[247]
    DIRECTION INOUT ;
    USE SIGNAL ;
    PORT
      LAYER M4 ;
        RECT 17.016 6.096 17.208 6.120 ;
    END
  END dq[247]
  PIN dq[248]
    DIRECTION INOUT ;
    USE SIGNAL ;
    PORT
      LAYER M4 ;
        RECT 17.016 6.192 17.208 6.216 ;
    END
  END dq[248]
  PIN dq[249]
    DIRECTION INOUT ;
    USE SIGNAL ;
    PORT
      LAYER M4 ;
        RECT 17.016 6.288 17.208 6.312 ;
    END
  END dq[249]
  PIN dq[250]
    DIRECTION INOUT ;
    USE SIGNAL ;
    PORT
      LAYER M4 ;
        RECT 17.016 6.384 17.208 6.408 ;
    END
  END dq[250]
  PIN dq[251]
    DIRECTION INOUT ;
    USE SIGNAL ;
    PORT
      LAYER M4 ;
        RECT 17.016 6.480 17.208 6.504 ;
    END
  END dq[251]
  PIN dq[252]
    DIRECTION INOUT ;
    USE SIGNAL ;
    PORT
      LAYER M4 ;
        RECT 17.016 6.576 17.208 6.600 ;
    END
  END dq[252]
  PIN dq[253]
    DIRECTION INOUT ;
    USE SIGNAL ;
    PORT
      LAYER M4 ;
        RECT 17.016 6.672 17.208 6.696 ;
    END
  END dq[253]
  PIN dq[254]
    DIRECTION INOUT ;
    USE SIGNAL ;
    PORT
      LAYER M4 ;
        RECT 17.016 6.768 17.208 6.792 ;
    END
  END dq[254]
  PIN dq[255]
    DIRECTION INOUT ;
    USE SIGNAL ;
    PORT
      LAYER M4 ;
        RECT 17.016 6.864 17.208 6.888 ;
    END
  END dq[255]
  PIN dq[256]
    DIRECTION INOUT ;
    USE SIGNAL ;
    PORT
      LAYER M4 ;
        RECT 17.016 6.960 17.208 6.984 ;
    END
  END dq[256]
  PIN dq[257]
    DIRECTION INOUT ;
    USE SIGNAL ;
    PORT
      LAYER M4 ;
        RECT 17.016 7.056 17.208 7.080 ;
    END
  END dq[257]
  PIN dq[258]
    DIRECTION INOUT ;
    USE SIGNAL ;
    PORT
      LAYER M4 ;
        RECT 17.016 7.152 17.208 7.176 ;
    END
  END dq[258]
  PIN dq[259]
    DIRECTION INOUT ;
    USE SIGNAL ;
    PORT
      LAYER M4 ;
        RECT 17.016 7.248 17.208 7.272 ;
    END
  END dq[259]
  PIN dq[260]
    DIRECTION INOUT ;
    USE SIGNAL ;
    PORT
      LAYER M4 ;
        RECT 17.016 7.344 17.208 7.368 ;
    END
  END dq[260]
  PIN dq[261]
    DIRECTION INOUT ;
    USE SIGNAL ;
    PORT
      LAYER M4 ;
        RECT 17.016 7.440 17.208 7.464 ;
    END
  END dq[261]
  PIN dq[262]
    DIRECTION INOUT ;
    USE SIGNAL ;
    PORT
      LAYER M4 ;
        RECT 17.016 7.536 17.208 7.560 ;
    END
  END dq[262]
  PIN dq[263]
    DIRECTION INOUT ;
    USE SIGNAL ;
    PORT
      LAYER M4 ;
        RECT 17.016 7.632 17.208 7.656 ;
    END
  END dq[263]
  PIN dq[264]
    DIRECTION INOUT ;
    USE SIGNAL ;
    PORT
      LAYER M4 ;
        RECT 17.016 7.728 17.208 7.752 ;
    END
  END dq[264]
  PIN dq[265]
    DIRECTION INOUT ;
    USE SIGNAL ;
    PORT
      LAYER M4 ;
        RECT 17.016 7.824 17.208 7.848 ;
    END
  END dq[265]
  PIN dq[266]
    DIRECTION INOUT ;
    USE SIGNAL ;
    PORT
      LAYER M4 ;
        RECT 17.016 7.920 17.208 7.944 ;
    END
  END dq[266]
  PIN dq[267]
    DIRECTION INOUT ;
    USE SIGNAL ;
    PORT
      LAYER M4 ;
        RECT 17.016 8.016 17.208 8.040 ;
    END
  END dq[267]
  PIN dq[268]
    DIRECTION INOUT ;
    USE SIGNAL ;
    PORT
      LAYER M4 ;
        RECT 17.016 8.112 17.208 8.136 ;
    END
  END dq[268]
  PIN dq[269]
    DIRECTION INOUT ;
    USE SIGNAL ;
    PORT
      LAYER M4 ;
        RECT 17.016 8.208 17.208 8.232 ;
    END
  END dq[269]
  PIN dq[270]
    DIRECTION INOUT ;
    USE SIGNAL ;
    PORT
      LAYER M4 ;
        RECT 17.016 8.304 17.208 8.328 ;
    END
  END dq[270]
  PIN dq[271]
    DIRECTION INOUT ;
    USE SIGNAL ;
    PORT
      LAYER M4 ;
        RECT 17.016 8.400 17.208 8.424 ;
    END
  END dq[271]
  PIN dq[272]
    DIRECTION INOUT ;
    USE SIGNAL ;
    PORT
      LAYER M4 ;
        RECT 17.016 8.496 17.208 8.520 ;
    END
  END dq[272]
  PIN dq[273]
    DIRECTION INOUT ;
    USE SIGNAL ;
    PORT
      LAYER M4 ;
        RECT 17.016 8.592 17.208 8.616 ;
    END
  END dq[273]
  PIN dq[274]
    DIRECTION INOUT ;
    USE SIGNAL ;
    PORT
      LAYER M4 ;
        RECT 17.016 8.688 17.208 8.712 ;
    END
  END dq[274]
  PIN dq[275]
    DIRECTION INOUT ;
    USE SIGNAL ;
    PORT
      LAYER M4 ;
        RECT 17.016 8.784 17.208 8.808 ;
    END
  END dq[275]
  PIN ck[0]
    DIRECTION INOUT ;
    USE SIGNAL ;
    PORT
      LAYER M5 ;
        RECT 8.592 30.000 8.616 30.192 ;
    END
  END ck[0]
  OBS
    LAYER M1 ;
      RECT 0 0 17.256 30.240 ;
    LAYER M2 ;
      RECT 0 0 17.256 30.240 ;
    LAYER M3 ;
      RECT 0 0 17.256 30.240 ;
  END
END dsfd_hstnh_276_sp0

# tools/dsrom_s81_fulldie.py abstract: Banded real register stage
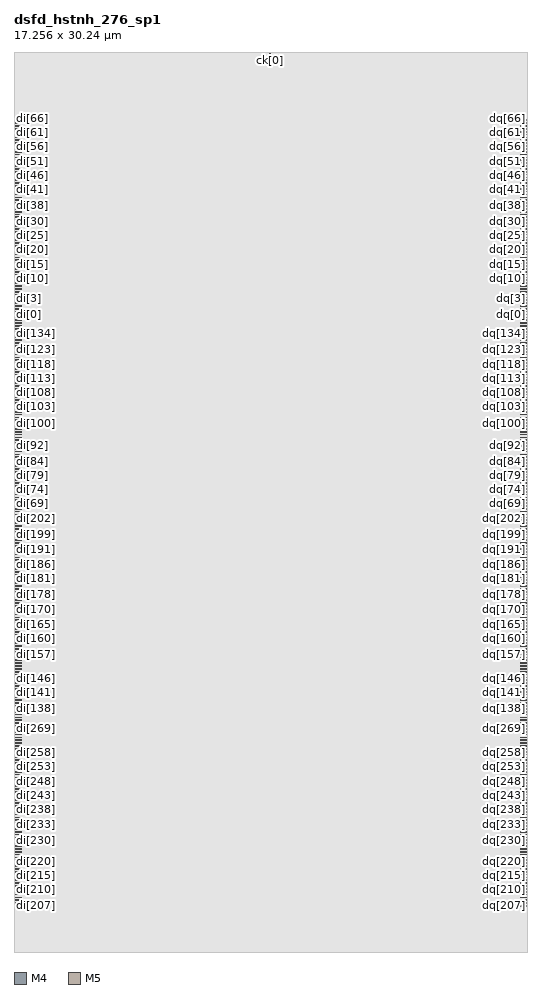
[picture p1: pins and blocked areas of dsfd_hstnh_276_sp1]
MACRO dsfd_hstnh_276_sp1
  CLASS BLOCK ;
  FOREIGN dsfd_hstnh_276_sp1 0 0 ;
  SIZE 17.256 BY 30.240 ;
  SYMMETRY X Y ;
  PIN di[0]
    DIRECTION INOUT ;
    USE SIGNAL ;
    PORT
      LAYER M4 ;
        RECT 0.048 21.408 0.240 21.432 ;
    END
  END di[0]
  PIN di[1]
    DIRECTION INOUT ;
    USE SIGNAL ;
    PORT
      LAYER M4 ;
        RECT 0.048 21.504 0.240 21.528 ;
    END
  END di[1]
  PIN di[2]
    DIRECTION INOUT ;
    USE SIGNAL ;
    PORT
      LAYER M4 ;
        RECT 0.048 21.600 0.240 21.624 ;
    END
  END di[2]
  PIN di[3]
    DIRECTION INOUT ;
    USE SIGNAL ;
    PORT
      LAYER M4 ;
        RECT 0.048 21.696 0.240 21.720 ;
    END
  END di[3]
  PIN di[4]
    DIRECTION INOUT ;
    USE SIGNAL ;
    PORT
      LAYER M4 ;
        RECT 0.048 21.792 0.240 21.816 ;
    END
  END di[4]
  PIN di[5]
    DIRECTION INOUT ;
    USE SIGNAL ;
    PORT
      LAYER M4 ;
        RECT 0.048 21.888 0.240 21.912 ;
    END
  END di[5]
  PIN di[6]
    DIRECTION INOUT ;
    USE SIGNAL ;
    PORT
      LAYER M4 ;
        RECT 0.048 21.984 0.240 22.008 ;
    END
  END di[6]
  PIN di[7]
    DIRECTION INOUT ;
    USE SIGNAL ;
    PORT
      LAYER M4 ;
        RECT 0.048 22.080 0.240 22.104 ;
    END
  END di[7]
  PIN di[8]
    DIRECTION INOUT ;
    USE SIGNAL ;
    PORT
      LAYER M4 ;
        RECT 0.048 22.176 0.240 22.200 ;
    END
  END di[8]
  PIN di[9]
    DIRECTION INOUT ;
    USE SIGNAL ;
    PORT
      LAYER M4 ;
        RECT 0.048 22.272 0.240 22.296 ;
    END
  END di[9]
  PIN di[10]
    DIRECTION INOUT ;
    USE SIGNAL ;
    PORT
      LAYER M4 ;
        RECT 0.048 22.368 0.240 22.392 ;
    END
  END di[10]
  PIN di[11]
    DIRECTION INOUT ;
    USE SIGNAL ;
    PORT
      LAYER M4 ;
        RECT 0.048 22.464 0.240 22.488 ;
    END
  END di[11]
  PIN di[12]
    DIRECTION INOUT ;
    USE SIGNAL ;
    PORT
      LAYER M4 ;
        RECT 0.048 22.560 0.240 22.584 ;
    END
  END di[12]
  PIN di[13]
    DIRECTION INOUT ;
    USE SIGNAL ;
    PORT
      LAYER M4 ;
        RECT 0.048 22.656 0.240 22.680 ;
    END
  END di[13]
  PIN di[14]
    DIRECTION INOUT ;
    USE SIGNAL ;
    PORT
      LAYER M4 ;
        RECT 0.048 22.752 0.240 22.776 ;
    END
  END di[14]
  PIN di[15]
    DIRECTION INOUT ;
    USE SIGNAL ;
    PORT
      LAYER M4 ;
        RECT 0.048 22.848 0.240 22.872 ;
    END
  END di[15]
  PIN di[16]
    DIRECTION INOUT ;
    USE SIGNAL ;
    PORT
      LAYER M4 ;
        RECT 0.048 22.944 0.240 22.968 ;
    END
  END di[16]
  PIN di[17]
    DIRECTION INOUT ;
    USE SIGNAL ;
    PORT
      LAYER M4 ;
        RECT 0.048 23.040 0.240 23.064 ;
    END
  END di[17]
  PIN di[18]
    DIRECTION INOUT ;
    USE SIGNAL ;
    PORT
      LAYER M4 ;
        RECT 0.048 23.136 0.240 23.160 ;
    END
  END di[18]
  PIN di[19]
    DIRECTION INOUT ;
    USE SIGNAL ;
    PORT
      LAYER M4 ;
        RECT 0.048 23.232 0.240 23.256 ;
    END
  END di[19]
  PIN di[20]
    DIRECTION INOUT ;
    USE SIGNAL ;
    PORT
      LAYER M4 ;
        RECT 0.048 23.328 0.240 23.352 ;
    END
  END di[20]
  PIN di[21]
    DIRECTION INOUT ;
    USE SIGNAL ;
    PORT
      LAYER M4 ;
        RECT 0.048 23.424 0.240 23.448 ;
    END
  END di[21]
  PIN di[22]
    DIRECTION INOUT ;
    USE SIGNAL ;
    PORT
      LAYER M4 ;
        RECT 0.048 23.520 0.240 23.544 ;
    END
  END di[22]
  PIN di[23]
    DIRECTION INOUT ;
    USE SIGNAL ;
    PORT
      LAYER M4 ;
        RECT 0.048 23.616 0.240 23.640 ;
    END
  END di[23]
  PIN di[24]
    DIRECTION INOUT ;
    USE SIGNAL ;
    PORT
      LAYER M4 ;
        RECT 0.048 23.712 0.240 23.736 ;
    END
  END di[24]
  PIN di[25]
    DIRECTION INOUT ;
    USE SIGNAL ;
    PORT
      LAYER M4 ;
        RECT 0.048 23.808 0.240 23.832 ;
    END
  END di[25]
  PIN di[26]
    DIRECTION INOUT ;
    USE SIGNAL ;
    PORT
      LAYER M4 ;
        RECT 0.048 23.904 0.240 23.928 ;
    END
  END di[26]
  PIN di[27]
    DIRECTION INOUT ;
    USE SIGNAL ;
    PORT
      LAYER M4 ;
        RECT 0.048 24.000 0.240 24.024 ;
    END
  END di[27]
  PIN di[28]
    DIRECTION INOUT ;
    USE SIGNAL ;
    PORT
      LAYER M4 ;
        RECT 0.048 24.096 0.240 24.120 ;
    END
  END di[28]
  PIN di[29]
    DIRECTION INOUT ;
    USE SIGNAL ;
    PORT
      LAYER M4 ;
        RECT 0.048 24.192 0.240 24.216 ;
    END
  END di[29]
  PIN di[30]
    DIRECTION INOUT ;
    USE SIGNAL ;
    PORT
      LAYER M4 ;
        RECT 0.048 24.288 0.240 24.312 ;
    END
  END di[30]
  PIN di[31]
    DIRECTION INOUT ;
    USE SIGNAL ;
    PORT
      LAYER M4 ;
        RECT 0.048 24.384 0.240 24.408 ;
    END
  END di[31]
  PIN di[32]
    DIRECTION INOUT ;
    USE SIGNAL ;
    PORT
      LAYER M4 ;
        RECT 0.048 24.480 0.240 24.504 ;
    END
  END di[32]
  PIN di[33]
    DIRECTION INOUT ;
    USE SIGNAL ;
    PORT
      LAYER M4 ;
        RECT 0.048 24.576 0.240 24.600 ;
    END
  END di[33]
  PIN di[34]
    DIRECTION INOUT ;
    USE SIGNAL ;
    PORT
      LAYER M4 ;
        RECT 0.048 24.672 0.240 24.696 ;
    END
  END di[34]
  PIN di[35]
    DIRECTION INOUT ;
    USE SIGNAL ;
    PORT
      LAYER M4 ;
        RECT 0.048 24.768 0.240 24.792 ;
    END
  END di[35]
  PIN di[36]
    DIRECTION INOUT ;
    USE SIGNAL ;
    PORT
      LAYER M4 ;
        RECT 0.048 24.864 0.240 24.888 ;
    END
  END di[36]
  PIN di[37]
    DIRECTION INOUT ;
    USE SIGNAL ;
    PORT
      LAYER M4 ;
        RECT 0.048 24.960 0.240 24.984 ;
    END
  END di[37]
  PIN di[38]
    DIRECTION INOUT ;
    USE SIGNAL ;
    PORT
      LAYER M4 ;
        RECT 0.048 25.056 0.240 25.080 ;
    END
  END di[38]
  PIN di[39]
    DIRECTION INOUT ;
    USE SIGNAL ;
    PORT
      LAYER M4 ;
        RECT 0.048 25.152 0.240 25.176 ;
    END
  END di[39]
  PIN di[40]
    DIRECTION INOUT ;
    USE SIGNAL ;
    PORT
      LAYER M4 ;
        RECT 0.048 25.248 0.240 25.272 ;
    END
  END di[40]
  PIN di[41]
    DIRECTION INOUT ;
    USE SIGNAL ;
    PORT
      LAYER M4 ;
        RECT 0.048 25.344 0.240 25.368 ;
    END
  END di[41]
  PIN di[42]
    DIRECTION INOUT ;
    USE SIGNAL ;
    PORT
      LAYER M4 ;
        RECT 0.048 25.440 0.240 25.464 ;
    END
  END di[42]
  PIN di[43]
    DIRECTION INOUT ;
    USE SIGNAL ;
    PORT
      LAYER M4 ;
        RECT 0.048 25.536 0.240 25.560 ;
    END
  END di[43]
  PIN di[44]
    DIRECTION INOUT ;
    USE SIGNAL ;
    PORT
      LAYER M4 ;
        RECT 0.048 25.632 0.240 25.656 ;
    END
  END di[44]
  PIN di[45]
    DIRECTION INOUT ;
    USE SIGNAL ;
    PORT
      LAYER M4 ;
        RECT 0.048 25.728 0.240 25.752 ;
    END
  END di[45]
  PIN di[46]
    DIRECTION INOUT ;
    USE SIGNAL ;
    PORT
      LAYER M4 ;
        RECT 0.048 25.824 0.240 25.848 ;
    END
  END di[46]
  PIN di[47]
    DIRECTION INOUT ;
    USE SIGNAL ;
    PORT
      LAYER M4 ;
        RECT 0.048 25.920 0.240 25.944 ;
    END
  END di[47]
  PIN di[48]
    DIRECTION INOUT ;
    USE SIGNAL ;
    PORT
      LAYER M4 ;
        RECT 0.048 26.016 0.240 26.040 ;
    END
  END di[48]
  PIN di[49]
    DIRECTION INOUT ;
    USE SIGNAL ;
    PORT
      LAYER M4 ;
        RECT 0.048 26.112 0.240 26.136 ;
    END
  END di[49]
  PIN di[50]
    DIRECTION INOUT ;
    USE SIGNAL ;
    PORT
      LAYER M4 ;
        RECT 0.048 26.208 0.240 26.232 ;
    END
  END di[50]
  PIN di[51]
    DIRECTION INOUT ;
    USE SIGNAL ;
    PORT
      LAYER M4 ;
        RECT 0.048 26.304 0.240 26.328 ;
    END
  END di[51]
  PIN di[52]
    DIRECTION INOUT ;
    USE SIGNAL ;
    PORT
      LAYER M4 ;
        RECT 0.048 26.400 0.240 26.424 ;
    END
  END di[52]
  PIN di[53]
    DIRECTION INOUT ;
    USE SIGNAL ;
    PORT
      LAYER M4 ;
        RECT 0.048 26.496 0.240 26.520 ;
    END
  END di[53]
  PIN di[54]
    DIRECTION INOUT ;
    USE SIGNAL ;
    PORT
      LAYER M4 ;
        RECT 0.048 26.592 0.240 26.616 ;
    END
  END di[54]
  PIN di[55]
    DIRECTION INOUT ;
    USE SIGNAL ;
    PORT
      LAYER M4 ;
        RECT 0.048 26.688 0.240 26.712 ;
    END
  END di[55]
  PIN di[56]
    DIRECTION INOUT ;
    USE SIGNAL ;
    PORT
      LAYER M4 ;
        RECT 0.048 26.784 0.240 26.808 ;
    END
  END di[56]
  PIN di[57]
    DIRECTION INOUT ;
    USE SIGNAL ;
    PORT
      LAYER M4 ;
        RECT 0.048 26.880 0.240 26.904 ;
    END
  END di[57]
  PIN di[58]
    DIRECTION INOUT ;
    USE SIGNAL ;
    PORT
      LAYER M4 ;
        RECT 0.048 26.976 0.240 27.000 ;
    END
  END di[58]
  PIN di[59]
    DIRECTION INOUT ;
    USE SIGNAL ;
    PORT
      LAYER M4 ;
        RECT 0.048 27.072 0.240 27.096 ;
    END
  END di[59]
  PIN di[60]
    DIRECTION INOUT ;
    USE SIGNAL ;
    PORT
      LAYER M4 ;
        RECT 0.048 27.168 0.240 27.192 ;
    END
  END di[60]
  PIN di[61]
    DIRECTION INOUT ;
    USE SIGNAL ;
    PORT
      LAYER M4 ;
        RECT 0.048 27.264 0.240 27.288 ;
    END
  END di[61]
  PIN di[62]
    DIRECTION INOUT ;
    USE SIGNAL ;
    PORT
      LAYER M4 ;
        RECT 0.048 27.360 0.240 27.384 ;
    END
  END di[62]
  PIN di[63]
    DIRECTION INOUT ;
    USE SIGNAL ;
    PORT
      LAYER M4 ;
        RECT 0.048 27.456 0.240 27.480 ;
    END
  END di[63]
  PIN di[64]
    DIRECTION INOUT ;
    USE SIGNAL ;
    PORT
      LAYER M4 ;
        RECT 0.048 27.552 0.240 27.576 ;
    END
  END di[64]
  PIN di[65]
    DIRECTION INOUT ;
    USE SIGNAL ;
    PORT
      LAYER M4 ;
        RECT 0.048 27.648 0.240 27.672 ;
    END
  END di[65]
  PIN di[66]
    DIRECTION INOUT ;
    USE SIGNAL ;
    PORT
      LAYER M4 ;
        RECT 0.048 27.744 0.240 27.768 ;
    END
  END di[66]
  PIN di[67]
    DIRECTION INOUT ;
    USE SIGNAL ;
    PORT
      LAYER M4 ;
        RECT 0.048 27.840 0.240 27.864 ;
    END
  END di[67]
  PIN di[68]
    DIRECTION INOUT ;
    USE SIGNAL ;
    PORT
      LAYER M4 ;
        RECT 0.048 27.936 0.240 27.960 ;
    END
  END di[68]
  PIN di[69]
    DIRECTION INOUT ;
    USE SIGNAL ;
    PORT
      LAYER M4 ;
        RECT 0.048 14.784 0.240 14.808 ;
    END
  END di[69]
  PIN di[70]
    DIRECTION INOUT ;
    USE SIGNAL ;
    PORT
      LAYER M4 ;
        RECT 0.048 14.880 0.240 14.904 ;
    END
  END di[70]
  PIN di[71]
    DIRECTION INOUT ;
    USE SIGNAL ;
    PORT
      LAYER M4 ;
        RECT 0.048 14.976 0.240 15.000 ;
    END
  END di[71]
  PIN di[72]
    DIRECTION INOUT ;
    USE SIGNAL ;
    PORT
      LAYER M4 ;
        RECT 0.048 15.072 0.240 15.096 ;
    END
  END di[72]
  PIN di[73]
    DIRECTION INOUT ;
    USE SIGNAL ;
    PORT
      LAYER M4 ;
        RECT 0.048 15.168 0.240 15.192 ;
    END
  END di[73]
  PIN di[74]
    DIRECTION INOUT ;
    USE SIGNAL ;
    PORT
      LAYER M4 ;
        RECT 0.048 15.264 0.240 15.288 ;
    END
  END di[74]
  PIN di[75]
    DIRECTION INOUT ;
    USE SIGNAL ;
    PORT
      LAYER M4 ;
        RECT 0.048 15.360 0.240 15.384 ;
    END
  END di[75]
  PIN di[76]
    DIRECTION INOUT ;
    USE SIGNAL ;
    PORT
      LAYER M4 ;
        RECT 0.048 15.456 0.240 15.480 ;
    END
  END di[76]
  PIN di[77]
    DIRECTION INOUT ;
    USE SIGNAL ;
    PORT
      LAYER M4 ;
        RECT 0.048 15.552 0.240 15.576 ;
    END
  END di[77]
  PIN di[78]
    DIRECTION INOUT ;
    USE SIGNAL ;
    PORT
      LAYER M4 ;
        RECT 0.048 15.648 0.240 15.672 ;
    END
  END di[78]
  PIN di[79]
    DIRECTION INOUT ;
    USE SIGNAL ;
    PORT
      LAYER M4 ;
        RECT 0.048 15.744 0.240 15.768 ;
    END
  END di[79]
  PIN di[80]
    DIRECTION INOUT ;
    USE SIGNAL ;
    PORT
      LAYER M4 ;
        RECT 0.048 15.840 0.240 15.864 ;
    END
  END di[80]
  PIN di[81]
    DIRECTION INOUT ;
    USE SIGNAL ;
    PORT
      LAYER M4 ;
        RECT 0.048 15.936 0.240 15.960 ;
    END
  END di[81]
  PIN di[82]
    DIRECTION INOUT ;
    USE SIGNAL ;
    PORT
      LAYER M4 ;
        RECT 0.048 16.032 0.240 16.056 ;
    END
  END di[82]
  PIN di[83]
    DIRECTION INOUT ;
    USE SIGNAL ;
    PORT
      LAYER M4 ;
        RECT 0.048 16.128 0.240 16.152 ;
    END
  END di[83]
  PIN di[84]
    DIRECTION INOUT ;
    USE SIGNAL ;
    PORT
      LAYER M4 ;
        RECT 0.048 16.224 0.240 16.248 ;
    END
  END di[84]
  PIN di[85]
    DIRECTION INOUT ;
    USE SIGNAL ;
    PORT
      LAYER M4 ;
        RECT 0.048 16.320 0.240 16.344 ;
    END
  END di[85]
  PIN di[86]
    DIRECTION INOUT ;
    USE SIGNAL ;
    PORT
      LAYER M4 ;
        RECT 0.048 16.416 0.240 16.440 ;
    END
  END di[86]
  PIN di[87]
    DIRECTION INOUT ;
    USE SIGNAL ;
    PORT
      LAYER M4 ;
        RECT 0.048 16.512 0.240 16.536 ;
    END
  END di[87]
  PIN di[88]
    DIRECTION INOUT ;
    USE SIGNAL ;
    PORT
      LAYER M4 ;
        RECT 0.048 16.608 0.240 16.632 ;
    END
  END di[88]
  PIN di[89]
    DIRECTION INOUT ;
    USE SIGNAL ;
    PORT
      LAYER M4 ;
        RECT 0.048 16.704 0.240 16.728 ;
    END
  END di[89]
  PIN di[90]
    DIRECTION INOUT ;
    USE SIGNAL ;
    PORT
      LAYER M4 ;
        RECT 0.048 16.800 0.240 16.824 ;
    END
  END di[90]
  PIN di[91]
    DIRECTION INOUT ;
    USE SIGNAL ;
    PORT
      LAYER M4 ;
        RECT 0.048 16.896 0.240 16.920 ;
    END
  END di[91]
  PIN di[92]
    DIRECTION INOUT ;
    USE SIGNAL ;
    PORT
      LAYER M4 ;
        RECT 0.048 16.992 0.240 17.016 ;
    END
  END di[92]
  PIN di[93]
    DIRECTION INOUT ;
    USE SIGNAL ;
    PORT
      LAYER M4 ;
        RECT 0.048 17.088 0.240 17.112 ;
    END
  END di[93]
  PIN di[94]
    DIRECTION INOUT ;
    USE SIGNAL ;
    PORT
      LAYER M4 ;
        RECT 0.048 17.184 0.240 17.208 ;
    END
  END di[94]
  PIN di[95]
    DIRECTION INOUT ;
    USE SIGNAL ;
    PORT
      LAYER M4 ;
        RECT 0.048 17.280 0.240 17.304 ;
    END
  END di[95]
  PIN di[96]
    DIRECTION INOUT ;
    USE SIGNAL ;
    PORT
      LAYER M4 ;
        RECT 0.048 17.376 0.240 17.400 ;
    END
  END di[96]
  PIN di[97]
    DIRECTION INOUT ;
    USE SIGNAL ;
    PORT
      LAYER M4 ;
        RECT 0.048 17.472 0.240 17.496 ;
    END
  END di[97]
  PIN di[98]
    DIRECTION INOUT ;
    USE SIGNAL ;
    PORT
      LAYER M4 ;
        RECT 0.048 17.568 0.240 17.592 ;
    END
  END di[98]
  PIN di[99]
    DIRECTION INOUT ;
    USE SIGNAL ;
    PORT
      LAYER M4 ;
        RECT 0.048 17.664 0.240 17.688 ;
    END
  END di[99]
  PIN di[100]
    DIRECTION INOUT ;
    USE SIGNAL ;
    PORT
      LAYER M4 ;
        RECT 0.048 17.760 0.240 17.784 ;
    END
  END di[100]
  PIN di[101]
    DIRECTION INOUT ;
    USE SIGNAL ;
    PORT
      LAYER M4 ;
        RECT 0.048 17.856 0.240 17.880 ;
    END
  END di[101]
  PIN di[102]
    DIRECTION INOUT ;
    USE SIGNAL ;
    PORT
      LAYER M4 ;
        RECT 0.048 17.952 0.240 17.976 ;
    END
  END di[102]
  PIN di[103]
    DIRECTION INOUT ;
    USE SIGNAL ;
    PORT
      LAYER M4 ;
        RECT 0.048 18.048 0.240 18.072 ;
    END
  END di[103]
  PIN di[104]
    DIRECTION INOUT ;
    USE SIGNAL ;
    PORT
      LAYER M4 ;
        RECT 0.048 18.144 0.240 18.168 ;
    END
  END di[104]
  PIN di[105]
    DIRECTION INOUT ;
    USE SIGNAL ;
    PORT
      LAYER M4 ;
        RECT 0.048 18.240 0.240 18.264 ;
    END
  END di[105]
  PIN di[106]
    DIRECTION INOUT ;
    USE SIGNAL ;
    PORT
      LAYER M4 ;
        RECT 0.048 18.336 0.240 18.360 ;
    END
  END di[106]
  PIN di[107]
    DIRECTION INOUT ;
    USE SIGNAL ;
    PORT
      LAYER M4 ;
        RECT 0.048 18.432 0.240 18.456 ;
    END
  END di[107]
  PIN di[108]
    DIRECTION INOUT ;
    USE SIGNAL ;
    PORT
      LAYER M4 ;
        RECT 0.048 18.528 0.240 18.552 ;
    END
  END di[108]
  PIN di[109]
    DIRECTION INOUT ;
    USE SIGNAL ;
    PORT
      LAYER M4 ;
        RECT 0.048 18.624 0.240 18.648 ;
    END
  END di[109]
  PIN di[110]
    DIRECTION INOUT ;
    USE SIGNAL ;
    PORT
      LAYER M4 ;
        RECT 0.048 18.720 0.240 18.744 ;
    END
  END di[110]
  PIN di[111]
    DIRECTION INOUT ;
    USE SIGNAL ;
    PORT
      LAYER M4 ;
        RECT 0.048 18.816 0.240 18.840 ;
    END
  END di[111]
  PIN di[112]
    DIRECTION INOUT ;
    USE SIGNAL ;
    PORT
      LAYER M4 ;
        RECT 0.048 18.912 0.240 18.936 ;
    END
  END di[112]
  PIN di[113]
    DIRECTION INOUT ;
    USE SIGNAL ;
    PORT
      LAYER M4 ;
        RECT 0.048 19.008 0.240 19.032 ;
    END
  END di[113]
  PIN di[114]
    DIRECTION INOUT ;
    USE SIGNAL ;
    PORT
      LAYER M4 ;
        RECT 0.048 19.104 0.240 19.128 ;
    END
  END di[114]
  PIN di[115]
    DIRECTION INOUT ;
    USE SIGNAL ;
    PORT
      LAYER M4 ;
        RECT 0.048 19.200 0.240 19.224 ;
    END
  END di[115]
  PIN di[116]
    DIRECTION INOUT ;
    USE SIGNAL ;
    PORT
      LAYER M4 ;
        RECT 0.048 19.296 0.240 19.320 ;
    END
  END di[116]
  PIN di[117]
    DIRECTION INOUT ;
    USE SIGNAL ;
    PORT
      LAYER M4 ;
        RECT 0.048 19.392 0.240 19.416 ;
    END
  END di[117]
  PIN di[118]
    DIRECTION INOUT ;
    USE SIGNAL ;
    PORT
      LAYER M4 ;
        RECT 0.048 19.488 0.240 19.512 ;
    END
  END di[118]
  PIN di[119]
    DIRECTION INOUT ;
    USE SIGNAL ;
    PORT
      LAYER M4 ;
        RECT 0.048 19.584 0.240 19.608 ;
    END
  END di[119]
  PIN di[120]
    DIRECTION INOUT ;
    USE SIGNAL ;
    PORT
      LAYER M4 ;
        RECT 0.048 19.680 0.240 19.704 ;
    END
  END di[120]
  PIN di[121]
    DIRECTION INOUT ;
    USE SIGNAL ;
    PORT
      LAYER M4 ;
        RECT 0.048 19.776 0.240 19.800 ;
    END
  END di[121]
  PIN di[122]
    DIRECTION INOUT ;
    USE SIGNAL ;
    PORT
      LAYER M4 ;
        RECT 0.048 19.872 0.240 19.896 ;
    END
  END di[122]
  PIN di[123]
    DIRECTION INOUT ;
    USE SIGNAL ;
    PORT
      LAYER M4 ;
        RECT 0.048 19.968 0.240 19.992 ;
    END
  END di[123]
  PIN di[124]
    DIRECTION INOUT ;
    USE SIGNAL ;
    PORT
      LAYER M4 ;
        RECT 0.048 20.064 0.240 20.088 ;
    END
  END di[124]
  PIN di[125]
    DIRECTION INOUT ;
    USE SIGNAL ;
    PORT
      LAYER M4 ;
        RECT 0.048 20.160 0.240 20.184 ;
    END
  END di[125]
  PIN di[126]
    DIRECTION INOUT ;
    USE SIGNAL ;
    PORT
      LAYER M4 ;
        RECT 0.048 20.256 0.240 20.280 ;
    END
  END di[126]
  PIN di[127]
    DIRECTION INOUT ;
    USE SIGNAL ;
    PORT
      LAYER M4 ;
        RECT 0.048 20.352 0.240 20.376 ;
    END
  END di[127]
  PIN di[128]
    DIRECTION INOUT ;
    USE SIGNAL ;
    PORT
      LAYER M4 ;
        RECT 0.048 20.448 0.240 20.472 ;
    END
  END di[128]
  PIN di[129]
    DIRECTION INOUT ;
    USE SIGNAL ;
    PORT
      LAYER M4 ;
        RECT 0.048 20.544 0.240 20.568 ;
    END
  END di[129]
  PIN di[130]
    DIRECTION INOUT ;
    USE SIGNAL ;
    PORT
      LAYER M4 ;
        RECT 0.048 20.640 0.240 20.664 ;
    END
  END di[130]
  PIN di[131]
    DIRECTION INOUT ;
    USE SIGNAL ;
    PORT
      LAYER M4 ;
        RECT 0.048 20.736 0.240 20.760 ;
    END
  END di[131]
  PIN di[132]
    DIRECTION INOUT ;
    USE SIGNAL ;
    PORT
      LAYER M4 ;
        RECT 0.048 20.832 0.240 20.856 ;
    END
  END di[132]
  PIN di[133]
    DIRECTION INOUT ;
    USE SIGNAL ;
    PORT
      LAYER M4 ;
        RECT 0.048 20.928 0.240 20.952 ;
    END
  END di[133]
  PIN di[134]
    DIRECTION INOUT ;
    USE SIGNAL ;
    PORT
      LAYER M4 ;
        RECT 0.048 21.024 0.240 21.048 ;
    END
  END di[134]
  PIN di[135]
    DIRECTION INOUT ;
    USE SIGNAL ;
    PORT
      LAYER M4 ;
        RECT 0.048 21.120 0.240 21.144 ;
    END
  END di[135]
  PIN di[136]
    DIRECTION INOUT ;
    USE SIGNAL ;
    PORT
      LAYER M4 ;
        RECT 0.048 21.216 0.240 21.240 ;
    END
  END di[136]
  PIN di[137]
    DIRECTION INOUT ;
    USE SIGNAL ;
    PORT
      LAYER M4 ;
        RECT 0.048 21.312 0.240 21.336 ;
    END
  END di[137]
  PIN di[138]
    DIRECTION INOUT ;
    USE SIGNAL ;
    PORT
      LAYER M4 ;
        RECT 0.048 8.160 0.240 8.184 ;
    END
  END di[138]
  PIN di[139]
    DIRECTION INOUT ;
    USE SIGNAL ;
    PORT
      LAYER M4 ;
        RECT 0.048 8.256 0.240 8.280 ;
    END
  END di[139]
  PIN di[140]
    DIRECTION INOUT ;
    USE SIGNAL ;
    PORT
      LAYER M4 ;
        RECT 0.048 8.352 0.240 8.376 ;
    END
  END di[140]
  PIN di[141]
    DIRECTION INOUT ;
    USE SIGNAL ;
    PORT
      LAYER M4 ;
        RECT 0.048 8.448 0.240 8.472 ;
    END
  END di[141]
  PIN di[142]
    DIRECTION INOUT ;
    USE SIGNAL ;
    PORT
      LAYER M4 ;
        RECT 0.048 8.544 0.240 8.568 ;
    END
  END di[142]
  PIN di[143]
    DIRECTION INOUT ;
    USE SIGNAL ;
    PORT
      LAYER M4 ;
        RECT 0.048 8.640 0.240 8.664 ;
    END
  END di[143]
  PIN di[144]
    DIRECTION INOUT ;
    USE SIGNAL ;
    PORT
      LAYER M4 ;
        RECT 0.048 8.736 0.240 8.760 ;
    END
  END di[144]
  PIN di[145]
    DIRECTION INOUT ;
    USE SIGNAL ;
    PORT
      LAYER M4 ;
        RECT 0.048 8.832 0.240 8.856 ;
    END
  END di[145]
  PIN di[146]
    DIRECTION INOUT ;
    USE SIGNAL ;
    PORT
      LAYER M4 ;
        RECT 0.048 8.928 0.240 8.952 ;
    END
  END di[146]
  PIN di[147]
    DIRECTION INOUT ;
    USE SIGNAL ;
    PORT
      LAYER M4 ;
        RECT 0.048 9.024 0.240 9.048 ;
    END
  END di[147]
  PIN di[148]
    DIRECTION INOUT ;
    USE SIGNAL ;
    PORT
      LAYER M4 ;
        RECT 0.048 9.120 0.240 9.144 ;
    END
  END di[148]
  PIN di[149]
    DIRECTION INOUT ;
    USE SIGNAL ;
    PORT
      LAYER M4 ;
        RECT 0.048 9.216 0.240 9.240 ;
    END
  END di[149]
  PIN di[150]
    DIRECTION INOUT ;
    USE SIGNAL ;
    PORT
      LAYER M4 ;
        RECT 0.048 9.312 0.240 9.336 ;
    END
  END di[150]
  PIN di[151]
    DIRECTION INOUT ;
    USE SIGNAL ;
    PORT
      LAYER M4 ;
        RECT 0.048 9.408 0.240 9.432 ;
    END
  END di[151]
  PIN di[152]
    DIRECTION INOUT ;
    USE SIGNAL ;
    PORT
      LAYER M4 ;
        RECT 0.048 9.504 0.240 9.528 ;
    END
  END di[152]
  PIN di[153]
    DIRECTION INOUT ;
    USE SIGNAL ;
    PORT
      LAYER M4 ;
        RECT 0.048 9.600 0.240 9.624 ;
    END
  END di[153]
  PIN di[154]
    DIRECTION INOUT ;
    USE SIGNAL ;
    PORT
      LAYER M4 ;
        RECT 0.048 9.696 0.240 9.720 ;
    END
  END di[154]
  PIN di[155]
    DIRECTION INOUT ;
    USE SIGNAL ;
    PORT
      LAYER M4 ;
        RECT 0.048 9.792 0.240 9.816 ;
    END
  END di[155]
  PIN di[156]
    DIRECTION INOUT ;
    USE SIGNAL ;
    PORT
      LAYER M4 ;
        RECT 0.048 9.888 0.240 9.912 ;
    END
  END di[156]
  PIN di[157]
    DIRECTION INOUT ;
    USE SIGNAL ;
    PORT
      LAYER M4 ;
        RECT 0.048 9.984 0.240 10.008 ;
    END
  END di[157]
  PIN di[158]
    DIRECTION INOUT ;
    USE SIGNAL ;
    PORT
      LAYER M4 ;
        RECT 0.048 10.080 0.240 10.104 ;
    END
  END di[158]
  PIN di[159]
    DIRECTION INOUT ;
    USE SIGNAL ;
    PORT
      LAYER M4 ;
        RECT 0.048 10.176 0.240 10.200 ;
    END
  END di[159]
  PIN di[160]
    DIRECTION INOUT ;
    USE SIGNAL ;
    PORT
      LAYER M4 ;
        RECT 0.048 10.272 0.240 10.296 ;
    END
  END di[160]
  PIN di[161]
    DIRECTION INOUT ;
    USE SIGNAL ;
    PORT
      LAYER M4 ;
        RECT 0.048 10.368 0.240 10.392 ;
    END
  END di[161]
  PIN di[162]
    DIRECTION INOUT ;
    USE SIGNAL ;
    PORT
      LAYER M4 ;
        RECT 0.048 10.464 0.240 10.488 ;
    END
  END di[162]
  PIN di[163]
    DIRECTION INOUT ;
    USE SIGNAL ;
    PORT
      LAYER M4 ;
        RECT 0.048 10.560 0.240 10.584 ;
    END
  END di[163]
  PIN di[164]
    DIRECTION INOUT ;
    USE SIGNAL ;
    PORT
      LAYER M4 ;
        RECT 0.048 10.656 0.240 10.680 ;
    END
  END di[164]
  PIN di[165]
    DIRECTION INOUT ;
    USE SIGNAL ;
    PORT
      LAYER M4 ;
        RECT 0.048 10.752 0.240 10.776 ;
    END
  END di[165]
  PIN di[166]
    DIRECTION INOUT ;
    USE SIGNAL ;
    PORT
      LAYER M4 ;
        RECT 0.048 10.848 0.240 10.872 ;
    END
  END di[166]
  PIN di[167]
    DIRECTION INOUT ;
    USE SIGNAL ;
    PORT
      LAYER M4 ;
        RECT 0.048 10.944 0.240 10.968 ;
    END
  END di[167]
  PIN di[168]
    DIRECTION INOUT ;
    USE SIGNAL ;
    PORT
      LAYER M4 ;
        RECT 0.048 11.040 0.240 11.064 ;
    END
  END di[168]
  PIN di[169]
    DIRECTION INOUT ;
    USE SIGNAL ;
    PORT
      LAYER M4 ;
        RECT 0.048 11.136 0.240 11.160 ;
    END
  END di[169]
  PIN di[170]
    DIRECTION INOUT ;
    USE SIGNAL ;
    PORT
      LAYER M4 ;
        RECT 0.048 11.232 0.240 11.256 ;
    END
  END di[170]
  PIN di[171]
    DIRECTION INOUT ;
    USE SIGNAL ;
    PORT
      LAYER M4 ;
        RECT 0.048 11.328 0.240 11.352 ;
    END
  END di[171]
  PIN di[172]
    DIRECTION INOUT ;
    USE SIGNAL ;
    PORT
      LAYER M4 ;
        RECT 0.048 11.424 0.240 11.448 ;
    END
  END di[172]
  PIN di[173]
    DIRECTION INOUT ;
    USE SIGNAL ;
    PORT
      LAYER M4 ;
        RECT 0.048 11.520 0.240 11.544 ;
    END
  END di[173]
  PIN di[174]
    DIRECTION INOUT ;
    USE SIGNAL ;
    PORT
      LAYER M4 ;
        RECT 0.048 11.616 0.240 11.640 ;
    END
  END di[174]
  PIN di[175]
    DIRECTION INOUT ;
    USE SIGNAL ;
    PORT
      LAYER M4 ;
        RECT 0.048 11.712 0.240 11.736 ;
    END
  END di[175]
  PIN di[176]
    DIRECTION INOUT ;
    USE SIGNAL ;
    PORT
      LAYER M4 ;
        RECT 0.048 11.808 0.240 11.832 ;
    END
  END di[176]
  PIN di[177]
    DIRECTION INOUT ;
    USE SIGNAL ;
    PORT
      LAYER M4 ;
        RECT 0.048 11.904 0.240 11.928 ;
    END
  END di[177]
  PIN di[178]
    DIRECTION INOUT ;
    USE SIGNAL ;
    PORT
      LAYER M4 ;
        RECT 0.048 12.000 0.240 12.024 ;
    END
  END di[178]
  PIN di[179]
    DIRECTION INOUT ;
    USE SIGNAL ;
    PORT
      LAYER M4 ;
        RECT 0.048 12.096 0.240 12.120 ;
    END
  END di[179]
  PIN di[180]
    DIRECTION INOUT ;
    USE SIGNAL ;
    PORT
      LAYER M4 ;
        RECT 0.048 12.192 0.240 12.216 ;
    END
  END di[180]
  PIN di[181]
    DIRECTION INOUT ;
    USE SIGNAL ;
    PORT
      LAYER M4 ;
        RECT 0.048 12.288 0.240 12.312 ;
    END
  END di[181]
  PIN di[182]
    DIRECTION INOUT ;
    USE SIGNAL ;
    PORT
      LAYER M4 ;
        RECT 0.048 12.384 0.240 12.408 ;
    END
  END di[182]
  PIN di[183]
    DIRECTION INOUT ;
    USE SIGNAL ;
    PORT
      LAYER M4 ;
        RECT 0.048 12.480 0.240 12.504 ;
    END
  END di[183]
  PIN di[184]
    DIRECTION INOUT ;
    USE SIGNAL ;
    PORT
      LAYER M4 ;
        RECT 0.048 12.576 0.240 12.600 ;
    END
  END di[184]
  PIN di[185]
    DIRECTION INOUT ;
    USE SIGNAL ;
    PORT
      LAYER M4 ;
        RECT 0.048 12.672 0.240 12.696 ;
    END
  END di[185]
  PIN di[186]
    DIRECTION INOUT ;
    USE SIGNAL ;
    PORT
      LAYER M4 ;
        RECT 0.048 12.768 0.240 12.792 ;
    END
  END di[186]
  PIN di[187]
    DIRECTION INOUT ;
    USE SIGNAL ;
    PORT
      LAYER M4 ;
        RECT 0.048 12.864 0.240 12.888 ;
    END
  END di[187]
  PIN di[188]
    DIRECTION INOUT ;
    USE SIGNAL ;
    PORT
      LAYER M4 ;
        RECT 0.048 12.960 0.240 12.984 ;
    END
  END di[188]
  PIN di[189]
    DIRECTION INOUT ;
    USE SIGNAL ;
    PORT
      LAYER M4 ;
        RECT 0.048 13.056 0.240 13.080 ;
    END
  END di[189]
  PIN di[190]
    DIRECTION INOUT ;
    USE SIGNAL ;
    PORT
      LAYER M4 ;
        RECT 0.048 13.152 0.240 13.176 ;
    END
  END di[190]
  PIN di[191]
    DIRECTION INOUT ;
    USE SIGNAL ;
    PORT
      LAYER M4 ;
        RECT 0.048 13.248 0.240 13.272 ;
    END
  END di[191]
  PIN di[192]
    DIRECTION INOUT ;
    USE SIGNAL ;
    PORT
      LAYER M4 ;
        RECT 0.048 13.344 0.240 13.368 ;
    END
  END di[192]
  PIN di[193]
    DIRECTION INOUT ;
    USE SIGNAL ;
    PORT
      LAYER M4 ;
        RECT 0.048 13.440 0.240 13.464 ;
    END
  END di[193]
  PIN di[194]
    DIRECTION INOUT ;
    USE SIGNAL ;
    PORT
      LAYER M4 ;
        RECT 0.048 13.536 0.240 13.560 ;
    END
  END di[194]
  PIN di[195]
    DIRECTION INOUT ;
    USE SIGNAL ;
    PORT
      LAYER M4 ;
        RECT 0.048 13.632 0.240 13.656 ;
    END
  END di[195]
  PIN di[196]
    DIRECTION INOUT ;
    USE SIGNAL ;
    PORT
      LAYER M4 ;
        RECT 0.048 13.728 0.240 13.752 ;
    END
  END di[196]
  PIN di[197]
    DIRECTION INOUT ;
    USE SIGNAL ;
    PORT
      LAYER M4 ;
        RECT 0.048 13.824 0.240 13.848 ;
    END
  END di[197]
  PIN di[198]
    DIRECTION INOUT ;
    USE SIGNAL ;
    PORT
      LAYER M4 ;
        RECT 0.048 13.920 0.240 13.944 ;
    END
  END di[198]
  PIN di[199]
    DIRECTION INOUT ;
    USE SIGNAL ;
    PORT
      LAYER M4 ;
        RECT 0.048 14.016 0.240 14.040 ;
    END
  END di[199]
  PIN di[200]
    DIRECTION INOUT ;
    USE SIGNAL ;
    PORT
      LAYER M4 ;
        RECT 0.048 14.112 0.240 14.136 ;
    END
  END di[200]
  PIN di[201]
    DIRECTION INOUT ;
    USE SIGNAL ;
    PORT
      LAYER M4 ;
        RECT 0.048 14.208 0.240 14.232 ;
    END
  END di[201]
  PIN di[202]
    DIRECTION INOUT ;
    USE SIGNAL ;
    PORT
      LAYER M4 ;
        RECT 0.048 14.304 0.240 14.328 ;
    END
  END di[202]
  PIN di[203]
    DIRECTION INOUT ;
    USE SIGNAL ;
    PORT
      LAYER M4 ;
        RECT 0.048 14.400 0.240 14.424 ;
    END
  END di[203]
  PIN di[204]
    DIRECTION INOUT ;
    USE SIGNAL ;
    PORT
      LAYER M4 ;
        RECT 0.048 14.496 0.240 14.520 ;
    END
  END di[204]
  PIN di[205]
    DIRECTION INOUT ;
    USE SIGNAL ;
    PORT
      LAYER M4 ;
        RECT 0.048 14.592 0.240 14.616 ;
    END
  END di[205]
  PIN di[206]
    DIRECTION INOUT ;
    USE SIGNAL ;
    PORT
      LAYER M4 ;
        RECT 0.048 14.688 0.240 14.712 ;
    END
  END di[206]
  PIN di[207]
    DIRECTION INOUT ;
    USE SIGNAL ;
    PORT
      LAYER M4 ;
        RECT 0.048 1.536 0.240 1.560 ;
    END
  END di[207]
  PIN di[208]
    DIRECTION INOUT ;
    USE SIGNAL ;
    PORT
      LAYER M4 ;
        RECT 0.048 1.632 0.240 1.656 ;
    END
  END di[208]
  PIN di[209]
    DIRECTION INOUT ;
    USE SIGNAL ;
    PORT
      LAYER M4 ;
        RECT 0.048 1.728 0.240 1.752 ;
    END
  END di[209]
  PIN di[210]
    DIRECTION INOUT ;
    USE SIGNAL ;
    PORT
      LAYER M4 ;
        RECT 0.048 1.824 0.240 1.848 ;
    END
  END di[210]
  PIN di[211]
    DIRECTION INOUT ;
    USE SIGNAL ;
    PORT
      LAYER M4 ;
        RECT 0.048 1.920 0.240 1.944 ;
    END
  END di[211]
  PIN di[212]
    DIRECTION INOUT ;
    USE SIGNAL ;
    PORT
      LAYER M4 ;
        RECT 0.048 2.016 0.240 2.040 ;
    END
  END di[212]
  PIN di[213]
    DIRECTION INOUT ;
    USE SIGNAL ;
    PORT
      LAYER M4 ;
        RECT 0.048 2.112 0.240 2.136 ;
    END
  END di[213]
  PIN di[214]
    DIRECTION INOUT ;
    USE SIGNAL ;
    PORT
      LAYER M4 ;
        RECT 0.048 2.208 0.240 2.232 ;
    END
  END di[214]
  PIN di[215]
    DIRECTION INOUT ;
    USE SIGNAL ;
    PORT
      LAYER M4 ;
        RECT 0.048 2.304 0.240 2.328 ;
    END
  END di[215]
  PIN di[216]
    DIRECTION INOUT ;
    USE SIGNAL ;
    PORT
      LAYER M4 ;
        RECT 0.048 2.400 0.240 2.424 ;
    END
  END di[216]
  PIN di[217]
    DIRECTION INOUT ;
    USE SIGNAL ;
    PORT
      LAYER M4 ;
        RECT 0.048 2.496 0.240 2.520 ;
    END
  END di[217]
  PIN di[218]
    DIRECTION INOUT ;
    USE SIGNAL ;
    PORT
      LAYER M4 ;
        RECT 0.048 2.592 0.240 2.616 ;
    END
  END di[218]
  PIN di[219]
    DIRECTION INOUT ;
    USE SIGNAL ;
    PORT
      LAYER M4 ;
        RECT 0.048 2.688 0.240 2.712 ;
    END
  END di[219]
  PIN di[220]
    DIRECTION INOUT ;
    USE SIGNAL ;
    PORT
      LAYER M4 ;
        RECT 0.048 2.784 0.240 2.808 ;
    END
  END di[220]
  PIN di[221]
    DIRECTION INOUT ;
    USE SIGNAL ;
    PORT
      LAYER M4 ;
        RECT 0.048 2.880 0.240 2.904 ;
    END
  END di[221]
  PIN di[222]
    DIRECTION INOUT ;
    USE SIGNAL ;
    PORT
      LAYER M4 ;
        RECT 0.048 2.976 0.240 3.000 ;
    END
  END di[222]
  PIN di[223]
    DIRECTION INOUT ;
    USE SIGNAL ;
    PORT
      LAYER M4 ;
        RECT 0.048 3.072 0.240 3.096 ;
    END
  END di[223]
  PIN di[224]
    DIRECTION INOUT ;
    USE SIGNAL ;
    PORT
      LAYER M4 ;
        RECT 0.048 3.168 0.240 3.192 ;
    END
  END di[224]
  PIN di[225]
    DIRECTION INOUT ;
    USE SIGNAL ;
    PORT
      LAYER M4 ;
        RECT 0.048 3.264 0.240 3.288 ;
    END
  END di[225]
  PIN di[226]
    DIRECTION INOUT ;
    USE SIGNAL ;
    PORT
      LAYER M4 ;
        RECT 0.048 3.360 0.240 3.384 ;
    END
  END di[226]
  PIN di[227]
    DIRECTION INOUT ;
    USE SIGNAL ;
    PORT
      LAYER M4 ;
        RECT 0.048 3.456 0.240 3.480 ;
    END
  END di[227]
  PIN di[228]
    DIRECTION INOUT ;
    USE SIGNAL ;
    PORT
      LAYER M4 ;
        RECT 0.048 3.552 0.240 3.576 ;
    END
  END di[228]
  PIN di[229]
    DIRECTION INOUT ;
    USE SIGNAL ;
    PORT
      LAYER M4 ;
        RECT 0.048 3.648 0.240 3.672 ;
    END
  END di[229]
  PIN di[230]
    DIRECTION INOUT ;
    USE SIGNAL ;
    PORT
      LAYER M4 ;
        RECT 0.048 3.744 0.240 3.768 ;
    END
  END di[230]
  PIN di[231]
    DIRECTION INOUT ;
    USE SIGNAL ;
    PORT
      LAYER M4 ;
        RECT 0.048 3.840 0.240 3.864 ;
    END
  END di[231]
  PIN di[232]
    DIRECTION INOUT ;
    USE SIGNAL ;
    PORT
      LAYER M4 ;
        RECT 0.048 3.936 0.240 3.960 ;
    END
  END di[232]
  PIN di[233]
    DIRECTION INOUT ;
    USE SIGNAL ;
    PORT
      LAYER M4 ;
        RECT 0.048 4.032 0.240 4.056 ;
    END
  END di[233]
  PIN di[234]
    DIRECTION INOUT ;
    USE SIGNAL ;
    PORT
      LAYER M4 ;
        RECT 0.048 4.128 0.240 4.152 ;
    END
  END di[234]
  PIN di[235]
    DIRECTION INOUT ;
    USE SIGNAL ;
    PORT
      LAYER M4 ;
        RECT 0.048 4.224 0.240 4.248 ;
    END
  END di[235]
  PIN di[236]
    DIRECTION INOUT ;
    USE SIGNAL ;
    PORT
      LAYER M4 ;
        RECT 0.048 4.320 0.240 4.344 ;
    END
  END di[236]
  PIN di[237]
    DIRECTION INOUT ;
    USE SIGNAL ;
    PORT
      LAYER M4 ;
        RECT 0.048 4.416 0.240 4.440 ;
    END
  END di[237]
  PIN di[238]
    DIRECTION INOUT ;
    USE SIGNAL ;
    PORT
      LAYER M4 ;
        RECT 0.048 4.512 0.240 4.536 ;
    END
  END di[238]
  PIN di[239]
    DIRECTION INOUT ;
    USE SIGNAL ;
    PORT
      LAYER M4 ;
        RECT 0.048 4.608 0.240 4.632 ;
    END
  END di[239]
  PIN di[240]
    DIRECTION INOUT ;
    USE SIGNAL ;
    PORT
      LAYER M4 ;
        RECT 0.048 4.704 0.240 4.728 ;
    END
  END di[240]
  PIN di[241]
    DIRECTION INOUT ;
    USE SIGNAL ;
    PORT
      LAYER M4 ;
        RECT 0.048 4.800 0.240 4.824 ;
    END
  END di[241]
  PIN di[242]
    DIRECTION INOUT ;
    USE SIGNAL ;
    PORT
      LAYER M4 ;
        RECT 0.048 4.896 0.240 4.920 ;
    END
  END di[242]
  PIN di[243]
    DIRECTION INOUT ;
    USE SIGNAL ;
    PORT
      LAYER M4 ;
        RECT 0.048 4.992 0.240 5.016 ;
    END
  END di[243]
  PIN di[244]
    DIRECTION INOUT ;
    USE SIGNAL ;
    PORT
      LAYER M4 ;
        RECT 0.048 5.088 0.240 5.112 ;
    END
  END di[244]
  PIN di[245]
    DIRECTION INOUT ;
    USE SIGNAL ;
    PORT
      LAYER M4 ;
        RECT 0.048 5.184 0.240 5.208 ;
    END
  END di[245]
  PIN di[246]
    DIRECTION INOUT ;
    USE SIGNAL ;
    PORT
      LAYER M4 ;
        RECT 0.048 5.280 0.240 5.304 ;
    END
  END di[246]
  PIN di[247]
    DIRECTION INOUT ;
    USE SIGNAL ;
    PORT
      LAYER M4 ;
        RECT 0.048 5.376 0.240 5.400 ;
    END
  END di[247]
  PIN di[248]
    DIRECTION INOUT ;
    USE SIGNAL ;
    PORT
      LAYER M4 ;
        RECT 0.048 5.472 0.240 5.496 ;
    END
  END di[248]
  PIN di[249]
    DIRECTION INOUT ;
    USE SIGNAL ;
    PORT
      LAYER M4 ;
        RECT 0.048 5.568 0.240 5.592 ;
    END
  END di[249]
  PIN di[250]
    DIRECTION INOUT ;
    USE SIGNAL ;
    PORT
      LAYER M4 ;
        RECT 0.048 5.664 0.240 5.688 ;
    END
  END di[250]
  PIN di[251]
    DIRECTION INOUT ;
    USE SIGNAL ;
    PORT
      LAYER M4 ;
        RECT 0.048 5.760 0.240 5.784 ;
    END
  END di[251]
  PIN di[252]
    DIRECTION INOUT ;
    USE SIGNAL ;
    PORT
      LAYER M4 ;
        RECT 0.048 5.856 0.240 5.880 ;
    END
  END di[252]
  PIN di[253]
    DIRECTION INOUT ;
    USE SIGNAL ;
    PORT
      LAYER M4 ;
        RECT 0.048 5.952 0.240 5.976 ;
    END
  END di[253]
  PIN di[254]
    DIRECTION INOUT ;
    USE SIGNAL ;
    PORT
      LAYER M4 ;
        RECT 0.048 6.048 0.240 6.072 ;
    END
  END di[254]
  PIN di[255]
    DIRECTION INOUT ;
    USE SIGNAL ;
    PORT
      LAYER M4 ;
        RECT 0.048 6.144 0.240 6.168 ;
    END
  END di[255]
  PIN di[256]
    DIRECTION INOUT ;
    USE SIGNAL ;
    PORT
      LAYER M4 ;
        RECT 0.048 6.240 0.240 6.264 ;
    END
  END di[256]
  PIN di[257]
    DIRECTION INOUT ;
    USE SIGNAL ;
    PORT
      LAYER M4 ;
        RECT 0.048 6.336 0.240 6.360 ;
    END
  END di[257]
  PIN di[258]
    DIRECTION INOUT ;
    USE SIGNAL ;
    PORT
      LAYER M4 ;
        RECT 0.048 6.432 0.240 6.456 ;
    END
  END di[258]
  PIN di[259]
    DIRECTION INOUT ;
    USE SIGNAL ;
    PORT
      LAYER M4 ;
        RECT 0.048 6.528 0.240 6.552 ;
    END
  END di[259]
  PIN di[260]
    DIRECTION INOUT ;
    USE SIGNAL ;
    PORT
      LAYER M4 ;
        RECT 0.048 6.624 0.240 6.648 ;
    END
  END di[260]
  PIN di[261]
    DIRECTION INOUT ;
    USE SIGNAL ;
    PORT
      LAYER M4 ;
        RECT 0.048 6.720 0.240 6.744 ;
    END
  END di[261]
  PIN di[262]
    DIRECTION INOUT ;
    USE SIGNAL ;
    PORT
      LAYER M4 ;
        RECT 0.048 6.816 0.240 6.840 ;
    END
  END di[262]
  PIN di[263]
    DIRECTION INOUT ;
    USE SIGNAL ;
    PORT
      LAYER M4 ;
        RECT 0.048 6.912 0.240 6.936 ;
    END
  END di[263]
  PIN di[264]
    DIRECTION INOUT ;
    USE SIGNAL ;
    PORT
      LAYER M4 ;
        RECT 0.048 7.008 0.240 7.032 ;
    END
  END di[264]
  PIN di[265]
    DIRECTION INOUT ;
    USE SIGNAL ;
    PORT
      LAYER M4 ;
        RECT 0.048 7.104 0.240 7.128 ;
    END
  END di[265]
  PIN di[266]
    DIRECTION INOUT ;
    USE SIGNAL ;
    PORT
      LAYER M4 ;
        RECT 0.048 7.200 0.240 7.224 ;
    END
  END di[266]
  PIN di[267]
    DIRECTION INOUT ;
    USE SIGNAL ;
    PORT
      LAYER M4 ;
        RECT 0.048 7.296 0.240 7.320 ;
    END
  END di[267]
  PIN di[268]
    DIRECTION INOUT ;
    USE SIGNAL ;
    PORT
      LAYER M4 ;
        RECT 0.048 7.392 0.240 7.416 ;
    END
  END di[268]
  PIN di[269]
    DIRECTION INOUT ;
    USE SIGNAL ;
    PORT
      LAYER M4 ;
        RECT 0.048 7.488 0.240 7.512 ;
    END
  END di[269]
  PIN di[270]
    DIRECTION INOUT ;
    USE SIGNAL ;
    PORT
      LAYER M4 ;
        RECT 0.048 7.584 0.240 7.608 ;
    END
  END di[270]
  PIN di[271]
    DIRECTION INOUT ;
    USE SIGNAL ;
    PORT
      LAYER M4 ;
        RECT 0.048 7.680 0.240 7.704 ;
    END
  END di[271]
  PIN di[272]
    DIRECTION INOUT ;
    USE SIGNAL ;
    PORT
      LAYER M4 ;
        RECT 0.048 7.776 0.240 7.800 ;
    END
  END di[272]
  PIN di[273]
    DIRECTION INOUT ;
    USE SIGNAL ;
    PORT
      LAYER M4 ;
        RECT 0.048 7.872 0.240 7.896 ;
    END
  END di[273]
  PIN di[274]
    DIRECTION INOUT ;
    USE SIGNAL ;
    PORT
      LAYER M4 ;
        RECT 0.048 7.968 0.240 7.992 ;
    END
  END di[274]
  PIN di[275]
    DIRECTION INOUT ;
    USE SIGNAL ;
    PORT
      LAYER M4 ;
        RECT 0.048 8.064 0.240 8.088 ;
    END
  END di[275]
  PIN dq[0]
    DIRECTION INOUT ;
    USE SIGNAL ;
    PORT
      LAYER M4 ;
        RECT 17.016 21.408 17.208 21.432 ;
    END
  END dq[0]
  PIN dq[1]
    DIRECTION INOUT ;
    USE SIGNAL ;
    PORT
      LAYER M4 ;
        RECT 17.016 21.504 17.208 21.528 ;
    END
  END dq[1]
  PIN dq[2]
    DIRECTION INOUT ;
    USE SIGNAL ;
    PORT
      LAYER M4 ;
        RECT 17.016 21.600 17.208 21.624 ;
    END
  END dq[2]
  PIN dq[3]
    DIRECTION INOUT ;
    USE SIGNAL ;
    PORT
      LAYER M4 ;
        RECT 17.016 21.696 17.208 21.720 ;
    END
  END dq[3]
  PIN dq[4]
    DIRECTION INOUT ;
    USE SIGNAL ;
    PORT
      LAYER M4 ;
        RECT 17.016 21.792 17.208 21.816 ;
    END
  END dq[4]
  PIN dq[5]
    DIRECTION INOUT ;
    USE SIGNAL ;
    PORT
      LAYER M4 ;
        RECT 17.016 21.888 17.208 21.912 ;
    END
  END dq[5]
  PIN dq[6]
    DIRECTION INOUT ;
    USE SIGNAL ;
    PORT
      LAYER M4 ;
        RECT 17.016 21.984 17.208 22.008 ;
    END
  END dq[6]
  PIN dq[7]
    DIRECTION INOUT ;
    USE SIGNAL ;
    PORT
      LAYER M4 ;
        RECT 17.016 22.080 17.208 22.104 ;
    END
  END dq[7]
  PIN dq[8]
    DIRECTION INOUT ;
    USE SIGNAL ;
    PORT
      LAYER M4 ;
        RECT 17.016 22.176 17.208 22.200 ;
    END
  END dq[8]
  PIN dq[9]
    DIRECTION INOUT ;
    USE SIGNAL ;
    PORT
      LAYER M4 ;
        RECT 17.016 22.272 17.208 22.296 ;
    END
  END dq[9]
  PIN dq[10]
    DIRECTION INOUT ;
    USE SIGNAL ;
    PORT
      LAYER M4 ;
        RECT 17.016 22.368 17.208 22.392 ;
    END
  END dq[10]
  PIN dq[11]
    DIRECTION INOUT ;
    USE SIGNAL ;
    PORT
      LAYER M4 ;
        RECT 17.016 22.464 17.208 22.488 ;
    END
  END dq[11]
  PIN dq[12]
    DIRECTION INOUT ;
    USE SIGNAL ;
    PORT
      LAYER M4 ;
        RECT 17.016 22.560 17.208 22.584 ;
    END
  END dq[12]
  PIN dq[13]
    DIRECTION INOUT ;
    USE SIGNAL ;
    PORT
      LAYER M4 ;
        RECT 17.016 22.656 17.208 22.680 ;
    END
  END dq[13]
  PIN dq[14]
    DIRECTION INOUT ;
    USE SIGNAL ;
    PORT
      LAYER M4 ;
        RECT 17.016 22.752 17.208 22.776 ;
    END
  END dq[14]
  PIN dq[15]
    DIRECTION INOUT ;
    USE SIGNAL ;
    PORT
      LAYER M4 ;
        RECT 17.016 22.848 17.208 22.872 ;
    END
  END dq[15]
  PIN dq[16]
    DIRECTION INOUT ;
    USE SIGNAL ;
    PORT
      LAYER M4 ;
        RECT 17.016 22.944 17.208 22.968 ;
    END
  END dq[16]
  PIN dq[17]
    DIRECTION INOUT ;
    USE SIGNAL ;
    PORT
      LAYER M4 ;
        RECT 17.016 23.040 17.208 23.064 ;
    END
  END dq[17]
  PIN dq[18]
    DIRECTION INOUT ;
    USE SIGNAL ;
    PORT
      LAYER M4 ;
        RECT 17.016 23.136 17.208 23.160 ;
    END
  END dq[18]
  PIN dq[19]
    DIRECTION INOUT ;
    USE SIGNAL ;
    PORT
      LAYER M4 ;
        RECT 17.016 23.232 17.208 23.256 ;
    END
  END dq[19]
  PIN dq[20]
    DIRECTION INOUT ;
    USE SIGNAL ;
    PORT
      LAYER M4 ;
        RECT 17.016 23.328 17.208 23.352 ;
    END
  END dq[20]
  PIN dq[21]
    DIRECTION INOUT ;
    USE SIGNAL ;
    PORT
      LAYER M4 ;
        RECT 17.016 23.424 17.208 23.448 ;
    END
  END dq[21]
  PIN dq[22]
    DIRECTION INOUT ;
    USE SIGNAL ;
    PORT
      LAYER M4 ;
        RECT 17.016 23.520 17.208 23.544 ;
    END
  END dq[22]
  PIN dq[23]
    DIRECTION INOUT ;
    USE SIGNAL ;
    PORT
      LAYER M4 ;
        RECT 17.016 23.616 17.208 23.640 ;
    END
  END dq[23]
  PIN dq[24]
    DIRECTION INOUT ;
    USE SIGNAL ;
    PORT
      LAYER M4 ;
        RECT 17.016 23.712 17.208 23.736 ;
    END
  END dq[24]
  PIN dq[25]
    DIRECTION INOUT ;
    USE SIGNAL ;
    PORT
      LAYER M4 ;
        RECT 17.016 23.808 17.208 23.832 ;
    END
  END dq[25]
  PIN dq[26]
    DIRECTION INOUT ;
    USE SIGNAL ;
    PORT
      LAYER M4 ;
        RECT 17.016 23.904 17.208 23.928 ;
    END
  END dq[26]
  PIN dq[27]
    DIRECTION INOUT ;
    USE SIGNAL ;
    PORT
      LAYER M4 ;
        RECT 17.016 24.000 17.208 24.024 ;
    END
  END dq[27]
  PIN dq[28]
    DIRECTION INOUT ;
    USE SIGNAL ;
    PORT
      LAYER M4 ;
        RECT 17.016 24.096 17.208 24.120 ;
    END
  END dq[28]
  PIN dq[29]
    DIRECTION INOUT ;
    USE SIGNAL ;
    PORT
      LAYER M4 ;
        RECT 17.016 24.192 17.208 24.216 ;
    END
  END dq[29]
  PIN dq[30]
    DIRECTION INOUT ;
    USE SIGNAL ;
    PORT
      LAYER M4 ;
        RECT 17.016 24.288 17.208 24.312 ;
    END
  END dq[30]
  PIN dq[31]
    DIRECTION INOUT ;
    USE SIGNAL ;
    PORT
      LAYER M4 ;
        RECT 17.016 24.384 17.208 24.408 ;
    END
  END dq[31]
  PIN dq[32]
    DIRECTION INOUT ;
    USE SIGNAL ;
    PORT
      LAYER M4 ;
        RECT 17.016 24.480 17.208 24.504 ;
    END
  END dq[32]
  PIN dq[33]
    DIRECTION INOUT ;
    USE SIGNAL ;
    PORT
      LAYER M4 ;
        RECT 17.016 24.576 17.208 24.600 ;
    END
  END dq[33]
  PIN dq[34]
    DIRECTION INOUT ;
    USE SIGNAL ;
    PORT
      LAYER M4 ;
        RECT 17.016 24.672 17.208 24.696 ;
    END
  END dq[34]
  PIN dq[35]
    DIRECTION INOUT ;
    USE SIGNAL ;
    PORT
      LAYER M4 ;
        RECT 17.016 24.768 17.208 24.792 ;
    END
  END dq[35]
  PIN dq[36]
    DIRECTION INOUT ;
    USE SIGNAL ;
    PORT
      LAYER M4 ;
        RECT 17.016 24.864 17.208 24.888 ;
    END
  END dq[36]
  PIN dq[37]
    DIRECTION INOUT ;
    USE SIGNAL ;
    PORT
      LAYER M4 ;
        RECT 17.016 24.960 17.208 24.984 ;
    END
  END dq[37]
  PIN dq[38]
    DIRECTION INOUT ;
    USE SIGNAL ;
    PORT
      LAYER M4 ;
        RECT 17.016 25.056 17.208 25.080 ;
    END
  END dq[38]
  PIN dq[39]
    DIRECTION INOUT ;
    USE SIGNAL ;
    PORT
      LAYER M4 ;
        RECT 17.016 25.152 17.208 25.176 ;
    END
  END dq[39]
  PIN dq[40]
    DIRECTION INOUT ;
    USE SIGNAL ;
    PORT
      LAYER M4 ;
        RECT 17.016 25.248 17.208 25.272 ;
    END
  END dq[40]
  PIN dq[41]
    DIRECTION INOUT ;
    USE SIGNAL ;
    PORT
      LAYER M4 ;
        RECT 17.016 25.344 17.208 25.368 ;
    END
  END dq[41]
  PIN dq[42]
    DIRECTION INOUT ;
    USE SIGNAL ;
    PORT
      LAYER M4 ;
        RECT 17.016 25.440 17.208 25.464 ;
    END
  END dq[42]
  PIN dq[43]
    DIRECTION INOUT ;
    USE SIGNAL ;
    PORT
      LAYER M4 ;
        RECT 17.016 25.536 17.208 25.560 ;
    END
  END dq[43]
  PIN dq[44]
    DIRECTION INOUT ;
    USE SIGNAL ;
    PORT
      LAYER M4 ;
        RECT 17.016 25.632 17.208 25.656 ;
    END
  END dq[44]
  PIN dq[45]
    DIRECTION INOUT ;
    USE SIGNAL ;
    PORT
      LAYER M4 ;
        RECT 17.016 25.728 17.208 25.752 ;
    END
  END dq[45]
  PIN dq[46]
    DIRECTION INOUT ;
    USE SIGNAL ;
    PORT
      LAYER M4 ;
        RECT 17.016 25.824 17.208 25.848 ;
    END
  END dq[46]
  PIN dq[47]
    DIRECTION INOUT ;
    USE SIGNAL ;
    PORT
      LAYER M4 ;
        RECT 17.016 25.920 17.208 25.944 ;
    END
  END dq[47]
  PIN dq[48]
    DIRECTION INOUT ;
    USE SIGNAL ;
    PORT
      LAYER M4 ;
        RECT 17.016 26.016 17.208 26.040 ;
    END
  END dq[48]
  PIN dq[49]
    DIRECTION INOUT ;
    USE SIGNAL ;
    PORT
      LAYER M4 ;
        RECT 17.016 26.112 17.208 26.136 ;
    END
  END dq[49]
  PIN dq[50]
    DIRECTION INOUT ;
    USE SIGNAL ;
    PORT
      LAYER M4 ;
        RECT 17.016 26.208 17.208 26.232 ;
    END
  END dq[50]
  PIN dq[51]
    DIRECTION INOUT ;
    USE SIGNAL ;
    PORT
      LAYER M4 ;
        RECT 17.016 26.304 17.208 26.328 ;
    END
  END dq[51]
  PIN dq[52]
    DIRECTION INOUT ;
    USE SIGNAL ;
    PORT
      LAYER M4 ;
        RECT 17.016 26.400 17.208 26.424 ;
    END
  END dq[52]
  PIN dq[53]
    DIRECTION INOUT ;
    USE SIGNAL ;
    PORT
      LAYER M4 ;
        RECT 17.016 26.496 17.208 26.520 ;
    END
  END dq[53]
  PIN dq[54]
    DIRECTION INOUT ;
    USE SIGNAL ;
    PORT
      LAYER M4 ;
        RECT 17.016 26.592 17.208 26.616 ;
    END
  END dq[54]
  PIN dq[55]
    DIRECTION INOUT ;
    USE SIGNAL ;
    PORT
      LAYER M4 ;
        RECT 17.016 26.688 17.208 26.712 ;
    END
  END dq[55]
  PIN dq[56]
    DIRECTION INOUT ;
    USE SIGNAL ;
    PORT
      LAYER M4 ;
        RECT 17.016 26.784 17.208 26.808 ;
    END
  END dq[56]
  PIN dq[57]
    DIRECTION INOUT ;
    USE SIGNAL ;
    PORT
      LAYER M4 ;
        RECT 17.016 26.880 17.208 26.904 ;
    END
  END dq[57]
  PIN dq[58]
    DIRECTION INOUT ;
    USE SIGNAL ;
    PORT
      LAYER M4 ;
        RECT 17.016 26.976 17.208 27.000 ;
    END
  END dq[58]
  PIN dq[59]
    DIRECTION INOUT ;
    USE SIGNAL ;
    PORT
      LAYER M4 ;
        RECT 17.016 27.072 17.208 27.096 ;
    END
  END dq[59]
  PIN dq[60]
    DIRECTION INOUT ;
    USE SIGNAL ;
    PORT
      LAYER M4 ;
        RECT 17.016 27.168 17.208 27.192 ;
    END
  END dq[60]
  PIN dq[61]
    DIRECTION INOUT ;
    USE SIGNAL ;
    PORT
      LAYER M4 ;
        RECT 17.016 27.264 17.208 27.288 ;
    END
  END dq[61]
  PIN dq[62]
    DIRECTION INOUT ;
    USE SIGNAL ;
    PORT
      LAYER M4 ;
        RECT 17.016 27.360 17.208 27.384 ;
    END
  END dq[62]
  PIN dq[63]
    DIRECTION INOUT ;
    USE SIGNAL ;
    PORT
      LAYER M4 ;
        RECT 17.016 27.456 17.208 27.480 ;
    END
  END dq[63]
  PIN dq[64]
    DIRECTION INOUT ;
    USE SIGNAL ;
    PORT
      LAYER M4 ;
        RECT 17.016 27.552 17.208 27.576 ;
    END
  END dq[64]
  PIN dq[65]
    DIRECTION INOUT ;
    USE SIGNAL ;
    PORT
      LAYER M4 ;
        RECT 17.016 27.648 17.208 27.672 ;
    END
  END dq[65]
  PIN dq[66]
    DIRECTION INOUT ;
    USE SIGNAL ;
    PORT
      LAYER M4 ;
        RECT 17.016 27.744 17.208 27.768 ;
    END
  END dq[66]
  PIN dq[67]
    DIRECTION INOUT ;
    USE SIGNAL ;
    PORT
      LAYER M4 ;
        RECT 17.016 27.840 17.208 27.864 ;
    END
  END dq[67]
  PIN dq[68]
    DIRECTION INOUT ;
    USE SIGNAL ;
    PORT
      LAYER M4 ;
        RECT 17.016 27.936 17.208 27.960 ;
    END
  END dq[68]
  PIN dq[69]
    DIRECTION INOUT ;
    USE SIGNAL ;
    PORT
      LAYER M4 ;
        RECT 17.016 14.784 17.208 14.808 ;
    END
  END dq[69]
  PIN dq[70]
    DIRECTION INOUT ;
    USE SIGNAL ;
    PORT
      LAYER M4 ;
        RECT 17.016 14.880 17.208 14.904 ;
    END
  END dq[70]
  PIN dq[71]
    DIRECTION INOUT ;
    USE SIGNAL ;
    PORT
      LAYER M4 ;
        RECT 17.016 14.976 17.208 15.000 ;
    END
  END dq[71]
  PIN dq[72]
    DIRECTION INOUT ;
    USE SIGNAL ;
    PORT
      LAYER M4 ;
        RECT 17.016 15.072 17.208 15.096 ;
    END
  END dq[72]
  PIN dq[73]
    DIRECTION INOUT ;
    USE SIGNAL ;
    PORT
      LAYER M4 ;
        RECT 17.016 15.168 17.208 15.192 ;
    END
  END dq[73]
  PIN dq[74]
    DIRECTION INOUT ;
    USE SIGNAL ;
    PORT
      LAYER M4 ;
        RECT 17.016 15.264 17.208 15.288 ;
    END
  END dq[74]
  PIN dq[75]
    DIRECTION INOUT ;
    USE SIGNAL ;
    PORT
      LAYER M4 ;
        RECT 17.016 15.360 17.208 15.384 ;
    END
  END dq[75]
  PIN dq[76]
    DIRECTION INOUT ;
    USE SIGNAL ;
    PORT
      LAYER M4 ;
        RECT 17.016 15.456 17.208 15.480 ;
    END
  END dq[76]
  PIN dq[77]
    DIRECTION INOUT ;
    USE SIGNAL ;
    PORT
      LAYER M4 ;
        RECT 17.016 15.552 17.208 15.576 ;
    END
  END dq[77]
  PIN dq[78]
    DIRECTION INOUT ;
    USE SIGNAL ;
    PORT
      LAYER M4 ;
        RECT 17.016 15.648 17.208 15.672 ;
    END
  END dq[78]
  PIN dq[79]
    DIRECTION INOUT ;
    USE SIGNAL ;
    PORT
      LAYER M4 ;
        RECT 17.016 15.744 17.208 15.768 ;
    END
  END dq[79]
  PIN dq[80]
    DIRECTION INOUT ;
    USE SIGNAL ;
    PORT
      LAYER M4 ;
        RECT 17.016 15.840 17.208 15.864 ;
    END
  END dq[80]
  PIN dq[81]
    DIRECTION INOUT ;
    USE SIGNAL ;
    PORT
      LAYER M4 ;
        RECT 17.016 15.936 17.208 15.960 ;
    END
  END dq[81]
  PIN dq[82]
    DIRECTION INOUT ;
    USE SIGNAL ;
    PORT
      LAYER M4 ;
        RECT 17.016 16.032 17.208 16.056 ;
    END
  END dq[82]
  PIN dq[83]
    DIRECTION INOUT ;
    USE SIGNAL ;
    PORT
      LAYER M4 ;
        RECT 17.016 16.128 17.208 16.152 ;
    END
  END dq[83]
  PIN dq[84]
    DIRECTION INOUT ;
    USE SIGNAL ;
    PORT
      LAYER M4 ;
        RECT 17.016 16.224 17.208 16.248 ;
    END
  END dq[84]
  PIN dq[85]
    DIRECTION INOUT ;
    USE SIGNAL ;
    PORT
      LAYER M4 ;
        RECT 17.016 16.320 17.208 16.344 ;
    END
  END dq[85]
  PIN dq[86]
    DIRECTION INOUT ;
    USE SIGNAL ;
    PORT
      LAYER M4 ;
        RECT 17.016 16.416 17.208 16.440 ;
    END
  END dq[86]
  PIN dq[87]
    DIRECTION INOUT ;
    USE SIGNAL ;
    PORT
      LAYER M4 ;
        RECT 17.016 16.512 17.208 16.536 ;
    END
  END dq[87]
  PIN dq[88]
    DIRECTION INOUT ;
    USE SIGNAL ;
    PORT
      LAYER M4 ;
        RECT 17.016 16.608 17.208 16.632 ;
    END
  END dq[88]
  PIN dq[89]
    DIRECTION INOUT ;
    USE SIGNAL ;
    PORT
      LAYER M4 ;
        RECT 17.016 16.704 17.208 16.728 ;
    END
  END dq[89]
  PIN dq[90]
    DIRECTION INOUT ;
    USE SIGNAL ;
    PORT
      LAYER M4 ;
        RECT 17.016 16.800 17.208 16.824 ;
    END
  END dq[90]
  PIN dq[91]
    DIRECTION INOUT ;
    USE SIGNAL ;
    PORT
      LAYER M4 ;
        RECT 17.016 16.896 17.208 16.920 ;
    END
  END dq[91]
  PIN dq[92]
    DIRECTION INOUT ;
    USE SIGNAL ;
    PORT
      LAYER M4 ;
        RECT 17.016 16.992 17.208 17.016 ;
    END
  END dq[92]
  PIN dq[93]
    DIRECTION INOUT ;
    USE SIGNAL ;
    PORT
      LAYER M4 ;
        RECT 17.016 17.088 17.208 17.112 ;
    END
  END dq[93]
  PIN dq[94]
    DIRECTION INOUT ;
    USE SIGNAL ;
    PORT
      LAYER M4 ;
        RECT 17.016 17.184 17.208 17.208 ;
    END
  END dq[94]
  PIN dq[95]
    DIRECTION INOUT ;
    USE SIGNAL ;
    PORT
      LAYER M4 ;
        RECT 17.016 17.280 17.208 17.304 ;
    END
  END dq[95]
  PIN dq[96]
    DIRECTION INOUT ;
    USE SIGNAL ;
    PORT
      LAYER M4 ;
        RECT 17.016 17.376 17.208 17.400 ;
    END
  END dq[96]
  PIN dq[97]
    DIRECTION INOUT ;
    USE SIGNAL ;
    PORT
      LAYER M4 ;
        RECT 17.016 17.472 17.208 17.496 ;
    END
  END dq[97]
  PIN dq[98]
    DIRECTION INOUT ;
    USE SIGNAL ;
    PORT
      LAYER M4 ;
        RECT 17.016 17.568 17.208 17.592 ;
    END
  END dq[98]
  PIN dq[99]
    DIRECTION INOUT ;
    USE SIGNAL ;
    PORT
      LAYER M4 ;
        RECT 17.016 17.664 17.208 17.688 ;
    END
  END dq[99]
  PIN dq[100]
    DIRECTION INOUT ;
    USE SIGNAL ;
    PORT
      LAYER M4 ;
        RECT 17.016 17.760 17.208 17.784 ;
    END
  END dq[100]
  PIN dq[101]
    DIRECTION INOUT ;
    USE SIGNAL ;
    PORT
      LAYER M4 ;
        RECT 17.016 17.856 17.208 17.880 ;
    END
  END dq[101]
  PIN dq[102]
    DIRECTION INOUT ;
    USE SIGNAL ;
    PORT
      LAYER M4 ;
        RECT 17.016 17.952 17.208 17.976 ;
    END
  END dq[102]
  PIN dq[103]
    DIRECTION INOUT ;
    USE SIGNAL ;
    PORT
      LAYER M4 ;
        RECT 17.016 18.048 17.208 18.072 ;
    END
  END dq[103]
  PIN dq[104]
    DIRECTION INOUT ;
    USE SIGNAL ;
    PORT
      LAYER M4 ;
        RECT 17.016 18.144 17.208 18.168 ;
    END
  END dq[104]
  PIN dq[105]
    DIRECTION INOUT ;
    USE SIGNAL ;
    PORT
      LAYER M4 ;
        RECT 17.016 18.240 17.208 18.264 ;
    END
  END dq[105]
  PIN dq[106]
    DIRECTION INOUT ;
    USE SIGNAL ;
    PORT
      LAYER M4 ;
        RECT 17.016 18.336 17.208 18.360 ;
    END
  END dq[106]
  PIN dq[107]
    DIRECTION INOUT ;
    USE SIGNAL ;
    PORT
      LAYER M4 ;
        RECT 17.016 18.432 17.208 18.456 ;
    END
  END dq[107]
  PIN dq[108]
    DIRECTION INOUT ;
    USE SIGNAL ;
    PORT
      LAYER M4 ;
        RECT 17.016 18.528 17.208 18.552 ;
    END
  END dq[108]
  PIN dq[109]
    DIRECTION INOUT ;
    USE SIGNAL ;
    PORT
      LAYER M4 ;
        RECT 17.016 18.624 17.208 18.648 ;
    END
  END dq[109]
  PIN dq[110]
    DIRECTION INOUT ;
    USE SIGNAL ;
    PORT
      LAYER M4 ;
        RECT 17.016 18.720 17.208 18.744 ;
    END
  END dq[110]
  PIN dq[111]
    DIRECTION INOUT ;
    USE SIGNAL ;
    PORT
      LAYER M4 ;
        RECT 17.016 18.816 17.208 18.840 ;
    END
  END dq[111]
  PIN dq[112]
    DIRECTION INOUT ;
    USE SIGNAL ;
    PORT
      LAYER M4 ;
        RECT 17.016 18.912 17.208 18.936 ;
    END
  END dq[112]
  PIN dq[113]
    DIRECTION INOUT ;
    USE SIGNAL ;
    PORT
      LAYER M4 ;
        RECT 17.016 19.008 17.208 19.032 ;
    END
  END dq[113]
  PIN dq[114]
    DIRECTION INOUT ;
    USE SIGNAL ;
    PORT
      LAYER M4 ;
        RECT 17.016 19.104 17.208 19.128 ;
    END
  END dq[114]
  PIN dq[115]
    DIRECTION INOUT ;
    USE SIGNAL ;
    PORT
      LAYER M4 ;
        RECT 17.016 19.200 17.208 19.224 ;
    END
  END dq[115]
  PIN dq[116]
    DIRECTION INOUT ;
    USE SIGNAL ;
    PORT
      LAYER M4 ;
        RECT 17.016 19.296 17.208 19.320 ;
    END
  END dq[116]
  PIN dq[117]
    DIRECTION INOUT ;
    USE SIGNAL ;
    PORT
      LAYER M4 ;
        RECT 17.016 19.392 17.208 19.416 ;
    END
  END dq[117]
  PIN dq[118]
    DIRECTION INOUT ;
    USE SIGNAL ;
    PORT
      LAYER M4 ;
        RECT 17.016 19.488 17.208 19.512 ;
    END
  END dq[118]
  PIN dq[119]
    DIRECTION INOUT ;
    USE SIGNAL ;
    PORT
      LAYER M4 ;
        RECT 17.016 19.584 17.208 19.608 ;
    END
  END dq[119]
  PIN dq[120]
    DIRECTION INOUT ;
    USE SIGNAL ;
    PORT
      LAYER M4 ;
        RECT 17.016 19.680 17.208 19.704 ;
    END
  END dq[120]
  PIN dq[121]
    DIRECTION INOUT ;
    USE SIGNAL ;
    PORT
      LAYER M4 ;
        RECT 17.016 19.776 17.208 19.800 ;
    END
  END dq[121]
  PIN dq[122]
    DIRECTION INOUT ;
    USE SIGNAL ;
    PORT
      LAYER M4 ;
        RECT 17.016 19.872 17.208 19.896 ;
    END
  END dq[122]
  PIN dq[123]
    DIRECTION INOUT ;
    USE SIGNAL ;
    PORT
      LAYER M4 ;
        RECT 17.016 19.968 17.208 19.992 ;
    END
  END dq[123]
  PIN dq[124]
    DIRECTION INOUT ;
    USE SIGNAL ;
    PORT
      LAYER M4 ;
        RECT 17.016 20.064 17.208 20.088 ;
    END
  END dq[124]
  PIN dq[125]
    DIRECTION INOUT ;
    USE SIGNAL ;
    PORT
      LAYER M4 ;
        RECT 17.016 20.160 17.208 20.184 ;
    END
  END dq[125]
  PIN dq[126]
    DIRECTION INOUT ;
    USE SIGNAL ;
    PORT
      LAYER M4 ;
        RECT 17.016 20.256 17.208 20.280 ;
    END
  END dq[126]
  PIN dq[127]
    DIRECTION INOUT ;
    USE SIGNAL ;
    PORT
      LAYER M4 ;
        RECT 17.016 20.352 17.208 20.376 ;
    END
  END dq[127]
  PIN dq[128]
    DIRECTION INOUT ;
    USE SIGNAL ;
    PORT
      LAYER M4 ;
        RECT 17.016 20.448 17.208 20.472 ;
    END
  END dq[128]
  PIN dq[129]
    DIRECTION INOUT ;
    USE SIGNAL ;
    PORT
      LAYER M4 ;
        RECT 17.016 20.544 17.208 20.568 ;
    END
  END dq[129]
  PIN dq[130]
    DIRECTION INOUT ;
    USE SIGNAL ;
    PORT
      LAYER M4 ;
        RECT 17.016 20.640 17.208 20.664 ;
    END
  END dq[130]
  PIN dq[131]
    DIRECTION INOUT ;
    USE SIGNAL ;
    PORT
      LAYER M4 ;
        RECT 17.016 20.736 17.208 20.760 ;
    END
  END dq[131]
  PIN dq[132]
    DIRECTION INOUT ;
    USE SIGNAL ;
    PORT
      LAYER M4 ;
        RECT 17.016 20.832 17.208 20.856 ;
    END
  END dq[132]
  PIN dq[133]
    DIRECTION INOUT ;
    USE SIGNAL ;
    PORT
      LAYER M4 ;
        RECT 17.016 20.928 17.208 20.952 ;
    END
  END dq[133]
  PIN dq[134]
    DIRECTION INOUT ;
    USE SIGNAL ;
    PORT
      LAYER M4 ;
        RECT 17.016 21.024 17.208 21.048 ;
    END
  END dq[134]
  PIN dq[135]
    DIRECTION INOUT ;
    USE SIGNAL ;
    PORT
      LAYER M4 ;
        RECT 17.016 21.120 17.208 21.144 ;
    END
  END dq[135]
  PIN dq[136]
    DIRECTION INOUT ;
    USE SIGNAL ;
    PORT
      LAYER M4 ;
        RECT 17.016 21.216 17.208 21.240 ;
    END
  END dq[136]
  PIN dq[137]
    DIRECTION INOUT ;
    USE SIGNAL ;
    PORT
      LAYER M4 ;
        RECT 17.016 21.312 17.208 21.336 ;
    END
  END dq[137]
  PIN dq[138]
    DIRECTION INOUT ;
    USE SIGNAL ;
    PORT
      LAYER M4 ;
        RECT 17.016 8.160 17.208 8.184 ;
    END
  END dq[138]
  PIN dq[139]
    DIRECTION INOUT ;
    USE SIGNAL ;
    PORT
      LAYER M4 ;
        RECT 17.016 8.256 17.208 8.280 ;
    END
  END dq[139]
  PIN dq[140]
    DIRECTION INOUT ;
    USE SIGNAL ;
    PORT
      LAYER M4 ;
        RECT 17.016 8.352 17.208 8.376 ;
    END
  END dq[140]
  PIN dq[141]
    DIRECTION INOUT ;
    USE SIGNAL ;
    PORT
      LAYER M4 ;
        RECT 17.016 8.448 17.208 8.472 ;
    END
  END dq[141]
  PIN dq[142]
    DIRECTION INOUT ;
    USE SIGNAL ;
    PORT
      LAYER M4 ;
        RECT 17.016 8.544 17.208 8.568 ;
    END
  END dq[142]
  PIN dq[143]
    DIRECTION INOUT ;
    USE SIGNAL ;
    PORT
      LAYER M4 ;
        RECT 17.016 8.640 17.208 8.664 ;
    END
  END dq[143]
  PIN dq[144]
    DIRECTION INOUT ;
    USE SIGNAL ;
    PORT
      LAYER M4 ;
        RECT 17.016 8.736 17.208 8.760 ;
    END
  END dq[144]
  PIN dq[145]
    DIRECTION INOUT ;
    USE SIGNAL ;
    PORT
      LAYER M4 ;
        RECT 17.016 8.832 17.208 8.856 ;
    END
  END dq[145]
  PIN dq[146]
    DIRECTION INOUT ;
    USE SIGNAL ;
    PORT
      LAYER M4 ;
        RECT 17.016 8.928 17.208 8.952 ;
    END
  END dq[146]
  PIN dq[147]
    DIRECTION INOUT ;
    USE SIGNAL ;
    PORT
      LAYER M4 ;
        RECT 17.016 9.024 17.208 9.048 ;
    END
  END dq[147]
  PIN dq[148]
    DIRECTION INOUT ;
    USE SIGNAL ;
    PORT
      LAYER M4 ;
        RECT 17.016 9.120 17.208 9.144 ;
    END
  END dq[148]
  PIN dq[149]
    DIRECTION INOUT ;
    USE SIGNAL ;
    PORT
      LAYER M4 ;
        RECT 17.016 9.216 17.208 9.240 ;
    END
  END dq[149]
  PIN dq[150]
    DIRECTION INOUT ;
    USE SIGNAL ;
    PORT
      LAYER M4 ;
        RECT 17.016 9.312 17.208 9.336 ;
    END
  END dq[150]
  PIN dq[151]
    DIRECTION INOUT ;
    USE SIGNAL ;
    PORT
      LAYER M4 ;
        RECT 17.016 9.408 17.208 9.432 ;
    END
  END dq[151]
  PIN dq[152]
    DIRECTION INOUT ;
    USE SIGNAL ;
    PORT
      LAYER M4 ;
        RECT 17.016 9.504 17.208 9.528 ;
    END
  END dq[152]
  PIN dq[153]
    DIRECTION INOUT ;
    USE SIGNAL ;
    PORT
      LAYER M4 ;
        RECT 17.016 9.600 17.208 9.624 ;
    END
  END dq[153]
  PIN dq[154]
    DIRECTION INOUT ;
    USE SIGNAL ;
    PORT
      LAYER M4 ;
        RECT 17.016 9.696 17.208 9.720 ;
    END
  END dq[154]
  PIN dq[155]
    DIRECTION INOUT ;
    USE SIGNAL ;
    PORT
      LAYER M4 ;
        RECT 17.016 9.792 17.208 9.816 ;
    END
  END dq[155]
  PIN dq[156]
    DIRECTION INOUT ;
    USE SIGNAL ;
    PORT
      LAYER M4 ;
        RECT 17.016 9.888 17.208 9.912 ;
    END
  END dq[156]
  PIN dq[157]
    DIRECTION INOUT ;
    USE SIGNAL ;
    PORT
      LAYER M4 ;
        RECT 17.016 9.984 17.208 10.008 ;
    END
  END dq[157]
  PIN dq[158]
    DIRECTION INOUT ;
    USE SIGNAL ;
    PORT
      LAYER M4 ;
        RECT 17.016 10.080 17.208 10.104 ;
    END
  END dq[158]
  PIN dq[159]
    DIRECTION INOUT ;
    USE SIGNAL ;
    PORT
      LAYER M4 ;
        RECT 17.016 10.176 17.208 10.200 ;
    END
  END dq[159]
  PIN dq[160]
    DIRECTION INOUT ;
    USE SIGNAL ;
    PORT
      LAYER M4 ;
        RECT 17.016 10.272 17.208 10.296 ;
    END
  END dq[160]
  PIN dq[161]
    DIRECTION INOUT ;
    USE SIGNAL ;
    PORT
      LAYER M4 ;
        RECT 17.016 10.368 17.208 10.392 ;
    END
  END dq[161]
  PIN dq[162]
    DIRECTION INOUT ;
    USE SIGNAL ;
    PORT
      LAYER M4 ;
        RECT 17.016 10.464 17.208 10.488 ;
    END
  END dq[162]
  PIN dq[163]
    DIRECTION INOUT ;
    USE SIGNAL ;
    PORT
      LAYER M4 ;
        RECT 17.016 10.560 17.208 10.584 ;
    END
  END dq[163]
  PIN dq[164]
    DIRECTION INOUT ;
    USE SIGNAL ;
    PORT
      LAYER M4 ;
        RECT 17.016 10.656 17.208 10.680 ;
    END
  END dq[164]
  PIN dq[165]
    DIRECTION INOUT ;
    USE SIGNAL ;
    PORT
      LAYER M4 ;
        RECT 17.016 10.752 17.208 10.776 ;
    END
  END dq[165]
  PIN dq[166]
    DIRECTION INOUT ;
    USE SIGNAL ;
    PORT
      LAYER M4 ;
        RECT 17.016 10.848 17.208 10.872 ;
    END
  END dq[166]
  PIN dq[167]
    DIRECTION INOUT ;
    USE SIGNAL ;
    PORT
      LAYER M4 ;
        RECT 17.016 10.944 17.208 10.968 ;
    END
  END dq[167]
  PIN dq[168]
    DIRECTION INOUT ;
    USE SIGNAL ;
    PORT
      LAYER M4 ;
        RECT 17.016 11.040 17.208 11.064 ;
    END
  END dq[168]
  PIN dq[169]
    DIRECTION INOUT ;
    USE SIGNAL ;
    PORT
      LAYER M4 ;
        RECT 17.016 11.136 17.208 11.160 ;
    END
  END dq[169]
  PIN dq[170]
    DIRECTION INOUT ;
    USE SIGNAL ;
    PORT
      LAYER M4 ;
        RECT 17.016 11.232 17.208 11.256 ;
    END
  END dq[170]
  PIN dq[171]
    DIRECTION INOUT ;
    USE SIGNAL ;
    PORT
      LAYER M4 ;
        RECT 17.016 11.328 17.208 11.352 ;
    END
  END dq[171]
  PIN dq[172]
    DIRECTION INOUT ;
    USE SIGNAL ;
    PORT
      LAYER M4 ;
        RECT 17.016 11.424 17.208 11.448 ;
    END
  END dq[172]
  PIN dq[173]
    DIRECTION INOUT ;
    USE SIGNAL ;
    PORT
      LAYER M4 ;
        RECT 17.016 11.520 17.208 11.544 ;
    END
  END dq[173]
  PIN dq[174]
    DIRECTION INOUT ;
    USE SIGNAL ;
    PORT
      LAYER M4 ;
        RECT 17.016 11.616 17.208 11.640 ;
    END
  END dq[174]
  PIN dq[175]
    DIRECTION INOUT ;
    USE SIGNAL ;
    PORT
      LAYER M4 ;
        RECT 17.016 11.712 17.208 11.736 ;
    END
  END dq[175]
  PIN dq[176]
    DIRECTION INOUT ;
    USE SIGNAL ;
    PORT
      LAYER M4 ;
        RECT 17.016 11.808 17.208 11.832 ;
    END
  END dq[176]
  PIN dq[177]
    DIRECTION INOUT ;
    USE SIGNAL ;
    PORT
      LAYER M4 ;
        RECT 17.016 11.904 17.208 11.928 ;
    END
  END dq[177]
  PIN dq[178]
    DIRECTION INOUT ;
    USE SIGNAL ;
    PORT
      LAYER M4 ;
        RECT 17.016 12.000 17.208 12.024 ;
    END
  END dq[178]
  PIN dq[179]
    DIRECTION INOUT ;
    USE SIGNAL ;
    PORT
      LAYER M4 ;
        RECT 17.016 12.096 17.208 12.120 ;
    END
  END dq[179]
  PIN dq[180]
    DIRECTION INOUT ;
    USE SIGNAL ;
    PORT
      LAYER M4 ;
        RECT 17.016 12.192 17.208 12.216 ;
    END
  END dq[180]
  PIN dq[181]
    DIRECTION INOUT ;
    USE SIGNAL ;
    PORT
      LAYER M4 ;
        RECT 17.016 12.288 17.208 12.312 ;
    END
  END dq[181]
  PIN dq[182]
    DIRECTION INOUT ;
    USE SIGNAL ;
    PORT
      LAYER M4 ;
        RECT 17.016 12.384 17.208 12.408 ;
    END
  END dq[182]
  PIN dq[183]
    DIRECTION INOUT ;
    USE SIGNAL ;
    PORT
      LAYER M4 ;
        RECT 17.016 12.480 17.208 12.504 ;
    END
  END dq[183]
  PIN dq[184]
    DIRECTION INOUT ;
    USE SIGNAL ;
    PORT
      LAYER M4 ;
        RECT 17.016 12.576 17.208 12.600 ;
    END
  END dq[184]
  PIN dq[185]
    DIRECTION INOUT ;
    USE SIGNAL ;
    PORT
      LAYER M4 ;
        RECT 17.016 12.672 17.208 12.696 ;
    END
  END dq[185]
  PIN dq[186]
    DIRECTION INOUT ;
    USE SIGNAL ;
    PORT
      LAYER M4 ;
        RECT 17.016 12.768 17.208 12.792 ;
    END
  END dq[186]
  PIN dq[187]
    DIRECTION INOUT ;
    USE SIGNAL ;
    PORT
      LAYER M4 ;
        RECT 17.016 12.864 17.208 12.888 ;
    END
  END dq[187]
  PIN dq[188]
    DIRECTION INOUT ;
    USE SIGNAL ;
    PORT
      LAYER M4 ;
        RECT 17.016 12.960 17.208 12.984 ;
    END
  END dq[188]
  PIN dq[189]
    DIRECTION INOUT ;
    USE SIGNAL ;
    PORT
      LAYER M4 ;
        RECT 17.016 13.056 17.208 13.080 ;
    END
  END dq[189]
  PIN dq[190]
    DIRECTION INOUT ;
    USE SIGNAL ;
    PORT
      LAYER M4 ;
        RECT 17.016 13.152 17.208 13.176 ;
    END
  END dq[190]
  PIN dq[191]
    DIRECTION INOUT ;
    USE SIGNAL ;
    PORT
      LAYER M4 ;
        RECT 17.016 13.248 17.208 13.272 ;
    END
  END dq[191]
  PIN dq[192]
    DIRECTION INOUT ;
    USE SIGNAL ;
    PORT
      LAYER M4 ;
        RECT 17.016 13.344 17.208 13.368 ;
    END
  END dq[192]
  PIN dq[193]
    DIRECTION INOUT ;
    USE SIGNAL ;
    PORT
      LAYER M4 ;
        RECT 17.016 13.440 17.208 13.464 ;
    END
  END dq[193]
  PIN dq[194]
    DIRECTION INOUT ;
    USE SIGNAL ;
    PORT
      LAYER M4 ;
        RECT 17.016 13.536 17.208 13.560 ;
    END
  END dq[194]
  PIN dq[195]
    DIRECTION INOUT ;
    USE SIGNAL ;
    PORT
      LAYER M4 ;
        RECT 17.016 13.632 17.208 13.656 ;
    END
  END dq[195]
  PIN dq[196]
    DIRECTION INOUT ;
    USE SIGNAL ;
    PORT
      LAYER M4 ;
        RECT 17.016 13.728 17.208 13.752 ;
    END
  END dq[196]
  PIN dq[197]
    DIRECTION INOUT ;
    USE SIGNAL ;
    PORT
      LAYER M4 ;
        RECT 17.016 13.824 17.208 13.848 ;
    END
  END dq[197]
  PIN dq[198]
    DIRECTION INOUT ;
    USE SIGNAL ;
    PORT
      LAYER M4 ;
        RECT 17.016 13.920 17.208 13.944 ;
    END
  END dq[198]
  PIN dq[199]
    DIRECTION INOUT ;
    USE SIGNAL ;
    PORT
      LAYER M4 ;
        RECT 17.016 14.016 17.208 14.040 ;
    END
  END dq[199]
  PIN dq[200]
    DIRECTION INOUT ;
    USE SIGNAL ;
    PORT
      LAYER M4 ;
        RECT 17.016 14.112 17.208 14.136 ;
    END
  END dq[200]
  PIN dq[201]
    DIRECTION INOUT ;
    USE SIGNAL ;
    PORT
      LAYER M4 ;
        RECT 17.016 14.208 17.208 14.232 ;
    END
  END dq[201]
  PIN dq[202]
    DIRECTION INOUT ;
    USE SIGNAL ;
    PORT
      LAYER M4 ;
        RECT 17.016 14.304 17.208 14.328 ;
    END
  END dq[202]
  PIN dq[203]
    DIRECTION INOUT ;
    USE SIGNAL ;
    PORT
      LAYER M4 ;
        RECT 17.016 14.400 17.208 14.424 ;
    END
  END dq[203]
  PIN dq[204]
    DIRECTION INOUT ;
    USE SIGNAL ;
    PORT
      LAYER M4 ;
        RECT 17.016 14.496 17.208 14.520 ;
    END
  END dq[204]
  PIN dq[205]
    DIRECTION INOUT ;
    USE SIGNAL ;
    PORT
      LAYER M4 ;
        RECT 17.016 14.592 17.208 14.616 ;
    END
  END dq[205]
  PIN dq[206]
    DIRECTION INOUT ;
    USE SIGNAL ;
    PORT
      LAYER M4 ;
        RECT 17.016 14.688 17.208 14.712 ;
    END
  END dq[206]
  PIN dq[207]
    DIRECTION INOUT ;
    USE SIGNAL ;
    PORT
      LAYER M4 ;
        RECT 17.016 1.536 17.208 1.560 ;
    END
  END dq[207]
  PIN dq[208]
    DIRECTION INOUT ;
    USE SIGNAL ;
    PORT
      LAYER M4 ;
        RECT 17.016 1.632 17.208 1.656 ;
    END
  END dq[208]
  PIN dq[209]
    DIRECTION INOUT ;
    USE SIGNAL ;
    PORT
      LAYER M4 ;
        RECT 17.016 1.728 17.208 1.752 ;
    END
  END dq[209]
  PIN dq[210]
    DIRECTION INOUT ;
    USE SIGNAL ;
    PORT
      LAYER M4 ;
        RECT 17.016 1.824 17.208 1.848 ;
    END
  END dq[210]
  PIN dq[211]
    DIRECTION INOUT ;
    USE SIGNAL ;
    PORT
      LAYER M4 ;
        RECT 17.016 1.920 17.208 1.944 ;
    END
  END dq[211]
  PIN dq[212]
    DIRECTION INOUT ;
    USE SIGNAL ;
    PORT
      LAYER M4 ;
        RECT 17.016 2.016 17.208 2.040 ;
    END
  END dq[212]
  PIN dq[213]
    DIRECTION INOUT ;
    USE SIGNAL ;
    PORT
      LAYER M4 ;
        RECT 17.016 2.112 17.208 2.136 ;
    END
  END dq[213]
  PIN dq[214]
    DIRECTION INOUT ;
    USE SIGNAL ;
    PORT
      LAYER M4 ;
        RECT 17.016 2.208 17.208 2.232 ;
    END
  END dq[214]
  PIN dq[215]
    DIRECTION INOUT ;
    USE SIGNAL ;
    PORT
      LAYER M4 ;
        RECT 17.016 2.304 17.208 2.328 ;
    END
  END dq[215]
  PIN dq[216]
    DIRECTION INOUT ;
    USE SIGNAL ;
    PORT
      LAYER M4 ;
        RECT 17.016 2.400 17.208 2.424 ;
    END
  END dq[216]
  PIN dq[217]
    DIRECTION INOUT ;
    USE SIGNAL ;
    PORT
      LAYER M4 ;
        RECT 17.016 2.496 17.208 2.520 ;
    END
  END dq[217]
  PIN dq[218]
    DIRECTION INOUT ;
    USE SIGNAL ;
    PORT
      LAYER M4 ;
        RECT 17.016 2.592 17.208 2.616 ;
    END
  END dq[218]
  PIN dq[219]
    DIRECTION INOUT ;
    USE SIGNAL ;
    PORT
      LAYER M4 ;
        RECT 17.016 2.688 17.208 2.712 ;
    END
  END dq[219]
  PIN dq[220]
    DIRECTION INOUT ;
    USE SIGNAL ;
    PORT
      LAYER M4 ;
        RECT 17.016 2.784 17.208 2.808 ;
    END
  END dq[220]
  PIN dq[221]
    DIRECTION INOUT ;
    USE SIGNAL ;
    PORT
      LAYER M4 ;
        RECT 17.016 2.880 17.208 2.904 ;
    END
  END dq[221]
  PIN dq[222]
    DIRECTION INOUT ;
    USE SIGNAL ;
    PORT
      LAYER M4 ;
        RECT 17.016 2.976 17.208 3.000 ;
    END
  END dq[222]
  PIN dq[223]
    DIRECTION INOUT ;
    USE SIGNAL ;
    PORT
      LAYER M4 ;
        RECT 17.016 3.072 17.208 3.096 ;
    END
  END dq[223]
  PIN dq[224]
    DIRECTION INOUT ;
    USE SIGNAL ;
    PORT
      LAYER M4 ;
        RECT 17.016 3.168 17.208 3.192 ;
    END
  END dq[224]
  PIN dq[225]
    DIRECTION INOUT ;
    USE SIGNAL ;
    PORT
      LAYER M4 ;
        RECT 17.016 3.264 17.208 3.288 ;
    END
  END dq[225]
  PIN dq[226]
    DIRECTION INOUT ;
    USE SIGNAL ;
    PORT
      LAYER M4 ;
        RECT 17.016 3.360 17.208 3.384 ;
    END
  END dq[226]
  PIN dq[227]
    DIRECTION INOUT ;
    USE SIGNAL ;
    PORT
      LAYER M4 ;
        RECT 17.016 3.456 17.208 3.480 ;
    END
  END dq[227]
  PIN dq[228]
    DIRECTION INOUT ;
    USE SIGNAL ;
    PORT
      LAYER M4 ;
        RECT 17.016 3.552 17.208 3.576 ;
    END
  END dq[228]
  PIN dq[229]
    DIRECTION INOUT ;
    USE SIGNAL ;
    PORT
      LAYER M4 ;
        RECT 17.016 3.648 17.208 3.672 ;
    END
  END dq[229]
  PIN dq[230]
    DIRECTION INOUT ;
    USE SIGNAL ;
    PORT
      LAYER M4 ;
        RECT 17.016 3.744 17.208 3.768 ;
    END
  END dq[230]
  PIN dq[231]
    DIRECTION INOUT ;
    USE SIGNAL ;
    PORT
      LAYER M4 ;
        RECT 17.016 3.840 17.208 3.864 ;
    END
  END dq[231]
  PIN dq[232]
    DIRECTION INOUT ;
    USE SIGNAL ;
    PORT
      LAYER M4 ;
        RECT 17.016 3.936 17.208 3.960 ;
    END
  END dq[232]
  PIN dq[233]
    DIRECTION INOUT ;
    USE SIGNAL ;
    PORT
      LAYER M4 ;
        RECT 17.016 4.032 17.208 4.056 ;
    END
  END dq[233]
  PIN dq[234]
    DIRECTION INOUT ;
    USE SIGNAL ;
    PORT
      LAYER M4 ;
        RECT 17.016 4.128 17.208 4.152 ;
    END
  END dq[234]
  PIN dq[235]
    DIRECTION INOUT ;
    USE SIGNAL ;
    PORT
      LAYER M4 ;
        RECT 17.016 4.224 17.208 4.248 ;
    END
  END dq[235]
  PIN dq[236]
    DIRECTION INOUT ;
    USE SIGNAL ;
    PORT
      LAYER M4 ;
        RECT 17.016 4.320 17.208 4.344 ;
    END
  END dq[236]
  PIN dq[237]
    DIRECTION INOUT ;
    USE SIGNAL ;
    PORT
      LAYER M4 ;
        RECT 17.016 4.416 17.208 4.440 ;
    END
  END dq[237]
  PIN dq[238]
    DIRECTION INOUT ;
    USE SIGNAL ;
    PORT
      LAYER M4 ;
        RECT 17.016 4.512 17.208 4.536 ;
    END
  END dq[238]
  PIN dq[239]
    DIRECTION INOUT ;
    USE SIGNAL ;
    PORT
      LAYER M4 ;
        RECT 17.016 4.608 17.208 4.632 ;
    END
  END dq[239]
  PIN dq[240]
    DIRECTION INOUT ;
    USE SIGNAL ;
    PORT
      LAYER M4 ;
        RECT 17.016 4.704 17.208 4.728 ;
    END
  END dq[240]
  PIN dq[241]
    DIRECTION INOUT ;
    USE SIGNAL ;
    PORT
      LAYER M4 ;
        RECT 17.016 4.800 17.208 4.824 ;
    END
  END dq[241]
  PIN dq[242]
    DIRECTION INOUT ;
    USE SIGNAL ;
    PORT
      LAYER M4 ;
        RECT 17.016 4.896 17.208 4.920 ;
    END
  END dq[242]
  PIN dq[243]
    DIRECTION INOUT ;
    USE SIGNAL ;
    PORT
      LAYER M4 ;
        RECT 17.016 4.992 17.208 5.016 ;
    END
  END dq[243]
  PIN dq[244]
    DIRECTION INOUT ;
    USE SIGNAL ;
    PORT
      LAYER M4 ;
        RECT 17.016 5.088 17.208 5.112 ;
    END
  END dq[244]
  PIN dq[245]
    DIRECTION INOUT ;
    USE SIGNAL ;
    PORT
      LAYER M4 ;
        RECT 17.016 5.184 17.208 5.208 ;
    END
  END dq[245]
  PIN dq[246]
    DIRECTION INOUT ;
    USE SIGNAL ;
    PORT
      LAYER M4 ;
        RECT 17.016 5.280 17.208 5.304 ;
    END
  END dq[246]
  PIN dq[247]
    DIRECTION INOUT ;
    USE SIGNAL ;
    PORT
      LAYER M4 ;
        RECT 17.016 5.376 17.208 5.400 ;
    END
  END dq[247]
  PIN dq[248]
    DIRECTION INOUT ;
    USE SIGNAL ;
    PORT
      LAYER M4 ;
        RECT 17.016 5.472 17.208 5.496 ;
    END
  END dq[248]
  PIN dq[249]
    DIRECTION INOUT ;
    USE SIGNAL ;
    PORT
      LAYER M4 ;
        RECT 17.016 5.568 17.208 5.592 ;
    END
  END dq[249]
  PIN dq[250]
    DIRECTION INOUT ;
    USE SIGNAL ;
    PORT
      LAYER M4 ;
        RECT 17.016 5.664 17.208 5.688 ;
    END
  END dq[250]
  PIN dq[251]
    DIRECTION INOUT ;
    USE SIGNAL ;
    PORT
      LAYER M4 ;
        RECT 17.016 5.760 17.208 5.784 ;
    END
  END dq[251]
  PIN dq[252]
    DIRECTION INOUT ;
    USE SIGNAL ;
    PORT
      LAYER M4 ;
        RECT 17.016 5.856 17.208 5.880 ;
    END
  END dq[252]
  PIN dq[253]
    DIRECTION INOUT ;
    USE SIGNAL ;
    PORT
      LAYER M4 ;
        RECT 17.016 5.952 17.208 5.976 ;
    END
  END dq[253]
  PIN dq[254]
    DIRECTION INOUT ;
    USE SIGNAL ;
    PORT
      LAYER M4 ;
        RECT 17.016 6.048 17.208 6.072 ;
    END
  END dq[254]
  PIN dq[255]
    DIRECTION INOUT ;
    USE SIGNAL ;
    PORT
      LAYER M4 ;
        RECT 17.016 6.144 17.208 6.168 ;
    END
  END dq[255]
  PIN dq[256]
    DIRECTION INOUT ;
    USE SIGNAL ;
    PORT
      LAYER M4 ;
        RECT 17.016 6.240 17.208 6.264 ;
    END
  END dq[256]
  PIN dq[257]
    DIRECTION INOUT ;
    USE SIGNAL ;
    PORT
      LAYER M4 ;
        RECT 17.016 6.336 17.208 6.360 ;
    END
  END dq[257]
  PIN dq[258]
    DIRECTION INOUT ;
    USE SIGNAL ;
    PORT
      LAYER M4 ;
        RECT 17.016 6.432 17.208 6.456 ;
    END
  END dq[258]
  PIN dq[259]
    DIRECTION INOUT ;
    USE SIGNAL ;
    PORT
      LAYER M4 ;
        RECT 17.016 6.528 17.208 6.552 ;
    END
  END dq[259]
  PIN dq[260]
    DIRECTION INOUT ;
    USE SIGNAL ;
    PORT
      LAYER M4 ;
        RECT 17.016 6.624 17.208 6.648 ;
    END
  END dq[260]
  PIN dq[261]
    DIRECTION INOUT ;
    USE SIGNAL ;
    PORT
      LAYER M4 ;
        RECT 17.016 6.720 17.208 6.744 ;
    END
  END dq[261]
  PIN dq[262]
    DIRECTION INOUT ;
    USE SIGNAL ;
    PORT
      LAYER M4 ;
        RECT 17.016 6.816 17.208 6.840 ;
    END
  END dq[262]
  PIN dq[263]
    DIRECTION INOUT ;
    USE SIGNAL ;
    PORT
      LAYER M4 ;
        RECT 17.016 6.912 17.208 6.936 ;
    END
  END dq[263]
  PIN dq[264]
    DIRECTION INOUT ;
    USE SIGNAL ;
    PORT
      LAYER M4 ;
        RECT 17.016 7.008 17.208 7.032 ;
    END
  END dq[264]
  PIN dq[265]
    DIRECTION INOUT ;
    USE SIGNAL ;
    PORT
      LAYER M4 ;
        RECT 17.016 7.104 17.208 7.128 ;
    END
  END dq[265]
  PIN dq[266]
    DIRECTION INOUT ;
    USE SIGNAL ;
    PORT
      LAYER M4 ;
        RECT 17.016 7.200 17.208 7.224 ;
    END
  END dq[266]
  PIN dq[267]
    DIRECTION INOUT ;
    USE SIGNAL ;
    PORT
      LAYER M4 ;
        RECT 17.016 7.296 17.208 7.320 ;
    END
  END dq[267]
  PIN dq[268]
    DIRECTION INOUT ;
    USE SIGNAL ;
    PORT
      LAYER M4 ;
        RECT 17.016 7.392 17.208 7.416 ;
    END
  END dq[268]
  PIN dq[269]
    DIRECTION INOUT ;
    USE SIGNAL ;
    PORT
      LAYER M4 ;
        RECT 17.016 7.488 17.208 7.512 ;
    END
  END dq[269]
  PIN dq[270]
    DIRECTION INOUT ;
    USE SIGNAL ;
    PORT
      LAYER M4 ;
        RECT 17.016 7.584 17.208 7.608 ;
    END
  END dq[270]
  PIN dq[271]
    DIRECTION INOUT ;
    USE SIGNAL ;
    PORT
      LAYER M4 ;
        RECT 17.016 7.680 17.208 7.704 ;
    END
  END dq[271]
  PIN dq[272]
    DIRECTION INOUT ;
    USE SIGNAL ;
    PORT
      LAYER M4 ;
        RECT 17.016 7.776 17.208 7.800 ;
    END
  END dq[272]
  PIN dq[273]
    DIRECTION INOUT ;
    USE SIGNAL ;
    PORT
      LAYER M4 ;
        RECT 17.016 7.872 17.208 7.896 ;
    END
  END dq[273]
  PIN dq[274]
    DIRECTION INOUT ;
    USE SIGNAL ;
    PORT
      LAYER M4 ;
        RECT 17.016 7.968 17.208 7.992 ;
    END
  END dq[274]
  PIN dq[275]
    DIRECTION INOUT ;
    USE SIGNAL ;
    PORT
      LAYER M4 ;
        RECT 17.016 8.064 17.208 8.088 ;
    END
  END dq[275]
  PIN ck[0]
    DIRECTION INOUT ;
    USE SIGNAL ;
    PORT
      LAYER M5 ;
        RECT 8.592 30.000 8.616 30.192 ;
    END
  END ck[0]
  OBS
    LAYER M1 ;
      RECT 0 0 17.256 30.240 ;
    LAYER M2 ;
      RECT 0 0 17.256 30.240 ;
    LAYER M3 ;
      RECT 0 0 17.256 30.240 ;
  END
END dsfd_hstnh_276_sp1

# tools/dsrom_s81_fulldie.py abstract: Banded real register stage
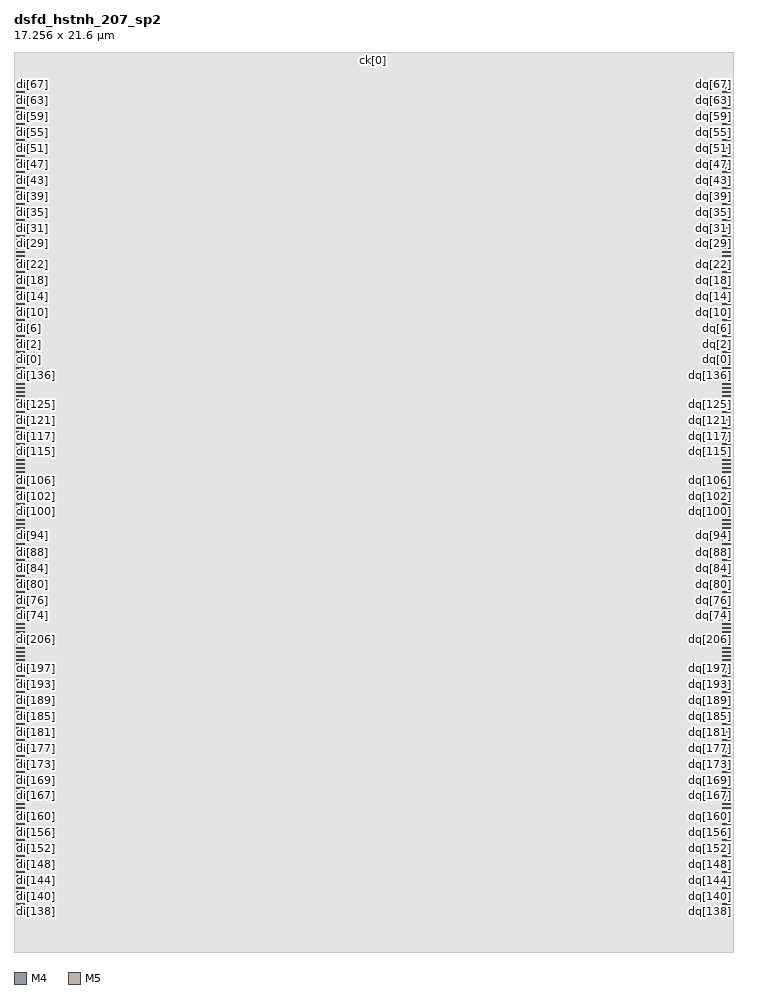
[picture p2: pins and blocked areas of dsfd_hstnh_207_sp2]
MACRO dsfd_hstnh_207_sp2
  CLASS BLOCK ;
  FOREIGN dsfd_hstnh_207_sp2 0 0 ;
  SIZE 17.256 BY 21.600 ;
  SYMMETRY X Y ;
  PIN di[0]
    DIRECTION INOUT ;
    USE SIGNAL ;
    PORT
      LAYER M4 ;
        RECT 0.048 14.208 0.240 14.232 ;
    END
  END di[0]
  PIN di[1]
    DIRECTION INOUT ;
    USE SIGNAL ;
    PORT
      LAYER M4 ;
        RECT 0.048 14.304 0.240 14.328 ;
    END
  END di[1]
  PIN di[2]
    DIRECTION INOUT ;
    USE SIGNAL ;
    PORT
      LAYER M4 ;
        RECT 0.048 14.400 0.240 14.424 ;
    END
  END di[2]
  PIN di[3]
    DIRECTION INOUT ;
    USE SIGNAL ;
    PORT
      LAYER M4 ;
        RECT 0.048 14.496 0.240 14.520 ;
    END
  END di[3]
  PIN di[4]
    DIRECTION INOUT ;
    USE SIGNAL ;
    PORT
      LAYER M4 ;
        RECT 0.048 14.592 0.240 14.616 ;
    END
  END di[4]
  PIN di[5]
    DIRECTION INOUT ;
    USE SIGNAL ;
    PORT
      LAYER M4 ;
        RECT 0.048 14.688 0.240 14.712 ;
    END
  END di[5]
  PIN di[6]
    DIRECTION INOUT ;
    USE SIGNAL ;
    PORT
      LAYER M4 ;
        RECT 0.048 14.784 0.240 14.808 ;
    END
  END di[6]
  PIN di[7]
    DIRECTION INOUT ;
    USE SIGNAL ;
    PORT
      LAYER M4 ;
        RECT 0.048 14.880 0.240 14.904 ;
    END
  END di[7]
  PIN di[8]
    DIRECTION INOUT ;
    USE SIGNAL ;
    PORT
      LAYER M4 ;
        RECT 0.048 14.976 0.240 15.000 ;
    END
  END di[8]
  PIN di[9]
    DIRECTION INOUT ;
    USE SIGNAL ;
    PORT
      LAYER M4 ;
        RECT 0.048 15.072 0.240 15.096 ;
    END
  END di[9]
  PIN di[10]
    DIRECTION INOUT ;
    USE SIGNAL ;
    PORT
      LAYER M4 ;
        RECT 0.048 15.168 0.240 15.192 ;
    END
  END di[10]
  PIN di[11]
    DIRECTION INOUT ;
    USE SIGNAL ;
    PORT
      LAYER M4 ;
        RECT 0.048 15.264 0.240 15.288 ;
    END
  END di[11]
  PIN di[12]
    DIRECTION INOUT ;
    USE SIGNAL ;
    PORT
      LAYER M4 ;
        RECT 0.048 15.360 0.240 15.384 ;
    END
  END di[12]
  PIN di[13]
    DIRECTION INOUT ;
    USE SIGNAL ;
    PORT
      LAYER M4 ;
        RECT 0.048 15.456 0.240 15.480 ;
    END
  END di[13]
  PIN di[14]
    DIRECTION INOUT ;
    USE SIGNAL ;
    PORT
      LAYER M4 ;
        RECT 0.048 15.552 0.240 15.576 ;
    END
  END di[14]
  PIN di[15]
    DIRECTION INOUT ;
    USE SIGNAL ;
    PORT
      LAYER M4 ;
        RECT 0.048 15.648 0.240 15.672 ;
    END
  END di[15]
  PIN di[16]
    DIRECTION INOUT ;
    USE SIGNAL ;
    PORT
      LAYER M4 ;
        RECT 0.048 15.744 0.240 15.768 ;
    END
  END di[16]
  PIN di[17]
    DIRECTION INOUT ;
    USE SIGNAL ;
    PORT
      LAYER M4 ;
        RECT 0.048 15.840 0.240 15.864 ;
    END
  END di[17]
  PIN di[18]
    DIRECTION INOUT ;
    USE SIGNAL ;
    PORT
      LAYER M4 ;
        RECT 0.048 15.936 0.240 15.960 ;
    END
  END di[18]
  PIN di[19]
    DIRECTION INOUT ;
    USE SIGNAL ;
    PORT
      LAYER M4 ;
        RECT 0.048 16.032 0.240 16.056 ;
    END
  END di[19]
  PIN di[20]
    DIRECTION INOUT ;
    USE SIGNAL ;
    PORT
      LAYER M4 ;
        RECT 0.048 16.128 0.240 16.152 ;
    END
  END di[20]
  PIN di[21]
    DIRECTION INOUT ;
    USE SIGNAL ;
    PORT
      LAYER M4 ;
        RECT 0.048 16.224 0.240 16.248 ;
    END
  END di[21]
  PIN di[22]
    DIRECTION INOUT ;
    USE SIGNAL ;
    PORT
      LAYER M4 ;
        RECT 0.048 16.320 0.240 16.344 ;
    END
  END di[22]
  PIN di[23]
    DIRECTION INOUT ;
    USE SIGNAL ;
    PORT
      LAYER M4 ;
        RECT 0.048 16.416 0.240 16.440 ;
    END
  END di[23]
  PIN di[24]
    DIRECTION INOUT ;
    USE SIGNAL ;
    PORT
      LAYER M4 ;
        RECT 0.048 16.512 0.240 16.536 ;
    END
  END di[24]
  PIN di[25]
    DIRECTION INOUT ;
    USE SIGNAL ;
    PORT
      LAYER M4 ;
        RECT 0.048 16.608 0.240 16.632 ;
    END
  END di[25]
  PIN di[26]
    DIRECTION INOUT ;
    USE SIGNAL ;
    PORT
      LAYER M4 ;
        RECT 0.048 16.704 0.240 16.728 ;
    END
  END di[26]
  PIN di[27]
    DIRECTION INOUT ;
    USE SIGNAL ;
    PORT
      LAYER M4 ;
        RECT 0.048 16.800 0.240 16.824 ;
    END
  END di[27]
  PIN di[28]
    DIRECTION INOUT ;
    USE SIGNAL ;
    PORT
      LAYER M4 ;
        RECT 0.048 16.896 0.240 16.920 ;
    END
  END di[28]
  PIN di[29]
    DIRECTION INOUT ;
    USE SIGNAL ;
    PORT
      LAYER M4 ;
        RECT 0.048 16.992 0.240 17.016 ;
    END
  END di[29]
  PIN di[30]
    DIRECTION INOUT ;
    USE SIGNAL ;
    PORT
      LAYER M4 ;
        RECT 0.048 17.088 0.240 17.112 ;
    END
  END di[30]
  PIN di[31]
    DIRECTION INOUT ;
    USE SIGNAL ;
    PORT
      LAYER M4 ;
        RECT 0.048 17.184 0.240 17.208 ;
    END
  END di[31]
  PIN di[32]
    DIRECTION INOUT ;
    USE SIGNAL ;
    PORT
      LAYER M4 ;
        RECT 0.048 17.280 0.240 17.304 ;
    END
  END di[32]
  PIN di[33]
    DIRECTION INOUT ;
    USE SIGNAL ;
    PORT
      LAYER M4 ;
        RECT 0.048 17.376 0.240 17.400 ;
    END
  END di[33]
  PIN di[34]
    DIRECTION INOUT ;
    USE SIGNAL ;
    PORT
      LAYER M4 ;
        RECT 0.048 17.472 0.240 17.496 ;
    END
  END di[34]
  PIN di[35]
    DIRECTION INOUT ;
    USE SIGNAL ;
    PORT
      LAYER M4 ;
        RECT 0.048 17.568 0.240 17.592 ;
    END
  END di[35]
  PIN di[36]
    DIRECTION INOUT ;
    USE SIGNAL ;
    PORT
      LAYER M4 ;
        RECT 0.048 17.664 0.240 17.688 ;
    END
  END di[36]
  PIN di[37]
    DIRECTION INOUT ;
    USE SIGNAL ;
    PORT
      LAYER M4 ;
        RECT 0.048 17.760 0.240 17.784 ;
    END
  END di[37]
  PIN di[38]
    DIRECTION INOUT ;
    USE SIGNAL ;
    PORT
      LAYER M4 ;
        RECT 0.048 17.856 0.240 17.880 ;
    END
  END di[38]
  PIN di[39]
    DIRECTION INOUT ;
    USE SIGNAL ;
    PORT
      LAYER M4 ;
        RECT 0.048 17.952 0.240 17.976 ;
    END
  END di[39]
  PIN di[40]
    DIRECTION INOUT ;
    USE SIGNAL ;
    PORT
      LAYER M4 ;
        RECT 0.048 18.048 0.240 18.072 ;
    END
  END di[40]
  PIN di[41]
    DIRECTION INOUT ;
    USE SIGNAL ;
    PORT
      LAYER M4 ;
        RECT 0.048 18.144 0.240 18.168 ;
    END
  END di[41]
  PIN di[42]
    DIRECTION INOUT ;
    USE SIGNAL ;
    PORT
      LAYER M4 ;
        RECT 0.048 18.240 0.240 18.264 ;
    END
  END di[42]
  PIN di[43]
    DIRECTION INOUT ;
    USE SIGNAL ;
    PORT
      LAYER M4 ;
        RECT 0.048 18.336 0.240 18.360 ;
    END
  END di[43]
  PIN di[44]
    DIRECTION INOUT ;
    USE SIGNAL ;
    PORT
      LAYER M4 ;
        RECT 0.048 18.432 0.240 18.456 ;
    END
  END di[44]
  PIN di[45]
    DIRECTION INOUT ;
    USE SIGNAL ;
    PORT
      LAYER M4 ;
        RECT 0.048 18.528 0.240 18.552 ;
    END
  END di[45]
  PIN di[46]
    DIRECTION INOUT ;
    USE SIGNAL ;
    PORT
      LAYER M4 ;
        RECT 0.048 18.624 0.240 18.648 ;
    END
  END di[46]
  PIN di[47]
    DIRECTION INOUT ;
    USE SIGNAL ;
    PORT
      LAYER M4 ;
        RECT 0.048 18.720 0.240 18.744 ;
    END
  END di[47]
  PIN di[48]
    DIRECTION INOUT ;
    USE SIGNAL ;
    PORT
      LAYER M4 ;
        RECT 0.048 18.816 0.240 18.840 ;
    END
  END di[48]
  PIN di[49]
    DIRECTION INOUT ;
    USE SIGNAL ;
    PORT
      LAYER M4 ;
        RECT 0.048 18.912 0.240 18.936 ;
    END
  END di[49]
  PIN di[50]
    DIRECTION INOUT ;
    USE SIGNAL ;
    PORT
      LAYER M4 ;
        RECT 0.048 19.008 0.240 19.032 ;
    END
  END di[50]
  PIN di[51]
    DIRECTION INOUT ;
    USE SIGNAL ;
    PORT
      LAYER M4 ;
        RECT 0.048 19.104 0.240 19.128 ;
    END
  END di[51]
  PIN di[52]
    DIRECTION INOUT ;
    USE SIGNAL ;
    PORT
      LAYER M4 ;
        RECT 0.048 19.200 0.240 19.224 ;
    END
  END di[52]
  PIN di[53]
    DIRECTION INOUT ;
    USE SIGNAL ;
    PORT
      LAYER M4 ;
        RECT 0.048 19.296 0.240 19.320 ;
    END
  END di[53]
  PIN di[54]
    DIRECTION INOUT ;
    USE SIGNAL ;
    PORT
      LAYER M4 ;
        RECT 0.048 19.392 0.240 19.416 ;
    END
  END di[54]
  PIN di[55]
    DIRECTION INOUT ;
    USE SIGNAL ;
    PORT
      LAYER M4 ;
        RECT 0.048 19.488 0.240 19.512 ;
    END
  END di[55]
  PIN di[56]
    DIRECTION INOUT ;
    USE SIGNAL ;
    PORT
      LAYER M4 ;
        RECT 0.048 19.584 0.240 19.608 ;
    END
  END di[56]
  PIN di[57]
    DIRECTION INOUT ;
    USE SIGNAL ;
    PORT
      LAYER M4 ;
        RECT 0.048 19.680 0.240 19.704 ;
    END
  END di[57]
  PIN di[58]
    DIRECTION INOUT ;
    USE SIGNAL ;
    PORT
      LAYER M4 ;
        RECT 0.048 19.776 0.240 19.800 ;
    END
  END di[58]
  PIN di[59]
    DIRECTION INOUT ;
    USE SIGNAL ;
    PORT
      LAYER M4 ;
        RECT 0.048 19.872 0.240 19.896 ;
    END
  END di[59]
  PIN di[60]
    DIRECTION INOUT ;
    USE SIGNAL ;
    PORT
      LAYER M4 ;
        RECT 0.048 19.968 0.240 19.992 ;
    END
  END di[60]
  PIN di[61]
    DIRECTION INOUT ;
    USE SIGNAL ;
    PORT
      LAYER M4 ;
        RECT 0.048 20.064 0.240 20.088 ;
    END
  END di[61]
  PIN di[62]
    DIRECTION INOUT ;
    USE SIGNAL ;
    PORT
      LAYER M4 ;
        RECT 0.048 20.160 0.240 20.184 ;
    END
  END di[62]
  PIN di[63]
    DIRECTION INOUT ;
    USE SIGNAL ;
    PORT
      LAYER M4 ;
        RECT 0.048 20.256 0.240 20.280 ;
    END
  END di[63]
  PIN di[64]
    DIRECTION INOUT ;
    USE SIGNAL ;
    PORT
      LAYER M4 ;
        RECT 0.048 20.352 0.240 20.376 ;
    END
  END di[64]
  PIN di[65]
    DIRECTION INOUT ;
    USE SIGNAL ;
    PORT
      LAYER M4 ;
        RECT 0.048 20.448 0.240 20.472 ;
    END
  END di[65]
  PIN di[66]
    DIRECTION INOUT ;
    USE SIGNAL ;
    PORT
      LAYER M4 ;
        RECT 0.048 20.544 0.240 20.568 ;
    END
  END di[66]
  PIN di[67]
    DIRECTION INOUT ;
    USE SIGNAL ;
    PORT
      LAYER M4 ;
        RECT 0.048 20.640 0.240 20.664 ;
    END
  END di[67]
  PIN di[68]
    DIRECTION INOUT ;
    USE SIGNAL ;
    PORT
      LAYER M4 ;
        RECT 0.048 20.736 0.240 20.760 ;
    END
  END di[68]
  PIN di[69]
    DIRECTION INOUT ;
    USE SIGNAL ;
    PORT
      LAYER M4 ;
        RECT 0.048 7.584 0.240 7.608 ;
    END
  END di[69]
  PIN di[70]
    DIRECTION INOUT ;
    USE SIGNAL ;
    PORT
      LAYER M4 ;
        RECT 0.048 7.680 0.240 7.704 ;
    END
  END di[70]
  PIN di[71]
    DIRECTION INOUT ;
    USE SIGNAL ;
    PORT
      LAYER M4 ;
        RECT 0.048 7.776 0.240 7.800 ;
    END
  END di[71]
  PIN di[72]
    DIRECTION INOUT ;
    USE SIGNAL ;
    PORT
      LAYER M4 ;
        RECT 0.048 7.872 0.240 7.896 ;
    END
  END di[72]
  PIN di[73]
    DIRECTION INOUT ;
    USE SIGNAL ;
    PORT
      LAYER M4 ;
        RECT 0.048 7.968 0.240 7.992 ;
    END
  END di[73]
  PIN di[74]
    DIRECTION INOUT ;
    USE SIGNAL ;
    PORT
      LAYER M4 ;
        RECT 0.048 8.064 0.240 8.088 ;
    END
  END di[74]
  PIN di[75]
    DIRECTION INOUT ;
    USE SIGNAL ;
    PORT
      LAYER M4 ;
        RECT 0.048 8.160 0.240 8.184 ;
    END
  END di[75]
  PIN di[76]
    DIRECTION INOUT ;
    USE SIGNAL ;
    PORT
      LAYER M4 ;
        RECT 0.048 8.256 0.240 8.280 ;
    END
  END di[76]
  PIN di[77]
    DIRECTION INOUT ;
    USE SIGNAL ;
    PORT
      LAYER M4 ;
        RECT 0.048 8.352 0.240 8.376 ;
    END
  END di[77]
  PIN di[78]
    DIRECTION INOUT ;
    USE SIGNAL ;
    PORT
      LAYER M4 ;
        RECT 0.048 8.448 0.240 8.472 ;
    END
  END di[78]
  PIN di[79]
    DIRECTION INOUT ;
    USE SIGNAL ;
    PORT
      LAYER M4 ;
        RECT 0.048 8.544 0.240 8.568 ;
    END
  END di[79]
  PIN di[80]
    DIRECTION INOUT ;
    USE SIGNAL ;
    PORT
      LAYER M4 ;
        RECT 0.048 8.640 0.240 8.664 ;
    END
  END di[80]
  PIN di[81]
    DIRECTION INOUT ;
    USE SIGNAL ;
    PORT
      LAYER M4 ;
        RECT 0.048 8.736 0.240 8.760 ;
    END
  END di[81]
  PIN di[82]
    DIRECTION INOUT ;
    USE SIGNAL ;
    PORT
      LAYER M4 ;
        RECT 0.048 8.832 0.240 8.856 ;
    END
  END di[82]
  PIN di[83]
    DIRECTION INOUT ;
    USE SIGNAL ;
    PORT
      LAYER M4 ;
        RECT 0.048 8.928 0.240 8.952 ;
    END
  END di[83]
  PIN di[84]
    DIRECTION INOUT ;
    USE SIGNAL ;
    PORT
      LAYER M4 ;
        RECT 0.048 9.024 0.240 9.048 ;
    END
  END di[84]
  PIN di[85]
    DIRECTION INOUT ;
    USE SIGNAL ;
    PORT
      LAYER M4 ;
        RECT 0.048 9.120 0.240 9.144 ;
    END
  END di[85]
  PIN di[86]
    DIRECTION INOUT ;
    USE SIGNAL ;
    PORT
      LAYER M4 ;
        RECT 0.048 9.216 0.240 9.240 ;
    END
  END di[86]
  PIN di[87]
    DIRECTION INOUT ;
    USE SIGNAL ;
    PORT
      LAYER M4 ;
        RECT 0.048 9.312 0.240 9.336 ;
    END
  END di[87]
  PIN di[88]
    DIRECTION INOUT ;
    USE SIGNAL ;
    PORT
      LAYER M4 ;
        RECT 0.048 9.408 0.240 9.432 ;
    END
  END di[88]
  PIN di[89]
    DIRECTION INOUT ;
    USE SIGNAL ;
    PORT
      LAYER M4 ;
        RECT 0.048 9.504 0.240 9.528 ;
    END
  END di[89]
  PIN di[90]
    DIRECTION INOUT ;
    USE SIGNAL ;
    PORT
      LAYER M4 ;
        RECT 0.048 9.600 0.240 9.624 ;
    END
  END di[90]
  PIN di[91]
    DIRECTION INOUT ;
    USE SIGNAL ;
    PORT
      LAYER M4 ;
        RECT 0.048 9.696 0.240 9.720 ;
    END
  END di[91]
  PIN di[92]
    DIRECTION INOUT ;
    USE SIGNAL ;
    PORT
      LAYER M4 ;
        RECT 0.048 9.792 0.240 9.816 ;
    END
  END di[92]
  PIN di[93]
    DIRECTION INOUT ;
    USE SIGNAL ;
    PORT
      LAYER M4 ;
        RECT 0.048 9.888 0.240 9.912 ;
    END
  END di[93]
  PIN di[94]
    DIRECTION INOUT ;
    USE SIGNAL ;
    PORT
      LAYER M4 ;
        RECT 0.048 9.984 0.240 10.008 ;
    END
  END di[94]
  PIN di[95]
    DIRECTION INOUT ;
    USE SIGNAL ;
    PORT
      LAYER M4 ;
        RECT 0.048 10.080 0.240 10.104 ;
    END
  END di[95]
  PIN di[96]
    DIRECTION INOUT ;
    USE SIGNAL ;
    PORT
      LAYER M4 ;
        RECT 0.048 10.176 0.240 10.200 ;
    END
  END di[96]
  PIN di[97]
    DIRECTION INOUT ;
    USE SIGNAL ;
    PORT
      LAYER M4 ;
        RECT 0.048 10.272 0.240 10.296 ;
    END
  END di[97]
  PIN di[98]
    DIRECTION INOUT ;
    USE SIGNAL ;
    PORT
      LAYER M4 ;
        RECT 0.048 10.368 0.240 10.392 ;
    END
  END di[98]
  PIN di[99]
    DIRECTION INOUT ;
    USE SIGNAL ;
    PORT
      LAYER M4 ;
        RECT 0.048 10.464 0.240 10.488 ;
    END
  END di[99]
  PIN di[100]
    DIRECTION INOUT ;
    USE SIGNAL ;
    PORT
      LAYER M4 ;
        RECT 0.048 10.560 0.240 10.584 ;
    END
  END di[100]
  PIN di[101]
    DIRECTION INOUT ;
    USE SIGNAL ;
    PORT
      LAYER M4 ;
        RECT 0.048 10.656 0.240 10.680 ;
    END
  END di[101]
  PIN di[102]
    DIRECTION INOUT ;
    USE SIGNAL ;
    PORT
      LAYER M4 ;
        RECT 0.048 10.752 0.240 10.776 ;
    END
  END di[102]
  PIN di[103]
    DIRECTION INOUT ;
    USE SIGNAL ;
    PORT
      LAYER M4 ;
        RECT 0.048 10.848 0.240 10.872 ;
    END
  END di[103]
  PIN di[104]
    DIRECTION INOUT ;
    USE SIGNAL ;
    PORT
      LAYER M4 ;
        RECT 0.048 10.944 0.240 10.968 ;
    END
  END di[104]
  PIN di[105]
    DIRECTION INOUT ;
    USE SIGNAL ;
    PORT
      LAYER M4 ;
        RECT 0.048 11.040 0.240 11.064 ;
    END
  END di[105]
  PIN di[106]
    DIRECTION INOUT ;
    USE SIGNAL ;
    PORT
      LAYER M4 ;
        RECT 0.048 11.136 0.240 11.160 ;
    END
  END di[106]
  PIN di[107]
    DIRECTION INOUT ;
    USE SIGNAL ;
    PORT
      LAYER M4 ;
        RECT 0.048 11.232 0.240 11.256 ;
    END
  END di[107]
  PIN di[108]
    DIRECTION INOUT ;
    USE SIGNAL ;
    PORT
      LAYER M4 ;
        RECT 0.048 11.328 0.240 11.352 ;
    END
  END di[108]
  PIN di[109]
    DIRECTION INOUT ;
    USE SIGNAL ;
    PORT
      LAYER M4 ;
        RECT 0.048 11.424 0.240 11.448 ;
    END
  END di[109]
  PIN di[110]
    DIRECTION INOUT ;
    USE SIGNAL ;
    PORT
      LAYER M4 ;
        RECT 0.048 11.520 0.240 11.544 ;
    END
  END di[110]
  PIN di[111]
    DIRECTION INOUT ;
    USE SIGNAL ;
    PORT
      LAYER M4 ;
        RECT 0.048 11.616 0.240 11.640 ;
    END
  END di[111]
  PIN di[112]
    DIRECTION INOUT ;
    USE SIGNAL ;
    PORT
      LAYER M4 ;
        RECT 0.048 11.712 0.240 11.736 ;
    END
  END di[112]
  PIN di[113]
    DIRECTION INOUT ;
    USE SIGNAL ;
    PORT
      LAYER M4 ;
        RECT 0.048 11.808 0.240 11.832 ;
    END
  END di[113]
  PIN di[114]
    DIRECTION INOUT ;
    USE SIGNAL ;
    PORT
      LAYER M4 ;
        RECT 0.048 11.904 0.240 11.928 ;
    END
  END di[114]
  PIN di[115]
    DIRECTION INOUT ;
    USE SIGNAL ;
    PORT
      LAYER M4 ;
        RECT 0.048 12.000 0.240 12.024 ;
    END
  END di[115]
  PIN di[116]
    DIRECTION INOUT ;
    USE SIGNAL ;
    PORT
      LAYER M4 ;
        RECT 0.048 12.096 0.240 12.120 ;
    END
  END di[116]
  PIN di[117]
    DIRECTION INOUT ;
    USE SIGNAL ;
    PORT
      LAYER M4 ;
        RECT 0.048 12.192 0.240 12.216 ;
    END
  END di[117]
  PIN di[118]
    DIRECTION INOUT ;
    USE SIGNAL ;
    PORT
      LAYER M4 ;
        RECT 0.048 12.288 0.240 12.312 ;
    END
  END di[118]
  PIN di[119]
    DIRECTION INOUT ;
    USE SIGNAL ;
    PORT
      LAYER M4 ;
        RECT 0.048 12.384 0.240 12.408 ;
    END
  END di[119]
  PIN di[120]
    DIRECTION INOUT ;
    USE SIGNAL ;
    PORT
      LAYER M4 ;
        RECT 0.048 12.480 0.240 12.504 ;
    END
  END di[120]
  PIN di[121]
    DIRECTION INOUT ;
    USE SIGNAL ;
    PORT
      LAYER M4 ;
        RECT 0.048 12.576 0.240 12.600 ;
    END
  END di[121]
  PIN di[122]
    DIRECTION INOUT ;
    USE SIGNAL ;
    PORT
      LAYER M4 ;
        RECT 0.048 12.672 0.240 12.696 ;
    END
  END di[122]
  PIN di[123]
    DIRECTION INOUT ;
    USE SIGNAL ;
    PORT
      LAYER M4 ;
        RECT 0.048 12.768 0.240 12.792 ;
    END
  END di[123]
  PIN di[124]
    DIRECTION INOUT ;
    USE SIGNAL ;
    PORT
      LAYER M4 ;
        RECT 0.048 12.864 0.240 12.888 ;
    END
  END di[124]
  PIN di[125]
    DIRECTION INOUT ;
    USE SIGNAL ;
    PORT
      LAYER M4 ;
        RECT 0.048 12.960 0.240 12.984 ;
    END
  END di[125]
  PIN di[126]
    DIRECTION INOUT ;
    USE SIGNAL ;
    PORT
      LAYER M4 ;
        RECT 0.048 13.056 0.240 13.080 ;
    END
  END di[126]
  PIN di[127]
    DIRECTION INOUT ;
    USE SIGNAL ;
    PORT
      LAYER M4 ;
        RECT 0.048 13.152 0.240 13.176 ;
    END
  END di[127]
  PIN di[128]
    DIRECTION INOUT ;
    USE SIGNAL ;
    PORT
      LAYER M4 ;
        RECT 0.048 13.248 0.240 13.272 ;
    END
  END di[128]
  PIN di[129]
    DIRECTION INOUT ;
    USE SIGNAL ;
    PORT
      LAYER M4 ;
        RECT 0.048 13.344 0.240 13.368 ;
    END
  END di[129]
  PIN di[130]
    DIRECTION INOUT ;
    USE SIGNAL ;
    PORT
      LAYER M4 ;
        RECT 0.048 13.440 0.240 13.464 ;
    END
  END di[130]
  PIN di[131]
    DIRECTION INOUT ;
    USE SIGNAL ;
    PORT
      LAYER M4 ;
        RECT 0.048 13.536 0.240 13.560 ;
    END
  END di[131]
  PIN di[132]
    DIRECTION INOUT ;
    USE SIGNAL ;
    PORT
      LAYER M4 ;
        RECT 0.048 13.632 0.240 13.656 ;
    END
  END di[132]
  PIN di[133]
    DIRECTION INOUT ;
    USE SIGNAL ;
    PORT
      LAYER M4 ;
        RECT 0.048 13.728 0.240 13.752 ;
    END
  END di[133]
  PIN di[134]
    DIRECTION INOUT ;
    USE SIGNAL ;
    PORT
      LAYER M4 ;
        RECT 0.048 13.824 0.240 13.848 ;
    END
  END di[134]
  PIN di[135]
    DIRECTION INOUT ;
    USE SIGNAL ;
    PORT
      LAYER M4 ;
        RECT 0.048 13.920 0.240 13.944 ;
    END
  END di[135]
  PIN di[136]
    DIRECTION INOUT ;
    USE SIGNAL ;
    PORT
      LAYER M4 ;
        RECT 0.048 14.016 0.240 14.040 ;
    END
  END di[136]
  PIN di[137]
    DIRECTION INOUT ;
    USE SIGNAL ;
    PORT
      LAYER M4 ;
        RECT 0.048 14.112 0.240 14.136 ;
    END
  END di[137]
  PIN di[138]
    DIRECTION INOUT ;
    USE SIGNAL ;
    PORT
      LAYER M4 ;
        RECT 0.048 0.960 0.240 0.984 ;
    END
  END di[138]
  PIN di[139]
    DIRECTION INOUT ;
    USE SIGNAL ;
    PORT
      LAYER M4 ;
        RECT 0.048 1.056 0.240 1.080 ;
    END
  END di[139]
  PIN di[140]
    DIRECTION INOUT ;
    USE SIGNAL ;
    PORT
      LAYER M4 ;
        RECT 0.048 1.152 0.240 1.176 ;
    END
  END di[140]
  PIN di[141]
    DIRECTION INOUT ;
    USE SIGNAL ;
    PORT
      LAYER M4 ;
        RECT 0.048 1.248 0.240 1.272 ;
    END
  END di[141]
  PIN di[142]
    DIRECTION INOUT ;
    USE SIGNAL ;
    PORT
      LAYER M4 ;
        RECT 0.048 1.344 0.240 1.368 ;
    END
  END di[142]
  PIN di[143]
    DIRECTION INOUT ;
    USE SIGNAL ;
    PORT
      LAYER M4 ;
        RECT 0.048 1.440 0.240 1.464 ;
    END
  END di[143]
  PIN di[144]
    DIRECTION INOUT ;
    USE SIGNAL ;
    PORT
      LAYER M4 ;
        RECT 0.048 1.536 0.240 1.560 ;
    END
  END di[144]
  PIN di[145]
    DIRECTION INOUT ;
    USE SIGNAL ;
    PORT
      LAYER M4 ;
        RECT 0.048 1.632 0.240 1.656 ;
    END
  END di[145]
  PIN di[146]
    DIRECTION INOUT ;
    USE SIGNAL ;
    PORT
      LAYER M4 ;
        RECT 0.048 1.728 0.240 1.752 ;
    END
  END di[146]
  PIN di[147]
    DIRECTION INOUT ;
    USE SIGNAL ;
    PORT
      LAYER M4 ;
        RECT 0.048 1.824 0.240 1.848 ;
    END
  END di[147]
  PIN di[148]
    DIRECTION INOUT ;
    USE SIGNAL ;
    PORT
      LAYER M4 ;
        RECT 0.048 1.920 0.240 1.944 ;
    END
  END di[148]
  PIN di[149]
    DIRECTION INOUT ;
    USE SIGNAL ;
    PORT
      LAYER M4 ;
        RECT 0.048 2.016 0.240 2.040 ;
    END
  END di[149]
  PIN di[150]
    DIRECTION INOUT ;
    USE SIGNAL ;
    PORT
      LAYER M4 ;
        RECT 0.048 2.112 0.240 2.136 ;
    END
  END di[150]
  PIN di[151]
    DIRECTION INOUT ;
    USE SIGNAL ;
    PORT
      LAYER M4 ;
        RECT 0.048 2.208 0.240 2.232 ;
    END
  END di[151]
  PIN di[152]
    DIRECTION INOUT ;
    USE SIGNAL ;
    PORT
      LAYER M4 ;
        RECT 0.048 2.304 0.240 2.328 ;
    END
  END di[152]
  PIN di[153]
    DIRECTION INOUT ;
    USE SIGNAL ;
    PORT
      LAYER M4 ;
        RECT 0.048 2.400 0.240 2.424 ;
    END
  END di[153]
  PIN di[154]
    DIRECTION INOUT ;
    USE SIGNAL ;
    PORT
      LAYER M4 ;
        RECT 0.048 2.496 0.240 2.520 ;
    END
  END di[154]
  PIN di[155]
    DIRECTION INOUT ;
    USE SIGNAL ;
    PORT
      LAYER M4 ;
        RECT 0.048 2.592 0.240 2.616 ;
    END
  END di[155]
  PIN di[156]
    DIRECTION INOUT ;
    USE SIGNAL ;
    PORT
      LAYER M4 ;
        RECT 0.048 2.688 0.240 2.712 ;
    END
  END di[156]
  PIN di[157]
    DIRECTION INOUT ;
    USE SIGNAL ;
    PORT
      LAYER M4 ;
        RECT 0.048 2.784 0.240 2.808 ;
    END
  END di[157]
  PIN di[158]
    DIRECTION INOUT ;
    USE SIGNAL ;
    PORT
      LAYER M4 ;
        RECT 0.048 2.880 0.240 2.904 ;
    END
  END di[158]
  PIN di[159]
    DIRECTION INOUT ;
    USE SIGNAL ;
    PORT
      LAYER M4 ;
        RECT 0.048 2.976 0.240 3.000 ;
    END
  END di[159]
  PIN di[160]
    DIRECTION INOUT ;
    USE SIGNAL ;
    PORT
      LAYER M4 ;
        RECT 0.048 3.072 0.240 3.096 ;
    END
  END di[160]
  PIN di[161]
    DIRECTION INOUT ;
    USE SIGNAL ;
    PORT
      LAYER M4 ;
        RECT 0.048 3.168 0.240 3.192 ;
    END
  END di[161]
  PIN di[162]
    DIRECTION INOUT ;
    USE SIGNAL ;
    PORT
      LAYER M4 ;
        RECT 0.048 3.264 0.240 3.288 ;
    END
  END di[162]
  PIN di[163]
    DIRECTION INOUT ;
    USE SIGNAL ;
    PORT
      LAYER M4 ;
        RECT 0.048 3.360 0.240 3.384 ;
    END
  END di[163]
  PIN di[164]
    DIRECTION INOUT ;
    USE SIGNAL ;
    PORT
      LAYER M4 ;
        RECT 0.048 3.456 0.240 3.480 ;
    END
  END di[164]
  PIN di[165]
    DIRECTION INOUT ;
    USE SIGNAL ;
    PORT
      LAYER M4 ;
        RECT 0.048 3.552 0.240 3.576 ;
    END
  END di[165]
  PIN di[166]
    DIRECTION INOUT ;
    USE SIGNAL ;
    PORT
      LAYER M4 ;
        RECT 0.048 3.648 0.240 3.672 ;
    END
  END di[166]
  PIN di[167]
    DIRECTION INOUT ;
    USE SIGNAL ;
    PORT
      LAYER M4 ;
        RECT 0.048 3.744 0.240 3.768 ;
    END
  END di[167]
  PIN di[168]
    DIRECTION INOUT ;
    USE SIGNAL ;
    PORT
      LAYER M4 ;
        RECT 0.048 3.840 0.240 3.864 ;
    END
  END di[168]
  PIN di[169]
    DIRECTION INOUT ;
    USE SIGNAL ;
    PORT
      LAYER M4 ;
        RECT 0.048 3.936 0.240 3.960 ;
    END
  END di[169]
  PIN di[170]
    DIRECTION INOUT ;
    USE SIGNAL ;
    PORT
      LAYER M4 ;
        RECT 0.048 4.032 0.240 4.056 ;
    END
  END di[170]
  PIN di[171]
    DIRECTION INOUT ;
    USE SIGNAL ;
    PORT
      LAYER M4 ;
        RECT 0.048 4.128 0.240 4.152 ;
    END
  END di[171]
  PIN di[172]
    DIRECTION INOUT ;
    USE SIGNAL ;
    PORT
      LAYER M4 ;
        RECT 0.048 4.224 0.240 4.248 ;
    END
  END di[172]
  PIN di[173]
    DIRECTION INOUT ;
    USE SIGNAL ;
    PORT
      LAYER M4 ;
        RECT 0.048 4.320 0.240 4.344 ;
    END
  END di[173]
  PIN di[174]
    DIRECTION INOUT ;
    USE SIGNAL ;
    PORT
      LAYER M4 ;
        RECT 0.048 4.416 0.240 4.440 ;
    END
  END di[174]
  PIN di[175]
    DIRECTION INOUT ;
    USE SIGNAL ;
    PORT
      LAYER M4 ;
        RECT 0.048 4.512 0.240 4.536 ;
    END
  END di[175]
  PIN di[176]
    DIRECTION INOUT ;
    USE SIGNAL ;
    PORT
      LAYER M4 ;
        RECT 0.048 4.608 0.240 4.632 ;
    END
  END di[176]
  PIN di[177]
    DIRECTION INOUT ;
    USE SIGNAL ;
    PORT
      LAYER M4 ;
        RECT 0.048 4.704 0.240 4.728 ;
    END
  END di[177]
  PIN di[178]
    DIRECTION INOUT ;
    USE SIGNAL ;
    PORT
      LAYER M4 ;
        RECT 0.048 4.800 0.240 4.824 ;
    END
  END di[178]
  PIN di[179]
    DIRECTION INOUT ;
    USE SIGNAL ;
    PORT
      LAYER M4 ;
        RECT 0.048 4.896 0.240 4.920 ;
    END
  END di[179]
  PIN di[180]
    DIRECTION INOUT ;
    USE SIGNAL ;
    PORT
      LAYER M4 ;
        RECT 0.048 4.992 0.240 5.016 ;
    END
  END di[180]
  PIN di[181]
    DIRECTION INOUT ;
    USE SIGNAL ;
    PORT
      LAYER M4 ;
        RECT 0.048 5.088 0.240 5.112 ;
    END
  END di[181]
  PIN di[182]
    DIRECTION INOUT ;
    USE SIGNAL ;
    PORT
      LAYER M4 ;
        RECT 0.048 5.184 0.240 5.208 ;
    END
  END di[182]
  PIN di[183]
    DIRECTION INOUT ;
    USE SIGNAL ;
    PORT
      LAYER M4 ;
        RECT 0.048 5.280 0.240 5.304 ;
    END
  END di[183]
  PIN di[184]
    DIRECTION INOUT ;
    USE SIGNAL ;
    PORT
      LAYER M4 ;
        RECT 0.048 5.376 0.240 5.400 ;
    END
  END di[184]
  PIN di[185]
    DIRECTION INOUT ;
    USE SIGNAL ;
    PORT
      LAYER M4 ;
        RECT 0.048 5.472 0.240 5.496 ;
    END
  END di[185]
  PIN di[186]
    DIRECTION INOUT ;
    USE SIGNAL ;
    PORT
      LAYER M4 ;
        RECT 0.048 5.568 0.240 5.592 ;
    END
  END di[186]
  PIN di[187]
    DIRECTION INOUT ;
    USE SIGNAL ;
    PORT
      LAYER M4 ;
        RECT 0.048 5.664 0.240 5.688 ;
    END
  END di[187]
  PIN di[188]
    DIRECTION INOUT ;
    USE SIGNAL ;
    PORT
      LAYER M4 ;
        RECT 0.048 5.760 0.240 5.784 ;
    END
  END di[188]
  PIN di[189]
    DIRECTION INOUT ;
    USE SIGNAL ;
    PORT
      LAYER M4 ;
        RECT 0.048 5.856 0.240 5.880 ;
    END
  END di[189]
  PIN di[190]
    DIRECTION INOUT ;
    USE SIGNAL ;
    PORT
      LAYER M4 ;
        RECT 0.048 5.952 0.240 5.976 ;
    END
  END di[190]
  PIN di[191]
    DIRECTION INOUT ;
    USE SIGNAL ;
    PORT
      LAYER M4 ;
        RECT 0.048 6.048 0.240 6.072 ;
    END
  END di[191]
  PIN di[192]
    DIRECTION INOUT ;
    USE SIGNAL ;
    PORT
      LAYER M4 ;
        RECT 0.048 6.144 0.240 6.168 ;
    END
  END di[192]
  PIN di[193]
    DIRECTION INOUT ;
    USE SIGNAL ;
    PORT
      LAYER M4 ;
        RECT 0.048 6.240 0.240 6.264 ;
    END
  END di[193]
  PIN di[194]
    DIRECTION INOUT ;
    USE SIGNAL ;
    PORT
      LAYER M4 ;
        RECT 0.048 6.336 0.240 6.360 ;
    END
  END di[194]
  PIN di[195]
    DIRECTION INOUT ;
    USE SIGNAL ;
    PORT
      LAYER M4 ;
        RECT 0.048 6.432 0.240 6.456 ;
    END
  END di[195]
  PIN di[196]
    DIRECTION INOUT ;
    USE SIGNAL ;
    PORT
      LAYER M4 ;
        RECT 0.048 6.528 0.240 6.552 ;
    END
  END di[196]
  PIN di[197]
    DIRECTION INOUT ;
    USE SIGNAL ;
    PORT
      LAYER M4 ;
        RECT 0.048 6.624 0.240 6.648 ;
    END
  END di[197]
  PIN di[198]
    DIRECTION INOUT ;
    USE SIGNAL ;
    PORT
      LAYER M4 ;
        RECT 0.048 6.720 0.240 6.744 ;
    END
  END di[198]
  PIN di[199]
    DIRECTION INOUT ;
    USE SIGNAL ;
    PORT
      LAYER M4 ;
        RECT 0.048 6.816 0.240 6.840 ;
    END
  END di[199]
  PIN di[200]
    DIRECTION INOUT ;
    USE SIGNAL ;
    PORT
      LAYER M4 ;
        RECT 0.048 6.912 0.240 6.936 ;
    END
  END di[200]
  PIN di[201]
    DIRECTION INOUT ;
    USE SIGNAL ;
    PORT
      LAYER M4 ;
        RECT 0.048 7.008 0.240 7.032 ;
    END
  END di[201]
  PIN di[202]
    DIRECTION INOUT ;
    USE SIGNAL ;
    PORT
      LAYER M4 ;
        RECT 0.048 7.104 0.240 7.128 ;
    END
  END di[202]
  PIN di[203]
    DIRECTION INOUT ;
    USE SIGNAL ;
    PORT
      LAYER M4 ;
        RECT 0.048 7.200 0.240 7.224 ;
    END
  END di[203]
  PIN di[204]
    DIRECTION INOUT ;
    USE SIGNAL ;
    PORT
      LAYER M4 ;
        RECT 0.048 7.296 0.240 7.320 ;
    END
  END di[204]
  PIN di[205]
    DIRECTION INOUT ;
    USE SIGNAL ;
    PORT
      LAYER M4 ;
        RECT 0.048 7.392 0.240 7.416 ;
    END
  END di[205]
  PIN di[206]
    DIRECTION INOUT ;
    USE SIGNAL ;
    PORT
      LAYER M4 ;
        RECT 0.048 7.488 0.240 7.512 ;
    END
  END di[206]
  PIN dq[0]
    DIRECTION INOUT ;
    USE SIGNAL ;
    PORT
      LAYER M4 ;
        RECT 17.016 14.208 17.208 14.232 ;
    END
  END dq[0]
  PIN dq[1]
    DIRECTION INOUT ;
    USE SIGNAL ;
    PORT
      LAYER M4 ;
        RECT 17.016 14.304 17.208 14.328 ;
    END
  END dq[1]
  PIN dq[2]
    DIRECTION INOUT ;
    USE SIGNAL ;
    PORT
      LAYER M4 ;
        RECT 17.016 14.400 17.208 14.424 ;
    END
  END dq[2]
  PIN dq[3]
    DIRECTION INOUT ;
    USE SIGNAL ;
    PORT
      LAYER M4 ;
        RECT 17.016 14.496 17.208 14.520 ;
    END
  END dq[3]
  PIN dq[4]
    DIRECTION INOUT ;
    USE SIGNAL ;
    PORT
      LAYER M4 ;
        RECT 17.016 14.592 17.208 14.616 ;
    END
  END dq[4]
  PIN dq[5]
    DIRECTION INOUT ;
    USE SIGNAL ;
    PORT
      LAYER M4 ;
        RECT 17.016 14.688 17.208 14.712 ;
    END
  END dq[5]
  PIN dq[6]
    DIRECTION INOUT ;
    USE SIGNAL ;
    PORT
      LAYER M4 ;
        RECT 17.016 14.784 17.208 14.808 ;
    END
  END dq[6]
  PIN dq[7]
    DIRECTION INOUT ;
    USE SIGNAL ;
    PORT
      LAYER M4 ;
        RECT 17.016 14.880 17.208 14.904 ;
    END
  END dq[7]
  PIN dq[8]
    DIRECTION INOUT ;
    USE SIGNAL ;
    PORT
      LAYER M4 ;
        RECT 17.016 14.976 17.208 15.000 ;
    END
  END dq[8]
  PIN dq[9]
    DIRECTION INOUT ;
    USE SIGNAL ;
    PORT
      LAYER M4 ;
        RECT 17.016 15.072 17.208 15.096 ;
    END
  END dq[9]
  PIN dq[10]
    DIRECTION INOUT ;
    USE SIGNAL ;
    PORT
      LAYER M4 ;
        RECT 17.016 15.168 17.208 15.192 ;
    END
  END dq[10]
  PIN dq[11]
    DIRECTION INOUT ;
    USE SIGNAL ;
    PORT
      LAYER M4 ;
        RECT 17.016 15.264 17.208 15.288 ;
    END
  END dq[11]
  PIN dq[12]
    DIRECTION INOUT ;
    USE SIGNAL ;
    PORT
      LAYER M4 ;
        RECT 17.016 15.360 17.208 15.384 ;
    END
  END dq[12]
  PIN dq[13]
    DIRECTION INOUT ;
    USE SIGNAL ;
    PORT
      LAYER M4 ;
        RECT 17.016 15.456 17.208 15.480 ;
    END
  END dq[13]
  PIN dq[14]
    DIRECTION INOUT ;
    USE SIGNAL ;
    PORT
      LAYER M4 ;
        RECT 17.016 15.552 17.208 15.576 ;
    END
  END dq[14]
  PIN dq[15]
    DIRECTION INOUT ;
    USE SIGNAL ;
    PORT
      LAYER M4 ;
        RECT 17.016 15.648 17.208 15.672 ;
    END
  END dq[15]
  PIN dq[16]
    DIRECTION INOUT ;
    USE SIGNAL ;
    PORT
      LAYER M4 ;
        RECT 17.016 15.744 17.208 15.768 ;
    END
  END dq[16]
  PIN dq[17]
    DIRECTION INOUT ;
    USE SIGNAL ;
    PORT
      LAYER M4 ;
        RECT 17.016 15.840 17.208 15.864 ;
    END
  END dq[17]
  PIN dq[18]
    DIRECTION INOUT ;
    USE SIGNAL ;
    PORT
      LAYER M4 ;
        RECT 17.016 15.936 17.208 15.960 ;
    END
  END dq[18]
  PIN dq[19]
    DIRECTION INOUT ;
    USE SIGNAL ;
    PORT
      LAYER M4 ;
        RECT 17.016 16.032 17.208 16.056 ;
    END
  END dq[19]
  PIN dq[20]
    DIRECTION INOUT ;
    USE SIGNAL ;
    PORT
      LAYER M4 ;
        RECT 17.016 16.128 17.208 16.152 ;
    END
  END dq[20]
  PIN dq[21]
    DIRECTION INOUT ;
    USE SIGNAL ;
    PORT
      LAYER M4 ;
        RECT 17.016 16.224 17.208 16.248 ;
    END
  END dq[21]
  PIN dq[22]
    DIRECTION INOUT ;
    USE SIGNAL ;
    PORT
      LAYER M4 ;
        RECT 17.016 16.320 17.208 16.344 ;
    END
  END dq[22]
  PIN dq[23]
    DIRECTION INOUT ;
    USE SIGNAL ;
    PORT
      LAYER M4 ;
        RECT 17.016 16.416 17.208 16.440 ;
    END
  END dq[23]
  PIN dq[24]
    DIRECTION INOUT ;
    USE SIGNAL ;
    PORT
      LAYER M4 ;
        RECT 17.016 16.512 17.208 16.536 ;
    END
  END dq[24]
  PIN dq[25]
    DIRECTION INOUT ;
    USE SIGNAL ;
    PORT
      LAYER M4 ;
        RECT 17.016 16.608 17.208 16.632 ;
    END
  END dq[25]
  PIN dq[26]
    DIRECTION INOUT ;
    USE SIGNAL ;
    PORT
      LAYER M4 ;
        RECT 17.016 16.704 17.208 16.728 ;
    END
  END dq[26]
  PIN dq[27]
    DIRECTION INOUT ;
    USE SIGNAL ;
    PORT
      LAYER M4 ;
        RECT 17.016 16.800 17.208 16.824 ;
    END
  END dq[27]
  PIN dq[28]
    DIRECTION INOUT ;
    USE SIGNAL ;
    PORT
      LAYER M4 ;
        RECT 17.016 16.896 17.208 16.920 ;
    END
  END dq[28]
  PIN dq[29]
    DIRECTION INOUT ;
    USE SIGNAL ;
    PORT
      LAYER M4 ;
        RECT 17.016 16.992 17.208 17.016 ;
    END
  END dq[29]
  PIN dq[30]
    DIRECTION INOUT ;
    USE SIGNAL ;
    PORT
      LAYER M4 ;
        RECT 17.016 17.088 17.208 17.112 ;
    END
  END dq[30]
  PIN dq[31]
    DIRECTION INOUT ;
    USE SIGNAL ;
    PORT
      LAYER M4 ;
        RECT 17.016 17.184 17.208 17.208 ;
    END
  END dq[31]
  PIN dq[32]
    DIRECTION INOUT ;
    USE SIGNAL ;
    PORT
      LAYER M4 ;
        RECT 17.016 17.280 17.208 17.304 ;
    END
  END dq[32]
  PIN dq[33]
    DIRECTION INOUT ;
    USE SIGNAL ;
    PORT
      LAYER M4 ;
        RECT 17.016 17.376 17.208 17.400 ;
    END
  END dq[33]
  PIN dq[34]
    DIRECTION INOUT ;
    USE SIGNAL ;
    PORT
      LAYER M4 ;
        RECT 17.016 17.472 17.208 17.496 ;
    END
  END dq[34]
  PIN dq[35]
    DIRECTION INOUT ;
    USE SIGNAL ;
    PORT
      LAYER M4 ;
        RECT 17.016 17.568 17.208 17.592 ;
    END
  END dq[35]
  PIN dq[36]
    DIRECTION INOUT ;
    USE SIGNAL ;
    PORT
      LAYER M4 ;
        RECT 17.016 17.664 17.208 17.688 ;
    END
  END dq[36]
  PIN dq[37]
    DIRECTION INOUT ;
    USE SIGNAL ;
    PORT
      LAYER M4 ;
        RECT 17.016 17.760 17.208 17.784 ;
    END
  END dq[37]
  PIN dq[38]
    DIRECTION INOUT ;
    USE SIGNAL ;
    PORT
      LAYER M4 ;
        RECT 17.016 17.856 17.208 17.880 ;
    END
  END dq[38]
  PIN dq[39]
    DIRECTION INOUT ;
    USE SIGNAL ;
    PORT
      LAYER M4 ;
        RECT 17.016 17.952 17.208 17.976 ;
    END
  END dq[39]
  PIN dq[40]
    DIRECTION INOUT ;
    USE SIGNAL ;
    PORT
      LAYER M4 ;
        RECT 17.016 18.048 17.208 18.072 ;
    END
  END dq[40]
  PIN dq[41]
    DIRECTION INOUT ;
    USE SIGNAL ;
    PORT
      LAYER M4 ;
        RECT 17.016 18.144 17.208 18.168 ;
    END
  END dq[41]
  PIN dq[42]
    DIRECTION INOUT ;
    USE SIGNAL ;
    PORT
      LAYER M4 ;
        RECT 17.016 18.240 17.208 18.264 ;
    END
  END dq[42]
  PIN dq[43]
    DIRECTION INOUT ;
    USE SIGNAL ;
    PORT
      LAYER M4 ;
        RECT 17.016 18.336 17.208 18.360 ;
    END
  END dq[43]
  PIN dq[44]
    DIRECTION INOUT ;
    USE SIGNAL ;
    PORT
      LAYER M4 ;
        RECT 17.016 18.432 17.208 18.456 ;
    END
  END dq[44]
  PIN dq[45]
    DIRECTION INOUT ;
    USE SIGNAL ;
    PORT
      LAYER M4 ;
        RECT 17.016 18.528 17.208 18.552 ;
    END
  END dq[45]
  PIN dq[46]
    DIRECTION INOUT ;
    USE SIGNAL ;
    PORT
      LAYER M4 ;
        RECT 17.016 18.624 17.208 18.648 ;
    END
  END dq[46]
  PIN dq[47]
    DIRECTION INOUT ;
    USE SIGNAL ;
    PORT
      LAYER M4 ;
        RECT 17.016 18.720 17.208 18.744 ;
    END
  END dq[47]
  PIN dq[48]
    DIRECTION INOUT ;
    USE SIGNAL ;
    PORT
      LAYER M4 ;
        RECT 17.016 18.816 17.208 18.840 ;
    END
  END dq[48]
  PIN dq[49]
    DIRECTION INOUT ;
    USE SIGNAL ;
    PORT
      LAYER M4 ;
        RECT 17.016 18.912 17.208 18.936 ;
    END
  END dq[49]
  PIN dq[50]
    DIRECTION INOUT ;
    USE SIGNAL ;
    PORT
      LAYER M4 ;
        RECT 17.016 19.008 17.208 19.032 ;
    END
  END dq[50]
  PIN dq[51]
    DIRECTION INOUT ;
    USE SIGNAL ;
    PORT
      LAYER M4 ;
        RECT 17.016 19.104 17.208 19.128 ;
    END
  END dq[51]
  PIN dq[52]
    DIRECTION INOUT ;
    USE SIGNAL ;
    PORT
      LAYER M4 ;
        RECT 17.016 19.200 17.208 19.224 ;
    END
  END dq[52]
  PIN dq[53]
    DIRECTION INOUT ;
    USE SIGNAL ;
    PORT
      LAYER M4 ;
        RECT 17.016 19.296 17.208 19.320 ;
    END
  END dq[53]
  PIN dq[54]
    DIRECTION INOUT ;
    USE SIGNAL ;
    PORT
      LAYER M4 ;
        RECT 17.016 19.392 17.208 19.416 ;
    END
  END dq[54]
  PIN dq[55]
    DIRECTION INOUT ;
    USE SIGNAL ;
    PORT
      LAYER M4 ;
        RECT 17.016 19.488 17.208 19.512 ;
    END
  END dq[55]
  PIN dq[56]
    DIRECTION INOUT ;
    USE SIGNAL ;
    PORT
      LAYER M4 ;
        RECT 17.016 19.584 17.208 19.608 ;
    END
  END dq[56]
  PIN dq[57]
    DIRECTION INOUT ;
    USE SIGNAL ;
    PORT
      LAYER M4 ;
        RECT 17.016 19.680 17.208 19.704 ;
    END
  END dq[57]
  PIN dq[58]
    DIRECTION INOUT ;
    USE SIGNAL ;
    PORT
      LAYER M4 ;
        RECT 17.016 19.776 17.208 19.800 ;
    END
  END dq[58]
  PIN dq[59]
    DIRECTION INOUT ;
    USE SIGNAL ;
    PORT
      LAYER M4 ;
        RECT 17.016 19.872 17.208 19.896 ;
    END
  END dq[59]
  PIN dq[60]
    DIRECTION INOUT ;
    USE SIGNAL ;
    PORT
      LAYER M4 ;
        RECT 17.016 19.968 17.208 19.992 ;
    END
  END dq[60]
  PIN dq[61]
    DIRECTION INOUT ;
    USE SIGNAL ;
    PORT
      LAYER M4 ;
        RECT 17.016 20.064 17.208 20.088 ;
    END
  END dq[61]
  PIN dq[62]
    DIRECTION INOUT ;
    USE SIGNAL ;
    PORT
      LAYER M4 ;
        RECT 17.016 20.160 17.208 20.184 ;
    END
  END dq[62]
  PIN dq[63]
    DIRECTION INOUT ;
    USE SIGNAL ;
    PORT
      LAYER M4 ;
        RECT 17.016 20.256 17.208 20.280 ;
    END
  END dq[63]
  PIN dq[64]
    DIRECTION INOUT ;
    USE SIGNAL ;
    PORT
      LAYER M4 ;
        RECT 17.016 20.352 17.208 20.376 ;
    END
  END dq[64]
  PIN dq[65]
    DIRECTION INOUT ;
    USE SIGNAL ;
    PORT
      LAYER M4 ;
        RECT 17.016 20.448 17.208 20.472 ;
    END
  END dq[65]
  PIN dq[66]
    DIRECTION INOUT ;
    USE SIGNAL ;
    PORT
      LAYER M4 ;
        RECT 17.016 20.544 17.208 20.568 ;
    END
  END dq[66]
  PIN dq[67]
    DIRECTION INOUT ;
    USE SIGNAL ;
    PORT
      LAYER M4 ;
        RECT 17.016 20.640 17.208 20.664 ;
    END
  END dq[67]
  PIN dq[68]
    DIRECTION INOUT ;
    USE SIGNAL ;
    PORT
      LAYER M4 ;
        RECT 17.016 20.736 17.208 20.760 ;
    END
  END dq[68]
  PIN dq[69]
    DIRECTION INOUT ;
    USE SIGNAL ;
    PORT
      LAYER M4 ;
        RECT 17.016 7.584 17.208 7.608 ;
    END
  END dq[69]
  PIN dq[70]
    DIRECTION INOUT ;
    USE SIGNAL ;
    PORT
      LAYER M4 ;
        RECT 17.016 7.680 17.208 7.704 ;
    END
  END dq[70]
  PIN dq[71]
    DIRECTION INOUT ;
    USE SIGNAL ;
    PORT
      LAYER M4 ;
        RECT 17.016 7.776 17.208 7.800 ;
    END
  END dq[71]
  PIN dq[72]
    DIRECTION INOUT ;
    USE SIGNAL ;
    PORT
      LAYER M4 ;
        RECT 17.016 7.872 17.208 7.896 ;
    END
  END dq[72]
  PIN dq[73]
    DIRECTION INOUT ;
    USE SIGNAL ;
    PORT
      LAYER M4 ;
        RECT 17.016 7.968 17.208 7.992 ;
    END
  END dq[73]
  PIN dq[74]
    DIRECTION INOUT ;
    USE SIGNAL ;
    PORT
      LAYER M4 ;
        RECT 17.016 8.064 17.208 8.088 ;
    END
  END dq[74]
  PIN dq[75]
    DIRECTION INOUT ;
    USE SIGNAL ;
    PORT
      LAYER M4 ;
        RECT 17.016 8.160 17.208 8.184 ;
    END
  END dq[75]
  PIN dq[76]
    DIRECTION INOUT ;
    USE SIGNAL ;
    PORT
      LAYER M4 ;
        RECT 17.016 8.256 17.208 8.280 ;
    END
  END dq[76]
  PIN dq[77]
    DIRECTION INOUT ;
    USE SIGNAL ;
    PORT
      LAYER M4 ;
        RECT 17.016 8.352 17.208 8.376 ;
    END
  END dq[77]
  PIN dq[78]
    DIRECTION INOUT ;
    USE SIGNAL ;
    PORT
      LAYER M4 ;
        RECT 17.016 8.448 17.208 8.472 ;
    END
  END dq[78]
  PIN dq[79]
    DIRECTION INOUT ;
    USE SIGNAL ;
    PORT
      LAYER M4 ;
        RECT 17.016 8.544 17.208 8.568 ;
    END
  END dq[79]
  PIN dq[80]
    DIRECTION INOUT ;
    USE SIGNAL ;
    PORT
      LAYER M4 ;
        RECT 17.016 8.640 17.208 8.664 ;
    END
  END dq[80]
  PIN dq[81]
    DIRECTION INOUT ;
    USE SIGNAL ;
    PORT
      LAYER M4 ;
        RECT 17.016 8.736 17.208 8.760 ;
    END
  END dq[81]
  PIN dq[82]
    DIRECTION INOUT ;
    USE SIGNAL ;
    PORT
      LAYER M4 ;
        RECT 17.016 8.832 17.208 8.856 ;
    END
  END dq[82]
  PIN dq[83]
    DIRECTION INOUT ;
    USE SIGNAL ;
    PORT
      LAYER M4 ;
        RECT 17.016 8.928 17.208 8.952 ;
    END
  END dq[83]
  PIN dq[84]
    DIRECTION INOUT ;
    USE SIGNAL ;
    PORT
      LAYER M4 ;
        RECT 17.016 9.024 17.208 9.048 ;
    END
  END dq[84]
  PIN dq[85]
    DIRECTION INOUT ;
    USE SIGNAL ;
    PORT
      LAYER M4 ;
        RECT 17.016 9.120 17.208 9.144 ;
    END
  END dq[85]
  PIN dq[86]
    DIRECTION INOUT ;
    USE SIGNAL ;
    PORT
      LAYER M4 ;
        RECT 17.016 9.216 17.208 9.240 ;
    END
  END dq[86]
  PIN dq[87]
    DIRECTION INOUT ;
    USE SIGNAL ;
    PORT
      LAYER M4 ;
        RECT 17.016 9.312 17.208 9.336 ;
    END
  END dq[87]
  PIN dq[88]
    DIRECTION INOUT ;
    USE SIGNAL ;
    PORT
      LAYER M4 ;
        RECT 17.016 9.408 17.208 9.432 ;
    END
  END dq[88]
  PIN dq[89]
    DIRECTION INOUT ;
    USE SIGNAL ;
    PORT
      LAYER M4 ;
        RECT 17.016 9.504 17.208 9.528 ;
    END
  END dq[89]
  PIN dq[90]
    DIRECTION INOUT ;
    USE SIGNAL ;
    PORT
      LAYER M4 ;
        RECT 17.016 9.600 17.208 9.624 ;
    END
  END dq[90]
  PIN dq[91]
    DIRECTION INOUT ;
    USE SIGNAL ;
    PORT
      LAYER M4 ;
        RECT 17.016 9.696 17.208 9.720 ;
    END
  END dq[91]
  PIN dq[92]
    DIRECTION INOUT ;
    USE SIGNAL ;
    PORT
      LAYER M4 ;
        RECT 17.016 9.792 17.208 9.816 ;
    END
  END dq[92]
  PIN dq[93]
    DIRECTION INOUT ;
    USE SIGNAL ;
    PORT
      LAYER M4 ;
        RECT 17.016 9.888 17.208 9.912 ;
    END
  END dq[93]
  PIN dq[94]
    DIRECTION INOUT ;
    USE SIGNAL ;
    PORT
      LAYER M4 ;
        RECT 17.016 9.984 17.208 10.008 ;
    END
  END dq[94]
  PIN dq[95]
    DIRECTION INOUT ;
    USE SIGNAL ;
    PORT
      LAYER M4 ;
        RECT 17.016 10.080 17.208 10.104 ;
    END
  END dq[95]
  PIN dq[96]
    DIRECTION INOUT ;
    USE SIGNAL ;
    PORT
      LAYER M4 ;
        RECT 17.016 10.176 17.208 10.200 ;
    END
  END dq[96]
  PIN dq[97]
    DIRECTION INOUT ;
    USE SIGNAL ;
    PORT
      LAYER M4 ;
        RECT 17.016 10.272 17.208 10.296 ;
    END
  END dq[97]
  PIN dq[98]
    DIRECTION INOUT ;
    USE SIGNAL ;
    PORT
      LAYER M4 ;
        RECT 17.016 10.368 17.208 10.392 ;
    END
  END dq[98]
  PIN dq[99]
    DIRECTION INOUT ;
    USE SIGNAL ;
    PORT
      LAYER M4 ;
        RECT 17.016 10.464 17.208 10.488 ;
    END
  END dq[99]
  PIN dq[100]
    DIRECTION INOUT ;
    USE SIGNAL ;
    PORT
      LAYER M4 ;
        RECT 17.016 10.560 17.208 10.584 ;
    END
  END dq[100]
  PIN dq[101]
    DIRECTION INOUT ;
    USE SIGNAL ;
    PORT
      LAYER M4 ;
        RECT 17.016 10.656 17.208 10.680 ;
    END
  END dq[101]
  PIN dq[102]
    DIRECTION INOUT ;
    USE SIGNAL ;
    PORT
      LAYER M4 ;
        RECT 17.016 10.752 17.208 10.776 ;
    END
  END dq[102]
  PIN dq[103]
    DIRECTION INOUT ;
    USE SIGNAL ;
    PORT
      LAYER M4 ;
        RECT 17.016 10.848 17.208 10.872 ;
    END
  END dq[103]
  PIN dq[104]
    DIRECTION INOUT ;
    USE SIGNAL ;
    PORT
      LAYER M4 ;
        RECT 17.016 10.944 17.208 10.968 ;
    END
  END dq[104]
  PIN dq[105]
    DIRECTION INOUT ;
    USE SIGNAL ;
    PORT
      LAYER M4 ;
        RECT 17.016 11.040 17.208 11.064 ;
    END
  END dq[105]
  PIN dq[106]
    DIRECTION INOUT ;
    USE SIGNAL ;
    PORT
      LAYER M4 ;
        RECT 17.016 11.136 17.208 11.160 ;
    END
  END dq[106]
  PIN dq[107]
    DIRECTION INOUT ;
    USE SIGNAL ;
    PORT
      LAYER M4 ;
        RECT 17.016 11.232 17.208 11.256 ;
    END
  END dq[107]
  PIN dq[108]
    DIRECTION INOUT ;
    USE SIGNAL ;
    PORT
      LAYER M4 ;
        RECT 17.016 11.328 17.208 11.352 ;
    END
  END dq[108]
  PIN dq[109]
    DIRECTION INOUT ;
    USE SIGNAL ;
    PORT
      LAYER M4 ;
        RECT 17.016 11.424 17.208 11.448 ;
    END
  END dq[109]
  PIN dq[110]
    DIRECTION INOUT ;
    USE SIGNAL ;
    PORT
      LAYER M4 ;
        RECT 17.016 11.520 17.208 11.544 ;
    END
  END dq[110]
  PIN dq[111]
    DIRECTION INOUT ;
    USE SIGNAL ;
    PORT
      LAYER M4 ;
        RECT 17.016 11.616 17.208 11.640 ;
    END
  END dq[111]
  PIN dq[112]
    DIRECTION INOUT ;
    USE SIGNAL ;
    PORT
      LAYER M4 ;
        RECT 17.016 11.712 17.208 11.736 ;
    END
  END dq[112]
  PIN dq[113]
    DIRECTION INOUT ;
    USE SIGNAL ;
    PORT
      LAYER M4 ;
        RECT 17.016 11.808 17.208 11.832 ;
    END
  END dq[113]
  PIN dq[114]
    DIRECTION INOUT ;
    USE SIGNAL ;
    PORT
      LAYER M4 ;
        RECT 17.016 11.904 17.208 11.928 ;
    END
  END dq[114]
  PIN dq[115]
    DIRECTION INOUT ;
    USE SIGNAL ;
    PORT
      LAYER M4 ;
        RECT 17.016 12.000 17.208 12.024 ;
    END
  END dq[115]
  PIN dq[116]
    DIRECTION INOUT ;
    USE SIGNAL ;
    PORT
      LAYER M4 ;
        RECT 17.016 12.096 17.208 12.120 ;
    END
  END dq[116]
  PIN dq[117]
    DIRECTION INOUT ;
    USE SIGNAL ;
    PORT
      LAYER M4 ;
        RECT 17.016 12.192 17.208 12.216 ;
    END
  END dq[117]
  PIN dq[118]
    DIRECTION INOUT ;
    USE SIGNAL ;
    PORT
      LAYER M4 ;
        RECT 17.016 12.288 17.208 12.312 ;
    END
  END dq[118]
  PIN dq[119]
    DIRECTION INOUT ;
    USE SIGNAL ;
    PORT
      LAYER M4 ;
        RECT 17.016 12.384 17.208 12.408 ;
    END
  END dq[119]
  PIN dq[120]
    DIRECTION INOUT ;
    USE SIGNAL ;
    PORT
      LAYER M4 ;
        RECT 17.016 12.480 17.208 12.504 ;
    END
  END dq[120]
  PIN dq[121]
    DIRECTION INOUT ;
    USE SIGNAL ;
    PORT
      LAYER M4 ;
        RECT 17.016 12.576 17.208 12.600 ;
    END
  END dq[121]
  PIN dq[122]
    DIRECTION INOUT ;
    USE SIGNAL ;
    PORT
      LAYER M4 ;
        RECT 17.016 12.672 17.208 12.696 ;
    END
  END dq[122]
  PIN dq[123]
    DIRECTION INOUT ;
    USE SIGNAL ;
    PORT
      LAYER M4 ;
        RECT 17.016 12.768 17.208 12.792 ;
    END
  END dq[123]
  PIN dq[124]
    DIRECTION INOUT ;
    USE SIGNAL ;
    PORT
      LAYER M4 ;
        RECT 17.016 12.864 17.208 12.888 ;
    END
  END dq[124]
  PIN dq[125]
    DIRECTION INOUT ;
    USE SIGNAL ;
    PORT
      LAYER M4 ;
        RECT 17.016 12.960 17.208 12.984 ;
    END
  END dq[125]
  PIN dq[126]
    DIRECTION INOUT ;
    USE SIGNAL ;
    PORT
      LAYER M4 ;
        RECT 17.016 13.056 17.208 13.080 ;
    END
  END dq[126]
  PIN dq[127]
    DIRECTION INOUT ;
    USE SIGNAL ;
    PORT
      LAYER M4 ;
        RECT 17.016 13.152 17.208 13.176 ;
    END
  END dq[127]
  PIN dq[128]
    DIRECTION INOUT ;
    USE SIGNAL ;
    PORT
      LAYER M4 ;
        RECT 17.016 13.248 17.208 13.272 ;
    END
  END dq[128]
  PIN dq[129]
    DIRECTION INOUT ;
    USE SIGNAL ;
    PORT
      LAYER M4 ;
        RECT 17.016 13.344 17.208 13.368 ;
    END
  END dq[129]
  PIN dq[130]
    DIRECTION INOUT ;
    USE SIGNAL ;
    PORT
      LAYER M4 ;
        RECT 17.016 13.440 17.208 13.464 ;
    END
  END dq[130]
  PIN dq[131]
    DIRECTION INOUT ;
    USE SIGNAL ;
    PORT
      LAYER M4 ;
        RECT 17.016 13.536 17.208 13.560 ;
    END
  END dq[131]
  PIN dq[132]
    DIRECTION INOUT ;
    USE SIGNAL ;
    PORT
      LAYER M4 ;
        RECT 17.016 13.632 17.208 13.656 ;
    END
  END dq[132]
  PIN dq[133]
    DIRECTION INOUT ;
    USE SIGNAL ;
    PORT
      LAYER M4 ;
        RECT 17.016 13.728 17.208 13.752 ;
    END
  END dq[133]
  PIN dq[134]
    DIRECTION INOUT ;
    USE SIGNAL ;
    PORT
      LAYER M4 ;
        RECT 17.016 13.824 17.208 13.848 ;
    END
  END dq[134]
  PIN dq[135]
    DIRECTION INOUT ;
    USE SIGNAL ;
    PORT
      LAYER M4 ;
        RECT 17.016 13.920 17.208 13.944 ;
    END
  END dq[135]
  PIN dq[136]
    DIRECTION INOUT ;
    USE SIGNAL ;
    PORT
      LAYER M4 ;
        RECT 17.016 14.016 17.208 14.040 ;
    END
  END dq[136]
  PIN dq[137]
    DIRECTION INOUT ;
    USE SIGNAL ;
    PORT
      LAYER M4 ;
        RECT 17.016 14.112 17.208 14.136 ;
    END
  END dq[137]
  PIN dq[138]
    DIRECTION INOUT ;
    USE SIGNAL ;
    PORT
      LAYER M4 ;
        RECT 17.016 0.960 17.208 0.984 ;
    END
  END dq[138]
  PIN dq[139]
    DIRECTION INOUT ;
    USE SIGNAL ;
    PORT
      LAYER M4 ;
        RECT 17.016 1.056 17.208 1.080 ;
    END
  END dq[139]
  PIN dq[140]
    DIRECTION INOUT ;
    USE SIGNAL ;
    PORT
      LAYER M4 ;
        RECT 17.016 1.152 17.208 1.176 ;
    END
  END dq[140]
  PIN dq[141]
    DIRECTION INOUT ;
    USE SIGNAL ;
    PORT
      LAYER M4 ;
        RECT 17.016 1.248 17.208 1.272 ;
    END
  END dq[141]
  PIN dq[142]
    DIRECTION INOUT ;
    USE SIGNAL ;
    PORT
      LAYER M4 ;
        RECT 17.016 1.344 17.208 1.368 ;
    END
  END dq[142]
  PIN dq[143]
    DIRECTION INOUT ;
    USE SIGNAL ;
    PORT
      LAYER M4 ;
        RECT 17.016 1.440 17.208 1.464 ;
    END
  END dq[143]
  PIN dq[144]
    DIRECTION INOUT ;
    USE SIGNAL ;
    PORT
      LAYER M4 ;
        RECT 17.016 1.536 17.208 1.560 ;
    END
  END dq[144]
  PIN dq[145]
    DIRECTION INOUT ;
    USE SIGNAL ;
    PORT
      LAYER M4 ;
        RECT 17.016 1.632 17.208 1.656 ;
    END
  END dq[145]
  PIN dq[146]
    DIRECTION INOUT ;
    USE SIGNAL ;
    PORT
      LAYER M4 ;
        RECT 17.016 1.728 17.208 1.752 ;
    END
  END dq[146]
  PIN dq[147]
    DIRECTION INOUT ;
    USE SIGNAL ;
    PORT
      LAYER M4 ;
        RECT 17.016 1.824 17.208 1.848 ;
    END
  END dq[147]
  PIN dq[148]
    DIRECTION INOUT ;
    USE SIGNAL ;
    PORT
      LAYER M4 ;
        RECT 17.016 1.920 17.208 1.944 ;
    END
  END dq[148]
  PIN dq[149]
    DIRECTION INOUT ;
    USE SIGNAL ;
    PORT
      LAYER M4 ;
        RECT 17.016 2.016 17.208 2.040 ;
    END
  END dq[149]
  PIN dq[150]
    DIRECTION INOUT ;
    USE SIGNAL ;
    PORT
      LAYER M4 ;
        RECT 17.016 2.112 17.208 2.136 ;
    END
  END dq[150]
  PIN dq[151]
    DIRECTION INOUT ;
    USE SIGNAL ;
    PORT
      LAYER M4 ;
        RECT 17.016 2.208 17.208 2.232 ;
    END
  END dq[151]
  PIN dq[152]
    DIRECTION INOUT ;
    USE SIGNAL ;
    PORT
      LAYER M4 ;
        RECT 17.016 2.304 17.208 2.328 ;
    END
  END dq[152]
  PIN dq[153]
    DIRECTION INOUT ;
    USE SIGNAL ;
    PORT
      LAYER M4 ;
        RECT 17.016 2.400 17.208 2.424 ;
    END
  END dq[153]
  PIN dq[154]
    DIRECTION INOUT ;
    USE SIGNAL ;
    PORT
      LAYER M4 ;
        RECT 17.016 2.496 17.208 2.520 ;
    END
  END dq[154]
  PIN dq[155]
    DIRECTION INOUT ;
    USE SIGNAL ;
    PORT
      LAYER M4 ;
        RECT 17.016 2.592 17.208 2.616 ;
    END
  END dq[155]
  PIN dq[156]
    DIRECTION INOUT ;
    USE SIGNAL ;
    PORT
      LAYER M4 ;
        RECT 17.016 2.688 17.208 2.712 ;
    END
  END dq[156]
  PIN dq[157]
    DIRECTION INOUT ;
    USE SIGNAL ;
    PORT
      LAYER M4 ;
        RECT 17.016 2.784 17.208 2.808 ;
    END
  END dq[157]
  PIN dq[158]
    DIRECTION INOUT ;
    USE SIGNAL ;
    PORT
      LAYER M4 ;
        RECT 17.016 2.880 17.208 2.904 ;
    END
  END dq[158]
  PIN dq[159]
    DIRECTION INOUT ;
    USE SIGNAL ;
    PORT
      LAYER M4 ;
        RECT 17.016 2.976 17.208 3.000 ;
    END
  END dq[159]
  PIN dq[160]
    DIRECTION INOUT ;
    USE SIGNAL ;
    PORT
      LAYER M4 ;
        RECT 17.016 3.072 17.208 3.096 ;
    END
  END dq[160]
  PIN dq[161]
    DIRECTION INOUT ;
    USE SIGNAL ;
    PORT
      LAYER M4 ;
        RECT 17.016 3.168 17.208 3.192 ;
    END
  END dq[161]
  PIN dq[162]
    DIRECTION INOUT ;
    USE SIGNAL ;
    PORT
      LAYER M4 ;
        RECT 17.016 3.264 17.208 3.288 ;
    END
  END dq[162]
  PIN dq[163]
    DIRECTION INOUT ;
    USE SIGNAL ;
    PORT
      LAYER M4 ;
        RECT 17.016 3.360 17.208 3.384 ;
    END
  END dq[163]
  PIN dq[164]
    DIRECTION INOUT ;
    USE SIGNAL ;
    PORT
      LAYER M4 ;
        RECT 17.016 3.456 17.208 3.480 ;
    END
  END dq[164]
  PIN dq[165]
    DIRECTION INOUT ;
    USE SIGNAL ;
    PORT
      LAYER M4 ;
        RECT 17.016 3.552 17.208 3.576 ;
    END
  END dq[165]
  PIN dq[166]
    DIRECTION INOUT ;
    USE SIGNAL ;
    PORT
      LAYER M4 ;
        RECT 17.016 3.648 17.208 3.672 ;
    END
  END dq[166]
  PIN dq[167]
    DIRECTION INOUT ;
    USE SIGNAL ;
    PORT
      LAYER M4 ;
        RECT 17.016 3.744 17.208 3.768 ;
    END
  END dq[167]
  PIN dq[168]
    DIRECTION INOUT ;
    USE SIGNAL ;
    PORT
      LAYER M4 ;
        RECT 17.016 3.840 17.208 3.864 ;
    END
  END dq[168]
  PIN dq[169]
    DIRECTION INOUT ;
    USE SIGNAL ;
    PORT
      LAYER M4 ;
        RECT 17.016 3.936 17.208 3.960 ;
    END
  END dq[169]
  PIN dq[170]
    DIRECTION INOUT ;
    USE SIGNAL ;
    PORT
      LAYER M4 ;
        RECT 17.016 4.032 17.208 4.056 ;
    END
  END dq[170]
  PIN dq[171]
    DIRECTION INOUT ;
    USE SIGNAL ;
    PORT
      LAYER M4 ;
        RECT 17.016 4.128 17.208 4.152 ;
    END
  END dq[171]
  PIN dq[172]
    DIRECTION INOUT ;
    USE SIGNAL ;
    PORT
      LAYER M4 ;
        RECT 17.016 4.224 17.208 4.248 ;
    END
  END dq[172]
  PIN dq[173]
    DIRECTION INOUT ;
    USE SIGNAL ;
    PORT
      LAYER M4 ;
        RECT 17.016 4.320 17.208 4.344 ;
    END
  END dq[173]
  PIN dq[174]
    DIRECTION INOUT ;
    USE SIGNAL ;
    PORT
      LAYER M4 ;
        RECT 17.016 4.416 17.208 4.440 ;
    END
  END dq[174]
  PIN dq[175]
    DIRECTION INOUT ;
    USE SIGNAL ;
    PORT
      LAYER M4 ;
        RECT 17.016 4.512 17.208 4.536 ;
    END
  END dq[175]
  PIN dq[176]
    DIRECTION INOUT ;
    USE SIGNAL ;
    PORT
      LAYER M4 ;
        RECT 17.016 4.608 17.208 4.632 ;
    END
  END dq[176]
  PIN dq[177]
    DIRECTION INOUT ;
    USE SIGNAL ;
    PORT
      LAYER M4 ;
        RECT 17.016 4.704 17.208 4.728 ;
    END
  END dq[177]
  PIN dq[178]
    DIRECTION INOUT ;
    USE SIGNAL ;
    PORT
      LAYER M4 ;
        RECT 17.016 4.800 17.208 4.824 ;
    END
  END dq[178]
  PIN dq[179]
    DIRECTION INOUT ;
    USE SIGNAL ;
    PORT
      LAYER M4 ;
        RECT 17.016 4.896 17.208 4.920 ;
    END
  END dq[179]
  PIN dq[180]
    DIRECTION INOUT ;
    USE SIGNAL ;
    PORT
      LAYER M4 ;
        RECT 17.016 4.992 17.208 5.016 ;
    END
  END dq[180]
  PIN dq[181]
    DIRECTION INOUT ;
    USE SIGNAL ;
    PORT
      LAYER M4 ;
        RECT 17.016 5.088 17.208 5.112 ;
    END
  END dq[181]
  PIN dq[182]
    DIRECTION INOUT ;
    USE SIGNAL ;
    PORT
      LAYER M4 ;
        RECT 17.016 5.184 17.208 5.208 ;
    END
  END dq[182]
  PIN dq[183]
    DIRECTION INOUT ;
    USE SIGNAL ;
    PORT
      LAYER M4 ;
        RECT 17.016 5.280 17.208 5.304 ;
    END
  END dq[183]
  PIN dq[184]
    DIRECTION INOUT ;
    USE SIGNAL ;
    PORT
      LAYER M4 ;
        RECT 17.016 5.376 17.208 5.400 ;
    END
  END dq[184]
  PIN dq[185]
    DIRECTION INOUT ;
    USE SIGNAL ;
    PORT
      LAYER M4 ;
        RECT 17.016 5.472 17.208 5.496 ;
    END
  END dq[185]
  PIN dq[186]
    DIRECTION INOUT ;
    USE SIGNAL ;
    PORT
      LAYER M4 ;
        RECT 17.016 5.568 17.208 5.592 ;
    END
  END dq[186]
  PIN dq[187]
    DIRECTION INOUT ;
    USE SIGNAL ;
    PORT
      LAYER M4 ;
        RECT 17.016 5.664 17.208 5.688 ;
    END
  END dq[187]
  PIN dq[188]
    DIRECTION INOUT ;
    USE SIGNAL ;
    PORT
      LAYER M4 ;
        RECT 17.016 5.760 17.208 5.784 ;
    END
  END dq[188]
  PIN dq[189]
    DIRECTION INOUT ;
    USE SIGNAL ;
    PORT
      LAYER M4 ;
        RECT 17.016 5.856 17.208 5.880 ;
    END
  END dq[189]
  PIN dq[190]
    DIRECTION INOUT ;
    USE SIGNAL ;
    PORT
      LAYER M4 ;
        RECT 17.016 5.952 17.208 5.976 ;
    END
  END dq[190]
  PIN dq[191]
    DIRECTION INOUT ;
    USE SIGNAL ;
    PORT
      LAYER M4 ;
        RECT 17.016 6.048 17.208 6.072 ;
    END
  END dq[191]
  PIN dq[192]
    DIRECTION INOUT ;
    USE SIGNAL ;
    PORT
      LAYER M4 ;
        RECT 17.016 6.144 17.208 6.168 ;
    END
  END dq[192]
  PIN dq[193]
    DIRECTION INOUT ;
    USE SIGNAL ;
    PORT
      LAYER M4 ;
        RECT 17.016 6.240 17.208 6.264 ;
    END
  END dq[193]
  PIN dq[194]
    DIRECTION INOUT ;
    USE SIGNAL ;
    PORT
      LAYER M4 ;
        RECT 17.016 6.336 17.208 6.360 ;
    END
  END dq[194]
  PIN dq[195]
    DIRECTION INOUT ;
    USE SIGNAL ;
    PORT
      LAYER M4 ;
        RECT 17.016 6.432 17.208 6.456 ;
    END
  END dq[195]
  PIN dq[196]
    DIRECTION INOUT ;
    USE SIGNAL ;
    PORT
      LAYER M4 ;
        RECT 17.016 6.528 17.208 6.552 ;
    END
  END dq[196]
  PIN dq[197]
    DIRECTION INOUT ;
    USE SIGNAL ;
    PORT
      LAYER M4 ;
        RECT 17.016 6.624 17.208 6.648 ;
    END
  END dq[197]
  PIN dq[198]
    DIRECTION INOUT ;
    USE SIGNAL ;
    PORT
      LAYER M4 ;
        RECT 17.016 6.720 17.208 6.744 ;
    END
  END dq[198]
  PIN dq[199]
    DIRECTION INOUT ;
    USE SIGNAL ;
    PORT
      LAYER M4 ;
        RECT 17.016 6.816 17.208 6.840 ;
    END
  END dq[199]
  PIN dq[200]
    DIRECTION INOUT ;
    USE SIGNAL ;
    PORT
      LAYER M4 ;
        RECT 17.016 6.912 17.208 6.936 ;
    END
  END dq[200]
  PIN dq[201]
    DIRECTION INOUT ;
    USE SIGNAL ;
    PORT
      LAYER M4 ;
        RECT 17.016 7.008 17.208 7.032 ;
    END
  END dq[201]
  PIN dq[202]
    DIRECTION INOUT ;
    USE SIGNAL ;
    PORT
      LAYER M4 ;
        RECT 17.016 7.104 17.208 7.128 ;
    END
  END dq[202]
  PIN dq[203]
    DIRECTION INOUT ;
    USE SIGNAL ;
    PORT
      LAYER M4 ;
        RECT 17.016 7.200 17.208 7.224 ;
    END
  END dq[203]
  PIN dq[204]
    DIRECTION INOUT ;
    USE SIGNAL ;
    PORT
      LAYER M4 ;
        RECT 17.016 7.296 17.208 7.320 ;
    END
  END dq[204]
  PIN dq[205]
    DIRECTION INOUT ;
    USE SIGNAL ;
    PORT
      LAYER M4 ;
        RECT 17.016 7.392 17.208 7.416 ;
    END
  END dq[205]
  PIN dq[206]
    DIRECTION INOUT ;
    USE SIGNAL ;
    PORT
      LAYER M4 ;
        RECT 17.016 7.488 17.208 7.512 ;
    END
  END dq[206]
  PIN ck[0]
    DIRECTION INOUT ;
    USE SIGNAL ;
    PORT
      LAYER M5 ;
        RECT 8.592 21.360 8.616 21.552 ;
    END
  END ck[0]
  OBS
    LAYER M1 ;
      RECT 0 0 17.256 21.600 ;
    LAYER M2 ;
      RECT 0 0 17.256 21.600 ;
    LAYER M3 ;
      RECT 0 0 17.256 21.600 ;
  END
END dsfd_hstnh_207_sp2
